VERSION 5.8 ;
BUSBITCHARS "[]" ;
DIVIDERCHAR "/" ;
UNITS
    DATABASE MICRONS 1000 ;
END UNITS

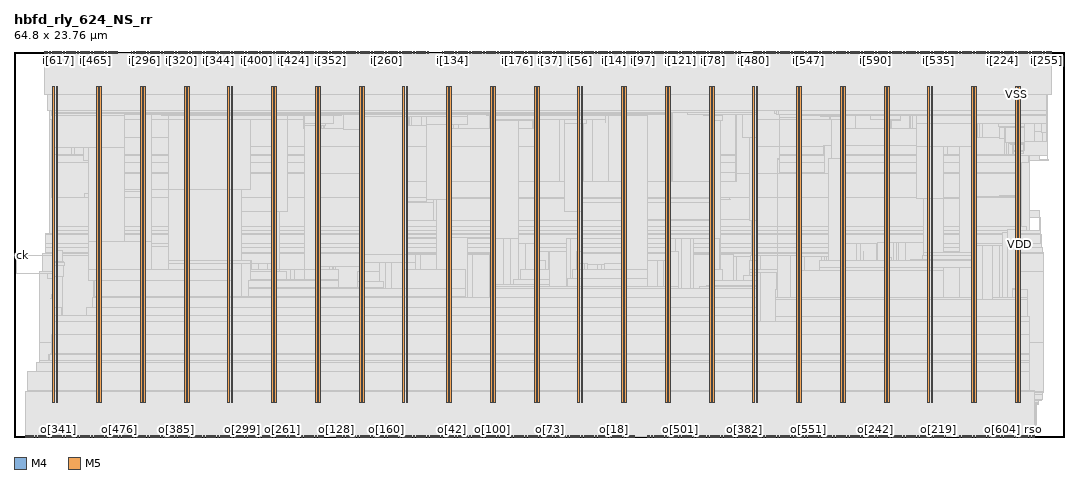
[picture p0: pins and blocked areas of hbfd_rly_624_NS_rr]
MACRO hbfd_rly_624_NS_rr
  FOREIGN hbfd_rly_624_NS_rr 0 0 ;
  CLASS BLOCK ;
  SIZE 64.8 BY 23.76 ;
  PIN ck
    DIRECTION INPUT ;
    USE SIGNAL ;
    PORT
      LAYER M4 ;
        RECT  0 11.184 0.084 11.208 ;
    END
  END ck
  PIN i[0]
    DIRECTION INPUT ;
    USE SIGNAL ;
    PORT
      LAYER M5 ;
        RECT  35.664 23.676 35.688 23.76 ;
    END
  END i[0]
  PIN i[100]
    DIRECTION INPUT ;
    USE SIGNAL ;
    PORT
      LAYER M5 ;
        RECT  39.12 23.676 39.144 23.76 ;
    END
  END i[100]
  PIN i[101]
    DIRECTION INPUT ;
    USE SIGNAL ;
    PORT
      LAYER M5 ;
        RECT  39.216 23.676 39.24 23.76 ;
    END
  END i[101]
  PIN i[102]
    DIRECTION INPUT ;
    USE SIGNAL ;
    PORT
      LAYER M5 ;
        RECT  39.312 23.676 39.336 23.76 ;
    END
  END i[102]
  PIN i[103]
    DIRECTION INPUT ;
    USE SIGNAL ;
    PORT
      LAYER M5 ;
        RECT  39.408 23.676 39.432 23.76 ;
    END
  END i[103]
  PIN i[104]
    DIRECTION INPUT ;
    USE SIGNAL ;
    PORT
      LAYER M5 ;
        RECT  39.504 23.676 39.528 23.76 ;
    END
  END i[104]
  PIN i[105]
    DIRECTION INPUT ;
    USE SIGNAL ;
    PORT
      LAYER M5 ;
        RECT  39.6 23.676 39.624 23.76 ;
    END
  END i[105]
  PIN i[106]
    DIRECTION INPUT ;
    USE SIGNAL ;
    PORT
      LAYER M5 ;
        RECT  39.696 23.676 39.72 23.76 ;
    END
  END i[106]
  PIN i[107]
    DIRECTION INPUT ;
    USE SIGNAL ;
    PORT
      LAYER M5 ;
        RECT  39.792 23.676 39.816 23.76 ;
    END
  END i[107]
  PIN i[108]
    DIRECTION INPUT ;
    USE SIGNAL ;
    PORT
      LAYER M5 ;
        RECT  39.888 23.676 39.912 23.76 ;
    END
  END i[108]
  PIN i[109]
    DIRECTION INPUT ;
    USE SIGNAL ;
    PORT
      LAYER M5 ;
        RECT  39.984 23.676 40.008 23.76 ;
    END
  END i[109]
  PIN i[10]
    DIRECTION INPUT ;
    USE SIGNAL ;
    PORT
      LAYER M5 ;
        RECT  36.624 23.676 36.648 23.76 ;
    END
  END i[10]
  PIN i[110]
    DIRECTION INPUT ;
    USE SIGNAL ;
    PORT
      LAYER M5 ;
        RECT  40.08 23.676 40.104 23.76 ;
    END
  END i[110]
  PIN i[111]
    DIRECTION INPUT ;
    USE SIGNAL ;
    PORT
      LAYER M5 ;
        RECT  40.176 23.676 40.2 23.76 ;
    END
  END i[111]
  PIN i[112]
    DIRECTION INPUT ;
    USE SIGNAL ;
    PORT
      LAYER M5 ;
        RECT  40.272 23.676 40.296 23.76 ;
    END
  END i[112]
  PIN i[113]
    DIRECTION INPUT ;
    USE SIGNAL ;
    PORT
      LAYER M5 ;
        RECT  40.368 23.676 40.392 23.76 ;
    END
  END i[113]
  PIN i[114]
    DIRECTION INPUT ;
    USE SIGNAL ;
    PORT
      LAYER M5 ;
        RECT  40.464 23.676 40.488 23.76 ;
    END
  END i[114]
  PIN i[115]
    DIRECTION INPUT ;
    USE SIGNAL ;
    PORT
      LAYER M5 ;
        RECT  40.56 23.676 40.584 23.76 ;
    END
  END i[115]
  PIN i[116]
    DIRECTION INPUT ;
    USE SIGNAL ;
    PORT
      LAYER M5 ;
        RECT  40.656 23.676 40.68 23.76 ;
    END
  END i[116]
  PIN i[117]
    DIRECTION INPUT ;
    USE SIGNAL ;
    PORT
      LAYER M5 ;
        RECT  40.752 23.676 40.776 23.76 ;
    END
  END i[117]
  PIN i[118]
    DIRECTION INPUT ;
    USE SIGNAL ;
    PORT
      LAYER M5 ;
        RECT  40.848 23.676 40.872 23.76 ;
    END
  END i[118]
  PIN i[119]
    DIRECTION INPUT ;
    USE SIGNAL ;
    PORT
      LAYER M5 ;
        RECT  40.944 23.676 40.968 23.76 ;
    END
  END i[119]
  PIN i[11]
    DIRECTION INPUT ;
    USE SIGNAL ;
    PORT
      LAYER M5 ;
        RECT  36.72 23.676 36.744 23.76 ;
    END
  END i[11]
  PIN i[120]
    DIRECTION INPUT ;
    USE SIGNAL ;
    PORT
      LAYER M5 ;
        RECT  41.04 23.676 41.064 23.76 ;
    END
  END i[120]
  PIN i[121]
    DIRECTION INPUT ;
    USE SIGNAL ;
    PORT
      LAYER M5 ;
        RECT  41.136 23.676 41.16 23.76 ;
    END
  END i[121]
  PIN i[122]
    DIRECTION INPUT ;
    USE SIGNAL ;
    PORT
      LAYER M5 ;
        RECT  41.232 23.676 41.256 23.76 ;
    END
  END i[122]
  PIN i[123]
    DIRECTION INPUT ;
    USE SIGNAL ;
    PORT
      LAYER M5 ;
        RECT  41.328 23.676 41.352 23.76 ;
    END
  END i[123]
  PIN i[124]
    DIRECTION INPUT ;
    USE SIGNAL ;
    PORT
      LAYER M5 ;
        RECT  41.424 23.676 41.448 23.76 ;
    END
  END i[124]
  PIN i[125]
    DIRECTION INPUT ;
    USE SIGNAL ;
    PORT
      LAYER M5 ;
        RECT  41.52 23.676 41.544 23.76 ;
    END
  END i[125]
  PIN i[126]
    DIRECTION INPUT ;
    USE SIGNAL ;
    PORT
      LAYER M5 ;
        RECT  41.616 23.676 41.64 23.76 ;
    END
  END i[126]
  PIN i[127]
    DIRECTION INPUT ;
    USE SIGNAL ;
    PORT
      LAYER M5 ;
        RECT  41.712 23.676 41.736 23.76 ;
    END
  END i[127]
  PIN i[128]
    DIRECTION INPUT ;
    USE SIGNAL ;
    PORT
      LAYER M5 ;
        RECT  26.448 23.676 26.472 23.76 ;
    END
  END i[128]
  PIN i[129]
    DIRECTION INPUT ;
    USE SIGNAL ;
    PORT
      LAYER M5 ;
        RECT  26.544 23.676 26.568 23.76 ;
    END
  END i[129]
  PIN i[12]
    DIRECTION INPUT ;
    USE SIGNAL ;
    PORT
      LAYER M5 ;
        RECT  36.816 23.676 36.84 23.76 ;
    END
  END i[12]
  PIN i[130]
    DIRECTION INPUT ;
    USE SIGNAL ;
    PORT
      LAYER M5 ;
        RECT  26.64 23.676 26.664 23.76 ;
    END
  END i[130]
  PIN i[131]
    DIRECTION INPUT ;
    USE SIGNAL ;
    PORT
      LAYER M5 ;
        RECT  26.736 23.676 26.76 23.76 ;
    END
  END i[131]
  PIN i[132]
    DIRECTION INPUT ;
    USE SIGNAL ;
    PORT
      LAYER M5 ;
        RECT  26.832 23.676 26.856 23.76 ;
    END
  END i[132]
  PIN i[133]
    DIRECTION INPUT ;
    USE SIGNAL ;
    PORT
      LAYER M5 ;
        RECT  26.928 23.676 26.952 23.76 ;
    END
  END i[133]
  PIN i[134]
    DIRECTION INPUT ;
    USE SIGNAL ;
    PORT
      LAYER M5 ;
        RECT  27.024 23.676 27.048 23.76 ;
    END
  END i[134]
  PIN i[135]
    DIRECTION INPUT ;
    USE SIGNAL ;
    PORT
      LAYER M5 ;
        RECT  27.12 23.676 27.144 23.76 ;
    END
  END i[135]
  PIN i[136]
    DIRECTION INPUT ;
    USE SIGNAL ;
    PORT
      LAYER M5 ;
        RECT  27.216 23.676 27.24 23.76 ;
    END
  END i[136]
  PIN i[137]
    DIRECTION INPUT ;
    USE SIGNAL ;
    PORT
      LAYER M5 ;
        RECT  27.312 23.676 27.336 23.76 ;
    END
  END i[137]
  PIN i[138]
    DIRECTION INPUT ;
    USE SIGNAL ;
    PORT
      LAYER M5 ;
        RECT  27.408 23.676 27.432 23.76 ;
    END
  END i[138]
  PIN i[139]
    DIRECTION INPUT ;
    USE SIGNAL ;
    PORT
      LAYER M5 ;
        RECT  27.504 23.676 27.528 23.76 ;
    END
  END i[139]
  PIN i[13]
    DIRECTION INPUT ;
    USE SIGNAL ;
    PORT
      LAYER M5 ;
        RECT  36.912 23.676 36.936 23.76 ;
    END
  END i[13]
  PIN i[140]
    DIRECTION INPUT ;
    USE SIGNAL ;
    PORT
      LAYER M5 ;
        RECT  27.6 23.676 27.624 23.76 ;
    END
  END i[140]
  PIN i[141]
    DIRECTION INPUT ;
    USE SIGNAL ;
    PORT
      LAYER M5 ;
        RECT  27.696 23.676 27.72 23.76 ;
    END
  END i[141]
  PIN i[142]
    DIRECTION INPUT ;
    USE SIGNAL ;
    PORT
      LAYER M5 ;
        RECT  27.792 23.676 27.816 23.76 ;
    END
  END i[142]
  PIN i[143]
    DIRECTION INPUT ;
    USE SIGNAL ;
    PORT
      LAYER M5 ;
        RECT  27.888 23.676 27.912 23.76 ;
    END
  END i[143]
  PIN i[144]
    DIRECTION INPUT ;
    USE SIGNAL ;
    PORT
      LAYER M5 ;
        RECT  27.984 23.676 28.008 23.76 ;
    END
  END i[144]
  PIN i[145]
    DIRECTION INPUT ;
    USE SIGNAL ;
    PORT
      LAYER M5 ;
        RECT  28.08 23.676 28.104 23.76 ;
    END
  END i[145]
  PIN i[146]
    DIRECTION INPUT ;
    USE SIGNAL ;
    PORT
      LAYER M5 ;
        RECT  28.176 23.676 28.2 23.76 ;
    END
  END i[146]
  PIN i[147]
    DIRECTION INPUT ;
    USE SIGNAL ;
    PORT
      LAYER M5 ;
        RECT  28.272 23.676 28.296 23.76 ;
    END
  END i[147]
  PIN i[148]
    DIRECTION INPUT ;
    USE SIGNAL ;
    PORT
      LAYER M5 ;
        RECT  28.368 23.676 28.392 23.76 ;
    END
  END i[148]
  PIN i[149]
    DIRECTION INPUT ;
    USE SIGNAL ;
    PORT
      LAYER M5 ;
        RECT  28.464 23.676 28.488 23.76 ;
    END
  END i[149]
  PIN i[14]
    DIRECTION INPUT ;
    USE SIGNAL ;
    PORT
      LAYER M5 ;
        RECT  37.008 23.676 37.032 23.76 ;
    END
  END i[14]
  PIN i[150]
    DIRECTION INPUT ;
    USE SIGNAL ;
    PORT
      LAYER M5 ;
        RECT  28.56 23.676 28.584 23.76 ;
    END
  END i[150]
  PIN i[151]
    DIRECTION INPUT ;
    USE SIGNAL ;
    PORT
      LAYER M5 ;
        RECT  28.656 23.676 28.68 23.76 ;
    END
  END i[151]
  PIN i[152]
    DIRECTION INPUT ;
    USE SIGNAL ;
    PORT
      LAYER M5 ;
        RECT  28.752 23.676 28.776 23.76 ;
    END
  END i[152]
  PIN i[153]
    DIRECTION INPUT ;
    USE SIGNAL ;
    PORT
      LAYER M5 ;
        RECT  28.848 23.676 28.872 23.76 ;
    END
  END i[153]
  PIN i[154]
    DIRECTION INPUT ;
    USE SIGNAL ;
    PORT
      LAYER M5 ;
        RECT  28.944 23.676 28.968 23.76 ;
    END
  END i[154]
  PIN i[155]
    DIRECTION INPUT ;
    USE SIGNAL ;
    PORT
      LAYER M5 ;
        RECT  29.04 23.676 29.064 23.76 ;
    END
  END i[155]
  PIN i[156]
    DIRECTION INPUT ;
    USE SIGNAL ;
    PORT
      LAYER M5 ;
        RECT  29.136 23.676 29.16 23.76 ;
    END
  END i[156]
  PIN i[157]
    DIRECTION INPUT ;
    USE SIGNAL ;
    PORT
      LAYER M5 ;
        RECT  29.232 23.676 29.256 23.76 ;
    END
  END i[157]
  PIN i[158]
    DIRECTION INPUT ;
    USE SIGNAL ;
    PORT
      LAYER M5 ;
        RECT  29.328 23.676 29.352 23.76 ;
    END
  END i[158]
  PIN i[159]
    DIRECTION INPUT ;
    USE SIGNAL ;
    PORT
      LAYER M5 ;
        RECT  29.424 23.676 29.448 23.76 ;
    END
  END i[159]
  PIN i[15]
    DIRECTION INPUT ;
    USE SIGNAL ;
    PORT
      LAYER M5 ;
        RECT  37.104 23.676 37.128 23.76 ;
    END
  END i[15]
  PIN i[160]
    DIRECTION INPUT ;
    USE SIGNAL ;
    PORT
      LAYER M5 ;
        RECT  29.52 23.676 29.544 23.76 ;
    END
  END i[160]
  PIN i[161]
    DIRECTION INPUT ;
    USE SIGNAL ;
    PORT
      LAYER M5 ;
        RECT  29.616 23.676 29.64 23.76 ;
    END
  END i[161]
  PIN i[162]
    DIRECTION INPUT ;
    USE SIGNAL ;
    PORT
      LAYER M5 ;
        RECT  29.712 23.676 29.736 23.76 ;
    END
  END i[162]
  PIN i[163]
    DIRECTION INPUT ;
    USE SIGNAL ;
    PORT
      LAYER M5 ;
        RECT  29.808 23.676 29.832 23.76 ;
    END
  END i[163]
  PIN i[164]
    DIRECTION INPUT ;
    USE SIGNAL ;
    PORT
      LAYER M5 ;
        RECT  29.904 23.676 29.928 23.76 ;
    END
  END i[164]
  PIN i[165]
    DIRECTION INPUT ;
    USE SIGNAL ;
    PORT
      LAYER M5 ;
        RECT  30 23.676 30.024 23.76 ;
    END
  END i[165]
  PIN i[166]
    DIRECTION INPUT ;
    USE SIGNAL ;
    PORT
      LAYER M5 ;
        RECT  30.096 23.676 30.12 23.76 ;
    END
  END i[166]
  PIN i[167]
    DIRECTION INPUT ;
    USE SIGNAL ;
    PORT
      LAYER M5 ;
        RECT  30.192 23.676 30.216 23.76 ;
    END
  END i[167]
  PIN i[168]
    DIRECTION INPUT ;
    USE SIGNAL ;
    PORT
      LAYER M5 ;
        RECT  30.288 23.676 30.312 23.76 ;
    END
  END i[168]
  PIN i[169]
    DIRECTION INPUT ;
    USE SIGNAL ;
    PORT
      LAYER M5 ;
        RECT  30.384 23.676 30.408 23.76 ;
    END
  END i[169]
  PIN i[16]
    DIRECTION INPUT ;
    USE SIGNAL ;
    PORT
      LAYER M5 ;
        RECT  37.2 23.676 37.224 23.76 ;
    END
  END i[16]
  PIN i[170]
    DIRECTION INPUT ;
    USE SIGNAL ;
    PORT
      LAYER M5 ;
        RECT  30.48 23.676 30.504 23.76 ;
    END
  END i[170]
  PIN i[171]
    DIRECTION INPUT ;
    USE SIGNAL ;
    PORT
      LAYER M5 ;
        RECT  30.576 23.676 30.6 23.76 ;
    END
  END i[171]
  PIN i[172]
    DIRECTION INPUT ;
    USE SIGNAL ;
    PORT
      LAYER M5 ;
        RECT  30.672 23.676 30.696 23.76 ;
    END
  END i[172]
  PIN i[173]
    DIRECTION INPUT ;
    USE SIGNAL ;
    PORT
      LAYER M5 ;
        RECT  30.768 23.676 30.792 23.76 ;
    END
  END i[173]
  PIN i[174]
    DIRECTION INPUT ;
    USE SIGNAL ;
    PORT
      LAYER M5 ;
        RECT  30.864 23.676 30.888 23.76 ;
    END
  END i[174]
  PIN i[175]
    DIRECTION INPUT ;
    USE SIGNAL ;
    PORT
      LAYER M5 ;
        RECT  30.96 23.676 30.984 23.76 ;
    END
  END i[175]
  PIN i[176]
    DIRECTION INPUT ;
    USE SIGNAL ;
    PORT
      LAYER M5 ;
        RECT  31.056 23.676 31.08 23.76 ;
    END
  END i[176]
  PIN i[177]
    DIRECTION INPUT ;
    USE SIGNAL ;
    PORT
      LAYER M5 ;
        RECT  31.152 23.676 31.176 23.76 ;
    END
  END i[177]
  PIN i[178]
    DIRECTION INPUT ;
    USE SIGNAL ;
    PORT
      LAYER M5 ;
        RECT  31.248 23.676 31.272 23.76 ;
    END
  END i[178]
  PIN i[179]
    DIRECTION INPUT ;
    USE SIGNAL ;
    PORT
      LAYER M5 ;
        RECT  31.344 23.676 31.368 23.76 ;
    END
  END i[179]
  PIN i[17]
    DIRECTION INPUT ;
    USE SIGNAL ;
    PORT
      LAYER M5 ;
        RECT  37.296 23.676 37.32 23.76 ;
    END
  END i[17]
  PIN i[180]
    DIRECTION INPUT ;
    USE SIGNAL ;
    PORT
      LAYER M5 ;
        RECT  31.44 23.676 31.464 23.76 ;
    END
  END i[180]
  PIN i[181]
    DIRECTION INPUT ;
    USE SIGNAL ;
    PORT
      LAYER M5 ;
        RECT  31.536 23.676 31.56 23.76 ;
    END
  END i[181]
  PIN i[182]
    DIRECTION INPUT ;
    USE SIGNAL ;
    PORT
      LAYER M5 ;
        RECT  31.632 23.676 31.656 23.76 ;
    END
  END i[182]
  PIN i[183]
    DIRECTION INPUT ;
    USE SIGNAL ;
    PORT
      LAYER M5 ;
        RECT  31.728 23.676 31.752 23.76 ;
    END
  END i[183]
  PIN i[184]
    DIRECTION INPUT ;
    USE SIGNAL ;
    PORT
      LAYER M5 ;
        RECT  31.824 23.676 31.848 23.76 ;
    END
  END i[184]
  PIN i[185]
    DIRECTION INPUT ;
    USE SIGNAL ;
    PORT
      LAYER M5 ;
        RECT  31.92 23.676 31.944 23.76 ;
    END
  END i[185]
  PIN i[186]
    DIRECTION INPUT ;
    USE SIGNAL ;
    PORT
      LAYER M5 ;
        RECT  32.016 23.676 32.04 23.76 ;
    END
  END i[186]
  PIN i[187]
    DIRECTION INPUT ;
    USE SIGNAL ;
    PORT
      LAYER M5 ;
        RECT  32.112 23.676 32.136 23.76 ;
    END
  END i[187]
  PIN i[188]
    DIRECTION INPUT ;
    USE SIGNAL ;
    PORT
      LAYER M5 ;
        RECT  32.208 23.676 32.232 23.76 ;
    END
  END i[188]
  PIN i[189]
    DIRECTION INPUT ;
    USE SIGNAL ;
    PORT
      LAYER M5 ;
        RECT  32.304 23.676 32.328 23.76 ;
    END
  END i[189]
  PIN i[18]
    DIRECTION INPUT ;
    USE SIGNAL ;
    PORT
      LAYER M5 ;
        RECT  37.392 23.676 37.416 23.76 ;
    END
  END i[18]
  PIN i[190]
    DIRECTION INPUT ;
    USE SIGNAL ;
    PORT
      LAYER M5 ;
        RECT  32.4 23.676 32.424 23.76 ;
    END
  END i[190]
  PIN i[191]
    DIRECTION INPUT ;
    USE SIGNAL ;
    PORT
      LAYER M5 ;
        RECT  32.496 23.676 32.52 23.76 ;
    END
  END i[191]
  PIN i[192]
    DIRECTION INPUT ;
    USE SIGNAL ;
    PORT
      LAYER M5 ;
        RECT  57.936 23.676 57.96 23.76 ;
    END
  END i[192]
  PIN i[193]
    DIRECTION INPUT ;
    USE SIGNAL ;
    PORT
      LAYER M5 ;
        RECT  58.032 23.676 58.056 23.76 ;
    END
  END i[193]
  PIN i[194]
    DIRECTION INPUT ;
    USE SIGNAL ;
    PORT
      LAYER M5 ;
        RECT  58.128 23.676 58.152 23.76 ;
    END
  END i[194]
  PIN i[195]
    DIRECTION INPUT ;
    USE SIGNAL ;
    PORT
      LAYER M5 ;
        RECT  58.224 23.676 58.248 23.76 ;
    END
  END i[195]
  PIN i[196]
    DIRECTION INPUT ;
    USE SIGNAL ;
    PORT
      LAYER M5 ;
        RECT  58.32 23.676 58.344 23.76 ;
    END
  END i[196]
  PIN i[197]
    DIRECTION INPUT ;
    USE SIGNAL ;
    PORT
      LAYER M5 ;
        RECT  58.416 23.676 58.44 23.76 ;
    END
  END i[197]
  PIN i[198]
    DIRECTION INPUT ;
    USE SIGNAL ;
    PORT
      LAYER M5 ;
        RECT  58.512 23.676 58.536 23.76 ;
    END
  END i[198]
  PIN i[199]
    DIRECTION INPUT ;
    USE SIGNAL ;
    PORT
      LAYER M5 ;
        RECT  58.608 23.676 58.632 23.76 ;
    END
  END i[199]
  PIN i[19]
    DIRECTION INPUT ;
    USE SIGNAL ;
    PORT
      LAYER M5 ;
        RECT  37.488 23.676 37.512 23.76 ;
    END
  END i[19]
  PIN i[1]
    DIRECTION INPUT ;
    USE SIGNAL ;
    PORT
      LAYER M5 ;
        RECT  35.76 23.676 35.784 23.76 ;
    END
  END i[1]
  PIN i[200]
    DIRECTION INPUT ;
    USE SIGNAL ;
    PORT
      LAYER M5 ;
        RECT  58.704 23.676 58.728 23.76 ;
    END
  END i[200]
  PIN i[201]
    DIRECTION INPUT ;
    USE SIGNAL ;
    PORT
      LAYER M5 ;
        RECT  58.8 23.676 58.824 23.76 ;
    END
  END i[201]
  PIN i[202]
    DIRECTION INPUT ;
    USE SIGNAL ;
    PORT
      LAYER M5 ;
        RECT  58.896 23.676 58.92 23.76 ;
    END
  END i[202]
  PIN i[203]
    DIRECTION INPUT ;
    USE SIGNAL ;
    PORT
      LAYER M5 ;
        RECT  58.992 23.676 59.016 23.76 ;
    END
  END i[203]
  PIN i[204]
    DIRECTION INPUT ;
    USE SIGNAL ;
    PORT
      LAYER M5 ;
        RECT  59.088 23.676 59.112 23.76 ;
    END
  END i[204]
  PIN i[205]
    DIRECTION INPUT ;
    USE SIGNAL ;
    PORT
      LAYER M5 ;
        RECT  59.184 23.676 59.208 23.76 ;
    END
  END i[205]
  PIN i[206]
    DIRECTION INPUT ;
    USE SIGNAL ;
    PORT
      LAYER M5 ;
        RECT  59.28 23.676 59.304 23.76 ;
    END
  END i[206]
  PIN i[207]
    DIRECTION INPUT ;
    USE SIGNAL ;
    PORT
      LAYER M5 ;
        RECT  59.376 23.676 59.4 23.76 ;
    END
  END i[207]
  PIN i[208]
    DIRECTION INPUT ;
    USE SIGNAL ;
    PORT
      LAYER M5 ;
        RECT  59.472 23.676 59.496 23.76 ;
    END
  END i[208]
  PIN i[209]
    DIRECTION INPUT ;
    USE SIGNAL ;
    PORT
      LAYER M5 ;
        RECT  59.568 23.676 59.592 23.76 ;
    END
  END i[209]
  PIN i[20]
    DIRECTION INPUT ;
    USE SIGNAL ;
    PORT
      LAYER M5 ;
        RECT  37.584 23.676 37.608 23.76 ;
    END
  END i[20]
  PIN i[210]
    DIRECTION INPUT ;
    USE SIGNAL ;
    PORT
      LAYER M5 ;
        RECT  59.664 23.676 59.688 23.76 ;
    END
  END i[210]
  PIN i[211]
    DIRECTION INPUT ;
    USE SIGNAL ;
    PORT
      LAYER M5 ;
        RECT  59.76 23.676 59.784 23.76 ;
    END
  END i[211]
  PIN i[212]
    DIRECTION INPUT ;
    USE SIGNAL ;
    PORT
      LAYER M5 ;
        RECT  59.856 23.676 59.88 23.76 ;
    END
  END i[212]
  PIN i[213]
    DIRECTION INPUT ;
    USE SIGNAL ;
    PORT
      LAYER M5 ;
        RECT  59.952 23.676 59.976 23.76 ;
    END
  END i[213]
  PIN i[214]
    DIRECTION INPUT ;
    USE SIGNAL ;
    PORT
      LAYER M5 ;
        RECT  60.048 23.676 60.072 23.76 ;
    END
  END i[214]
  PIN i[215]
    DIRECTION INPUT ;
    USE SIGNAL ;
    PORT
      LAYER M5 ;
        RECT  60.144 23.676 60.168 23.76 ;
    END
  END i[215]
  PIN i[216]
    DIRECTION INPUT ;
    USE SIGNAL ;
    PORT
      LAYER M5 ;
        RECT  60.24 23.676 60.264 23.76 ;
    END
  END i[216]
  PIN i[217]
    DIRECTION INPUT ;
    USE SIGNAL ;
    PORT
      LAYER M5 ;
        RECT  60.336 23.676 60.36 23.76 ;
    END
  END i[217]
  PIN i[218]
    DIRECTION INPUT ;
    USE SIGNAL ;
    PORT
      LAYER M5 ;
        RECT  60.432 23.676 60.456 23.76 ;
    END
  END i[218]
  PIN i[219]
    DIRECTION INPUT ;
    USE SIGNAL ;
    PORT
      LAYER M5 ;
        RECT  60.528 23.676 60.552 23.76 ;
    END
  END i[219]
  PIN i[21]
    DIRECTION INPUT ;
    USE SIGNAL ;
    PORT
      LAYER M5 ;
        RECT  37.68 23.676 37.704 23.76 ;
    END
  END i[21]
  PIN i[220]
    DIRECTION INPUT ;
    USE SIGNAL ;
    PORT
      LAYER M5 ;
        RECT  60.624 23.676 60.648 23.76 ;
    END
  END i[220]
  PIN i[221]
    DIRECTION INPUT ;
    USE SIGNAL ;
    PORT
      LAYER M5 ;
        RECT  60.72 23.676 60.744 23.76 ;
    END
  END i[221]
  PIN i[222]
    DIRECTION INPUT ;
    USE SIGNAL ;
    PORT
      LAYER M5 ;
        RECT  60.816 23.676 60.84 23.76 ;
    END
  END i[222]
  PIN i[223]
    DIRECTION INPUT ;
    USE SIGNAL ;
    PORT
      LAYER M5 ;
        RECT  60.912 23.676 60.936 23.76 ;
    END
  END i[223]
  PIN i[224]
    DIRECTION INPUT ;
    USE SIGNAL ;
    PORT
      LAYER M5 ;
        RECT  61.008 23.676 61.032 23.76 ;
    END
  END i[224]
  PIN i[225]
    DIRECTION INPUT ;
    USE SIGNAL ;
    PORT
      LAYER M5 ;
        RECT  61.104 23.676 61.128 23.76 ;
    END
  END i[225]
  PIN i[226]
    DIRECTION INPUT ;
    USE SIGNAL ;
    PORT
      LAYER M5 ;
        RECT  61.2 23.676 61.224 23.76 ;
    END
  END i[226]
  PIN i[227]
    DIRECTION INPUT ;
    USE SIGNAL ;
    PORT
      LAYER M5 ;
        RECT  61.296 23.676 61.32 23.76 ;
    END
  END i[227]
  PIN i[228]
    DIRECTION INPUT ;
    USE SIGNAL ;
    PORT
      LAYER M5 ;
        RECT  61.392 23.676 61.416 23.76 ;
    END
  END i[228]
  PIN i[229]
    DIRECTION INPUT ;
    USE SIGNAL ;
    PORT
      LAYER M5 ;
        RECT  61.488 23.676 61.512 23.76 ;
    END
  END i[229]
  PIN i[22]
    DIRECTION INPUT ;
    USE SIGNAL ;
    PORT
      LAYER M5 ;
        RECT  37.776 23.676 37.8 23.76 ;
    END
  END i[22]
  PIN i[230]
    DIRECTION INPUT ;
    USE SIGNAL ;
    PORT
      LAYER M5 ;
        RECT  61.584 23.676 61.608 23.76 ;
    END
  END i[230]
  PIN i[231]
    DIRECTION INPUT ;
    USE SIGNAL ;
    PORT
      LAYER M5 ;
        RECT  61.68 23.676 61.704 23.76 ;
    END
  END i[231]
  PIN i[232]
    DIRECTION INPUT ;
    USE SIGNAL ;
    PORT
      LAYER M5 ;
        RECT  61.776 23.676 61.8 23.76 ;
    END
  END i[232]
  PIN i[233]
    DIRECTION INPUT ;
    USE SIGNAL ;
    PORT
      LAYER M5 ;
        RECT  61.872 23.676 61.896 23.76 ;
    END
  END i[233]
  PIN i[234]
    DIRECTION INPUT ;
    USE SIGNAL ;
    PORT
      LAYER M5 ;
        RECT  61.968 23.676 61.992 23.76 ;
    END
  END i[234]
  PIN i[235]
    DIRECTION INPUT ;
    USE SIGNAL ;
    PORT
      LAYER M5 ;
        RECT  62.064 23.676 62.088 23.76 ;
    END
  END i[235]
  PIN i[236]
    DIRECTION INPUT ;
    USE SIGNAL ;
    PORT
      LAYER M5 ;
        RECT  62.16 23.676 62.184 23.76 ;
    END
  END i[236]
  PIN i[237]
    DIRECTION INPUT ;
    USE SIGNAL ;
    PORT
      LAYER M5 ;
        RECT  62.256 23.676 62.28 23.76 ;
    END
  END i[237]
  PIN i[238]
    DIRECTION INPUT ;
    USE SIGNAL ;
    PORT
      LAYER M5 ;
        RECT  62.352 23.676 62.376 23.76 ;
    END
  END i[238]
  PIN i[239]
    DIRECTION INPUT ;
    USE SIGNAL ;
    PORT
      LAYER M5 ;
        RECT  62.448 23.676 62.472 23.76 ;
    END
  END i[239]
  PIN i[23]
    DIRECTION INPUT ;
    USE SIGNAL ;
    PORT
      LAYER M5 ;
        RECT  37.872 23.676 37.896 23.76 ;
    END
  END i[23]
  PIN i[240]
    DIRECTION INPUT ;
    USE SIGNAL ;
    PORT
      LAYER M5 ;
        RECT  62.544 23.676 62.568 23.76 ;
    END
  END i[240]
  PIN i[241]
    DIRECTION INPUT ;
    USE SIGNAL ;
    PORT
      LAYER M5 ;
        RECT  62.64 23.676 62.664 23.76 ;
    END
  END i[241]
  PIN i[242]
    DIRECTION INPUT ;
    USE SIGNAL ;
    PORT
      LAYER M5 ;
        RECT  62.736 23.676 62.76 23.76 ;
    END
  END i[242]
  PIN i[243]
    DIRECTION INPUT ;
    USE SIGNAL ;
    PORT
      LAYER M5 ;
        RECT  62.832 23.676 62.856 23.76 ;
    END
  END i[243]
  PIN i[244]
    DIRECTION INPUT ;
    USE SIGNAL ;
    PORT
      LAYER M5 ;
        RECT  62.928 23.676 62.952 23.76 ;
    END
  END i[244]
  PIN i[245]
    DIRECTION INPUT ;
    USE SIGNAL ;
    PORT
      LAYER M5 ;
        RECT  63.024 23.676 63.048 23.76 ;
    END
  END i[245]
  PIN i[246]
    DIRECTION INPUT ;
    USE SIGNAL ;
    PORT
      LAYER M5 ;
        RECT  63.12 23.676 63.144 23.76 ;
    END
  END i[246]
  PIN i[247]
    DIRECTION INPUT ;
    USE SIGNAL ;
    PORT
      LAYER M5 ;
        RECT  63.216 23.676 63.24 23.76 ;
    END
  END i[247]
  PIN i[248]
    DIRECTION INPUT ;
    USE SIGNAL ;
    PORT
      LAYER M5 ;
        RECT  63.312 23.676 63.336 23.76 ;
    END
  END i[248]
  PIN i[249]
    DIRECTION INPUT ;
    USE SIGNAL ;
    PORT
      LAYER M5 ;
        RECT  63.408 23.676 63.432 23.76 ;
    END
  END i[249]
  PIN i[24]
    DIRECTION INPUT ;
    USE SIGNAL ;
    PORT
      LAYER M5 ;
        RECT  37.968 23.676 37.992 23.76 ;
    END
  END i[24]
  PIN i[250]
    DIRECTION INPUT ;
    USE SIGNAL ;
    PORT
      LAYER M5 ;
        RECT  63.504 23.676 63.528 23.76 ;
    END
  END i[250]
  PIN i[251]
    DIRECTION INPUT ;
    USE SIGNAL ;
    PORT
      LAYER M5 ;
        RECT  63.6 23.676 63.624 23.76 ;
    END
  END i[251]
  PIN i[252]
    DIRECTION INPUT ;
    USE SIGNAL ;
    PORT
      LAYER M5 ;
        RECT  63.696 23.676 63.72 23.76 ;
    END
  END i[252]
  PIN i[253]
    DIRECTION INPUT ;
    USE SIGNAL ;
    PORT
      LAYER M5 ;
        RECT  63.792 23.676 63.816 23.76 ;
    END
  END i[253]
  PIN i[254]
    DIRECTION INPUT ;
    USE SIGNAL ;
    PORT
      LAYER M5 ;
        RECT  63.888 23.676 63.912 23.76 ;
    END
  END i[254]
  PIN i[255]
    DIRECTION INPUT ;
    USE SIGNAL ;
    PORT
      LAYER M5 ;
        RECT  63.984 23.676 64.008 23.76 ;
    END
  END i[255]
  PIN i[256]
    DIRECTION INPUT ;
    USE SIGNAL ;
    PORT
      LAYER M5 ;
        RECT  22.608 23.676 22.632 23.76 ;
    END
  END i[256]
  PIN i[257]
    DIRECTION INPUT ;
    USE SIGNAL ;
    PORT
      LAYER M5 ;
        RECT  22.704 23.676 22.728 23.76 ;
    END
  END i[257]
  PIN i[258]
    DIRECTION INPUT ;
    USE SIGNAL ;
    PORT
      LAYER M5 ;
        RECT  22.8 23.676 22.824 23.76 ;
    END
  END i[258]
  PIN i[259]
    DIRECTION INPUT ;
    USE SIGNAL ;
    PORT
      LAYER M5 ;
        RECT  22.896 23.676 22.92 23.76 ;
    END
  END i[259]
  PIN i[25]
    DIRECTION INPUT ;
    USE SIGNAL ;
    PORT
      LAYER M5 ;
        RECT  38.064 23.676 38.088 23.76 ;
    END
  END i[25]
  PIN i[260]
    DIRECTION INPUT ;
    USE SIGNAL ;
    PORT
      LAYER M5 ;
        RECT  22.992 23.676 23.016 23.76 ;
    END
  END i[260]
  PIN i[261]
    DIRECTION INPUT ;
    USE SIGNAL ;
    PORT
      LAYER M5 ;
        RECT  23.088 23.676 23.112 23.76 ;
    END
  END i[261]
  PIN i[262]
    DIRECTION INPUT ;
    USE SIGNAL ;
    PORT
      LAYER M5 ;
        RECT  23.184 23.676 23.208 23.76 ;
    END
  END i[262]
  PIN i[263]
    DIRECTION INPUT ;
    USE SIGNAL ;
    PORT
      LAYER M5 ;
        RECT  23.28 23.676 23.304 23.76 ;
    END
  END i[263]
  PIN i[264]
    DIRECTION INPUT ;
    USE SIGNAL ;
    PORT
      LAYER M5 ;
        RECT  23.376 23.676 23.4 23.76 ;
    END
  END i[264]
  PIN i[265]
    DIRECTION INPUT ;
    USE SIGNAL ;
    PORT
      LAYER M5 ;
        RECT  23.472 23.676 23.496 23.76 ;
    END
  END i[265]
  PIN i[266]
    DIRECTION INPUT ;
    USE SIGNAL ;
    PORT
      LAYER M5 ;
        RECT  23.568 23.676 23.592 23.76 ;
    END
  END i[266]
  PIN i[267]
    DIRECTION INPUT ;
    USE SIGNAL ;
    PORT
      LAYER M5 ;
        RECT  23.664 23.676 23.688 23.76 ;
    END
  END i[267]
  PIN i[268]
    DIRECTION INPUT ;
    USE SIGNAL ;
    PORT
      LAYER M5 ;
        RECT  23.76 23.676 23.784 23.76 ;
    END
  END i[268]
  PIN i[269]
    DIRECTION INPUT ;
    USE SIGNAL ;
    PORT
      LAYER M5 ;
        RECT  23.856 23.676 23.88 23.76 ;
    END
  END i[269]
  PIN i[26]
    DIRECTION INPUT ;
    USE SIGNAL ;
    PORT
      LAYER M5 ;
        RECT  38.16 23.676 38.184 23.76 ;
    END
  END i[26]
  PIN i[270]
    DIRECTION INPUT ;
    USE SIGNAL ;
    PORT
      LAYER M5 ;
        RECT  23.952 23.676 23.976 23.76 ;
    END
  END i[270]
  PIN i[271]
    DIRECTION INPUT ;
    USE SIGNAL ;
    PORT
      LAYER M5 ;
        RECT  24.048 23.676 24.072 23.76 ;
    END
  END i[271]
  PIN i[272]
    DIRECTION INPUT ;
    USE SIGNAL ;
    PORT
      LAYER M5 ;
        RECT  24.144 23.676 24.168 23.76 ;
    END
  END i[272]
  PIN i[273]
    DIRECTION INPUT ;
    USE SIGNAL ;
    PORT
      LAYER M5 ;
        RECT  24.24 23.676 24.264 23.76 ;
    END
  END i[273]
  PIN i[274]
    DIRECTION INPUT ;
    USE SIGNAL ;
    PORT
      LAYER M5 ;
        RECT  24.336 23.676 24.36 23.76 ;
    END
  END i[274]
  PIN i[275]
    DIRECTION INPUT ;
    USE SIGNAL ;
    PORT
      LAYER M5 ;
        RECT  24.432 23.676 24.456 23.76 ;
    END
  END i[275]
  PIN i[276]
    DIRECTION INPUT ;
    USE SIGNAL ;
    PORT
      LAYER M5 ;
        RECT  24.528 23.676 24.552 23.76 ;
    END
  END i[276]
  PIN i[277]
    DIRECTION INPUT ;
    USE SIGNAL ;
    PORT
      LAYER M5 ;
        RECT  24.624 23.676 24.648 23.76 ;
    END
  END i[277]
  PIN i[278]
    DIRECTION INPUT ;
    USE SIGNAL ;
    PORT
      LAYER M5 ;
        RECT  24.72 23.676 24.744 23.76 ;
    END
  END i[278]
  PIN i[279]
    DIRECTION INPUT ;
    USE SIGNAL ;
    PORT
      LAYER M5 ;
        RECT  24.816 23.676 24.84 23.76 ;
    END
  END i[279]
  PIN i[27]
    DIRECTION INPUT ;
    USE SIGNAL ;
    PORT
      LAYER M5 ;
        RECT  38.256 23.676 38.28 23.76 ;
    END
  END i[27]
  PIN i[280]
    DIRECTION INPUT ;
    USE SIGNAL ;
    PORT
      LAYER M5 ;
        RECT  24.912 23.676 24.936 23.76 ;
    END
  END i[280]
  PIN i[281]
    DIRECTION INPUT ;
    USE SIGNAL ;
    PORT
      LAYER M5 ;
        RECT  25.008 23.676 25.032 23.76 ;
    END
  END i[281]
  PIN i[282]
    DIRECTION INPUT ;
    USE SIGNAL ;
    PORT
      LAYER M5 ;
        RECT  25.104 23.676 25.128 23.76 ;
    END
  END i[282]
  PIN i[283]
    DIRECTION INPUT ;
    USE SIGNAL ;
    PORT
      LAYER M5 ;
        RECT  25.2 23.676 25.224 23.76 ;
    END
  END i[283]
  PIN i[284]
    DIRECTION INPUT ;
    USE SIGNAL ;
    PORT
      LAYER M5 ;
        RECT  25.296 23.676 25.32 23.76 ;
    END
  END i[284]
  PIN i[285]
    DIRECTION INPUT ;
    USE SIGNAL ;
    PORT
      LAYER M5 ;
        RECT  25.392 23.676 25.416 23.76 ;
    END
  END i[285]
  PIN i[286]
    DIRECTION INPUT ;
    USE SIGNAL ;
    PORT
      LAYER M5 ;
        RECT  25.488 23.676 25.512 23.76 ;
    END
  END i[286]
  PIN i[287]
    DIRECTION INPUT ;
    USE SIGNAL ;
    PORT
      LAYER M5 ;
        RECT  25.584 23.676 25.608 23.76 ;
    END
  END i[287]
  PIN i[288]
    DIRECTION INPUT ;
    USE SIGNAL ;
    PORT
      LAYER M5 ;
        RECT  7.248 23.676 7.272 23.76 ;
    END
  END i[288]
  PIN i[289]
    DIRECTION INPUT ;
    USE SIGNAL ;
    PORT
      LAYER M5 ;
        RECT  7.344 23.676 7.368 23.76 ;
    END
  END i[289]
  PIN i[28]
    DIRECTION INPUT ;
    USE SIGNAL ;
    PORT
      LAYER M5 ;
        RECT  38.352 23.676 38.376 23.76 ;
    END
  END i[28]
  PIN i[290]
    DIRECTION INPUT ;
    USE SIGNAL ;
    PORT
      LAYER M5 ;
        RECT  7.44 23.676 7.464 23.76 ;
    END
  END i[290]
  PIN i[291]
    DIRECTION INPUT ;
    USE SIGNAL ;
    PORT
      LAYER M5 ;
        RECT  7.536 23.676 7.56 23.76 ;
    END
  END i[291]
  PIN i[292]
    DIRECTION INPUT ;
    USE SIGNAL ;
    PORT
      LAYER M5 ;
        RECT  7.632 23.676 7.656 23.76 ;
    END
  END i[292]
  PIN i[293]
    DIRECTION INPUT ;
    USE SIGNAL ;
    PORT
      LAYER M5 ;
        RECT  7.728 23.676 7.752 23.76 ;
    END
  END i[293]
  PIN i[294]
    DIRECTION INPUT ;
    USE SIGNAL ;
    PORT
      LAYER M5 ;
        RECT  7.824 23.676 7.848 23.76 ;
    END
  END i[294]
  PIN i[295]
    DIRECTION INPUT ;
    USE SIGNAL ;
    PORT
      LAYER M5 ;
        RECT  7.92 23.676 7.944 23.76 ;
    END
  END i[295]
  PIN i[296]
    DIRECTION INPUT ;
    USE SIGNAL ;
    PORT
      LAYER M5 ;
        RECT  8.016 23.676 8.04 23.76 ;
    END
  END i[296]
  PIN i[297]
    DIRECTION INPUT ;
    USE SIGNAL ;
    PORT
      LAYER M5 ;
        RECT  8.112 23.676 8.136 23.76 ;
    END
  END i[297]
  PIN i[298]
    DIRECTION INPUT ;
    USE SIGNAL ;
    PORT
      LAYER M5 ;
        RECT  8.208 23.676 8.232 23.76 ;
    END
  END i[298]
  PIN i[299]
    DIRECTION INPUT ;
    USE SIGNAL ;
    PORT
      LAYER M5 ;
        RECT  8.304 23.676 8.328 23.76 ;
    END
  END i[299]
  PIN i[29]
    DIRECTION INPUT ;
    USE SIGNAL ;
    PORT
      LAYER M5 ;
        RECT  38.448 23.676 38.472 23.76 ;
    END
  END i[29]
  PIN i[2]
    DIRECTION INPUT ;
    USE SIGNAL ;
    PORT
      LAYER M5 ;
        RECT  35.856 23.676 35.88 23.76 ;
    END
  END i[2]
  PIN i[300]
    DIRECTION INPUT ;
    USE SIGNAL ;
    PORT
      LAYER M5 ;
        RECT  8.4 23.676 8.424 23.76 ;
    END
  END i[300]
  PIN i[301]
    DIRECTION INPUT ;
    USE SIGNAL ;
    PORT
      LAYER M5 ;
        RECT  8.496 23.676 8.52 23.76 ;
    END
  END i[301]
  PIN i[302]
    DIRECTION INPUT ;
    USE SIGNAL ;
    PORT
      LAYER M5 ;
        RECT  8.592 23.676 8.616 23.76 ;
    END
  END i[302]
  PIN i[303]
    DIRECTION INPUT ;
    USE SIGNAL ;
    PORT
      LAYER M5 ;
        RECT  8.688 23.676 8.712 23.76 ;
    END
  END i[303]
  PIN i[304]
    DIRECTION INPUT ;
    USE SIGNAL ;
    PORT
      LAYER M5 ;
        RECT  8.784 23.676 8.808 23.76 ;
    END
  END i[304]
  PIN i[305]
    DIRECTION INPUT ;
    USE SIGNAL ;
    PORT
      LAYER M5 ;
        RECT  8.88 23.676 8.904 23.76 ;
    END
  END i[305]
  PIN i[306]
    DIRECTION INPUT ;
    USE SIGNAL ;
    PORT
      LAYER M5 ;
        RECT  8.976 23.676 9 23.76 ;
    END
  END i[306]
  PIN i[307]
    DIRECTION INPUT ;
    USE SIGNAL ;
    PORT
      LAYER M5 ;
        RECT  9.072 23.676 9.096 23.76 ;
    END
  END i[307]
  PIN i[308]
    DIRECTION INPUT ;
    USE SIGNAL ;
    PORT
      LAYER M5 ;
        RECT  9.168 23.676 9.192 23.76 ;
    END
  END i[308]
  PIN i[309]
    DIRECTION INPUT ;
    USE SIGNAL ;
    PORT
      LAYER M5 ;
        RECT  9.264 23.676 9.288 23.76 ;
    END
  END i[309]
  PIN i[30]
    DIRECTION INPUT ;
    USE SIGNAL ;
    PORT
      LAYER M5 ;
        RECT  38.544 23.676 38.568 23.76 ;
    END
  END i[30]
  PIN i[310]
    DIRECTION INPUT ;
    USE SIGNAL ;
    PORT
      LAYER M5 ;
        RECT  9.36 23.676 9.384 23.76 ;
    END
  END i[310]
  PIN i[311]
    DIRECTION INPUT ;
    USE SIGNAL ;
    PORT
      LAYER M5 ;
        RECT  9.456 23.676 9.48 23.76 ;
    END
  END i[311]
  PIN i[312]
    DIRECTION INPUT ;
    USE SIGNAL ;
    PORT
      LAYER M5 ;
        RECT  9.552 23.676 9.576 23.76 ;
    END
  END i[312]
  PIN i[313]
    DIRECTION INPUT ;
    USE SIGNAL ;
    PORT
      LAYER M5 ;
        RECT  9.648 23.676 9.672 23.76 ;
    END
  END i[313]
  PIN i[314]
    DIRECTION INPUT ;
    USE SIGNAL ;
    PORT
      LAYER M5 ;
        RECT  9.744 23.676 9.768 23.76 ;
    END
  END i[314]
  PIN i[315]
    DIRECTION INPUT ;
    USE SIGNAL ;
    PORT
      LAYER M5 ;
        RECT  9.84 23.676 9.864 23.76 ;
    END
  END i[315]
  PIN i[316]
    DIRECTION INPUT ;
    USE SIGNAL ;
    PORT
      LAYER M5 ;
        RECT  9.936 23.676 9.96 23.76 ;
    END
  END i[316]
  PIN i[317]
    DIRECTION INPUT ;
    USE SIGNAL ;
    PORT
      LAYER M5 ;
        RECT  10.032 23.676 10.056 23.76 ;
    END
  END i[317]
  PIN i[318]
    DIRECTION INPUT ;
    USE SIGNAL ;
    PORT
      LAYER M5 ;
        RECT  10.128 23.676 10.152 23.76 ;
    END
  END i[318]
  PIN i[319]
    DIRECTION INPUT ;
    USE SIGNAL ;
    PORT
      LAYER M5 ;
        RECT  10.224 23.676 10.248 23.76 ;
    END
  END i[319]
  PIN i[31]
    DIRECTION INPUT ;
    USE SIGNAL ;
    PORT
      LAYER M5 ;
        RECT  38.64 23.676 38.664 23.76 ;
    END
  END i[31]
  PIN i[320]
    DIRECTION INPUT ;
    USE SIGNAL ;
    PORT
      LAYER M5 ;
        RECT  10.32 23.676 10.344 23.76 ;
    END
  END i[320]
  PIN i[321]
    DIRECTION INPUT ;
    USE SIGNAL ;
    PORT
      LAYER M5 ;
        RECT  10.416 23.676 10.44 23.76 ;
    END
  END i[321]
  PIN i[322]
    DIRECTION INPUT ;
    USE SIGNAL ;
    PORT
      LAYER M5 ;
        RECT  10.512 23.676 10.536 23.76 ;
    END
  END i[322]
  PIN i[323]
    DIRECTION INPUT ;
    USE SIGNAL ;
    PORT
      LAYER M5 ;
        RECT  10.608 23.676 10.632 23.76 ;
    END
  END i[323]
  PIN i[324]
    DIRECTION INPUT ;
    USE SIGNAL ;
    PORT
      LAYER M5 ;
        RECT  10.704 23.676 10.728 23.76 ;
    END
  END i[324]
  PIN i[325]
    DIRECTION INPUT ;
    USE SIGNAL ;
    PORT
      LAYER M5 ;
        RECT  10.8 23.676 10.824 23.76 ;
    END
  END i[325]
  PIN i[326]
    DIRECTION INPUT ;
    USE SIGNAL ;
    PORT
      LAYER M5 ;
        RECT  10.896 23.676 10.92 23.76 ;
    END
  END i[326]
  PIN i[327]
    DIRECTION INPUT ;
    USE SIGNAL ;
    PORT
      LAYER M5 ;
        RECT  10.992 23.676 11.016 23.76 ;
    END
  END i[327]
  PIN i[328]
    DIRECTION INPUT ;
    USE SIGNAL ;
    PORT
      LAYER M5 ;
        RECT  11.088 23.676 11.112 23.76 ;
    END
  END i[328]
  PIN i[329]
    DIRECTION INPUT ;
    USE SIGNAL ;
    PORT
      LAYER M5 ;
        RECT  11.184 23.676 11.208 23.76 ;
    END
  END i[329]
  PIN i[32]
    DIRECTION INPUT ;
    USE SIGNAL ;
    PORT
      LAYER M5 ;
        RECT  32.592 23.676 32.616 23.76 ;
    END
  END i[32]
  PIN i[330]
    DIRECTION INPUT ;
    USE SIGNAL ;
    PORT
      LAYER M5 ;
        RECT  11.28 23.676 11.304 23.76 ;
    END
  END i[330]
  PIN i[331]
    DIRECTION INPUT ;
    USE SIGNAL ;
    PORT
      LAYER M5 ;
        RECT  11.376 23.676 11.4 23.76 ;
    END
  END i[331]
  PIN i[332]
    DIRECTION INPUT ;
    USE SIGNAL ;
    PORT
      LAYER M5 ;
        RECT  11.472 23.676 11.496 23.76 ;
    END
  END i[332]
  PIN i[333]
    DIRECTION INPUT ;
    USE SIGNAL ;
    PORT
      LAYER M5 ;
        RECT  11.568 23.676 11.592 23.76 ;
    END
  END i[333]
  PIN i[334]
    DIRECTION INPUT ;
    USE SIGNAL ;
    PORT
      LAYER M5 ;
        RECT  11.664 23.676 11.688 23.76 ;
    END
  END i[334]
  PIN i[335]
    DIRECTION INPUT ;
    USE SIGNAL ;
    PORT
      LAYER M5 ;
        RECT  11.76 23.676 11.784 23.76 ;
    END
  END i[335]
  PIN i[336]
    DIRECTION INPUT ;
    USE SIGNAL ;
    PORT
      LAYER M5 ;
        RECT  11.856 23.676 11.88 23.76 ;
    END
  END i[336]
  PIN i[337]
    DIRECTION INPUT ;
    USE SIGNAL ;
    PORT
      LAYER M5 ;
        RECT  11.952 23.676 11.976 23.76 ;
    END
  END i[337]
  PIN i[338]
    DIRECTION INPUT ;
    USE SIGNAL ;
    PORT
      LAYER M5 ;
        RECT  12.048 23.676 12.072 23.76 ;
    END
  END i[338]
  PIN i[339]
    DIRECTION INPUT ;
    USE SIGNAL ;
    PORT
      LAYER M5 ;
        RECT  12.144 23.676 12.168 23.76 ;
    END
  END i[339]
  PIN i[33]
    DIRECTION INPUT ;
    USE SIGNAL ;
    PORT
      LAYER M5 ;
        RECT  32.688 23.676 32.712 23.76 ;
    END
  END i[33]
  PIN i[340]
    DIRECTION INPUT ;
    USE SIGNAL ;
    PORT
      LAYER M5 ;
        RECT  12.24 23.676 12.264 23.76 ;
    END
  END i[340]
  PIN i[341]
    DIRECTION INPUT ;
    USE SIGNAL ;
    PORT
      LAYER M5 ;
        RECT  12.336 23.676 12.36 23.76 ;
    END
  END i[341]
  PIN i[342]
    DIRECTION INPUT ;
    USE SIGNAL ;
    PORT
      LAYER M5 ;
        RECT  12.432 23.676 12.456 23.76 ;
    END
  END i[342]
  PIN i[343]
    DIRECTION INPUT ;
    USE SIGNAL ;
    PORT
      LAYER M5 ;
        RECT  12.528 23.676 12.552 23.76 ;
    END
  END i[343]
  PIN i[344]
    DIRECTION INPUT ;
    USE SIGNAL ;
    PORT
      LAYER M5 ;
        RECT  12.624 23.676 12.648 23.76 ;
    END
  END i[344]
  PIN i[345]
    DIRECTION INPUT ;
    USE SIGNAL ;
    PORT
      LAYER M5 ;
        RECT  12.72 23.676 12.744 23.76 ;
    END
  END i[345]
  PIN i[346]
    DIRECTION INPUT ;
    USE SIGNAL ;
    PORT
      LAYER M5 ;
        RECT  12.816 23.676 12.84 23.76 ;
    END
  END i[346]
  PIN i[347]
    DIRECTION INPUT ;
    USE SIGNAL ;
    PORT
      LAYER M5 ;
        RECT  12.912 23.676 12.936 23.76 ;
    END
  END i[347]
  PIN i[348]
    DIRECTION INPUT ;
    USE SIGNAL ;
    PORT
      LAYER M5 ;
        RECT  13.008 23.676 13.032 23.76 ;
    END
  END i[348]
  PIN i[349]
    DIRECTION INPUT ;
    USE SIGNAL ;
    PORT
      LAYER M5 ;
        RECT  13.104 23.676 13.128 23.76 ;
    END
  END i[349]
  PIN i[34]
    DIRECTION INPUT ;
    USE SIGNAL ;
    PORT
      LAYER M5 ;
        RECT  32.784 23.676 32.808 23.76 ;
    END
  END i[34]
  PIN i[350]
    DIRECTION INPUT ;
    USE SIGNAL ;
    PORT
      LAYER M5 ;
        RECT  13.2 23.676 13.224 23.76 ;
    END
  END i[350]
  PIN i[351]
    DIRECTION INPUT ;
    USE SIGNAL ;
    PORT
      LAYER M5 ;
        RECT  13.296 23.676 13.32 23.76 ;
    END
  END i[351]
  PIN i[352]
    DIRECTION INPUT ;
    USE SIGNAL ;
    PORT
      LAYER M5 ;
        RECT  19.536 23.676 19.56 23.76 ;
    END
  END i[352]
  PIN i[353]
    DIRECTION INPUT ;
    USE SIGNAL ;
    PORT
      LAYER M5 ;
        RECT  19.632 23.676 19.656 23.76 ;
    END
  END i[353]
  PIN i[354]
    DIRECTION INPUT ;
    USE SIGNAL ;
    PORT
      LAYER M5 ;
        RECT  19.728 23.676 19.752 23.76 ;
    END
  END i[354]
  PIN i[355]
    DIRECTION INPUT ;
    USE SIGNAL ;
    PORT
      LAYER M5 ;
        RECT  19.824 23.676 19.848 23.76 ;
    END
  END i[355]
  PIN i[356]
    DIRECTION INPUT ;
    USE SIGNAL ;
    PORT
      LAYER M5 ;
        RECT  19.92 23.676 19.944 23.76 ;
    END
  END i[356]
  PIN i[357]
    DIRECTION INPUT ;
    USE SIGNAL ;
    PORT
      LAYER M5 ;
        RECT  20.016 23.676 20.04 23.76 ;
    END
  END i[357]
  PIN i[358]
    DIRECTION INPUT ;
    USE SIGNAL ;
    PORT
      LAYER M5 ;
        RECT  20.112 23.676 20.136 23.76 ;
    END
  END i[358]
  PIN i[359]
    DIRECTION INPUT ;
    USE SIGNAL ;
    PORT
      LAYER M5 ;
        RECT  20.208 23.676 20.232 23.76 ;
    END
  END i[359]
  PIN i[35]
    DIRECTION INPUT ;
    USE SIGNAL ;
    PORT
      LAYER M5 ;
        RECT  32.88 23.676 32.904 23.76 ;
    END
  END i[35]
  PIN i[360]
    DIRECTION INPUT ;
    USE SIGNAL ;
    PORT
      LAYER M5 ;
        RECT  20.304 23.676 20.328 23.76 ;
    END
  END i[360]
  PIN i[361]
    DIRECTION INPUT ;
    USE SIGNAL ;
    PORT
      LAYER M5 ;
        RECT  20.4 23.676 20.424 23.76 ;
    END
  END i[361]
  PIN i[362]
    DIRECTION INPUT ;
    USE SIGNAL ;
    PORT
      LAYER M5 ;
        RECT  20.496 23.676 20.52 23.76 ;
    END
  END i[362]
  PIN i[363]
    DIRECTION INPUT ;
    USE SIGNAL ;
    PORT
      LAYER M5 ;
        RECT  20.592 23.676 20.616 23.76 ;
    END
  END i[363]
  PIN i[364]
    DIRECTION INPUT ;
    USE SIGNAL ;
    PORT
      LAYER M5 ;
        RECT  20.688 23.676 20.712 23.76 ;
    END
  END i[364]
  PIN i[365]
    DIRECTION INPUT ;
    USE SIGNAL ;
    PORT
      LAYER M5 ;
        RECT  20.784 23.676 20.808 23.76 ;
    END
  END i[365]
  PIN i[366]
    DIRECTION INPUT ;
    USE SIGNAL ;
    PORT
      LAYER M5 ;
        RECT  20.88 23.676 20.904 23.76 ;
    END
  END i[366]
  PIN i[367]
    DIRECTION INPUT ;
    USE SIGNAL ;
    PORT
      LAYER M5 ;
        RECT  20.976 23.676 21 23.76 ;
    END
  END i[367]
  PIN i[368]
    DIRECTION INPUT ;
    USE SIGNAL ;
    PORT
      LAYER M5 ;
        RECT  21.072 23.676 21.096 23.76 ;
    END
  END i[368]
  PIN i[369]
    DIRECTION INPUT ;
    USE SIGNAL ;
    PORT
      LAYER M5 ;
        RECT  21.168 23.676 21.192 23.76 ;
    END
  END i[369]
  PIN i[36]
    DIRECTION INPUT ;
    USE SIGNAL ;
    PORT
      LAYER M5 ;
        RECT  32.976 23.676 33 23.76 ;
    END
  END i[36]
  PIN i[370]
    DIRECTION INPUT ;
    USE SIGNAL ;
    PORT
      LAYER M5 ;
        RECT  21.264 23.676 21.288 23.76 ;
    END
  END i[370]
  PIN i[371]
    DIRECTION INPUT ;
    USE SIGNAL ;
    PORT
      LAYER M5 ;
        RECT  21.36 23.676 21.384 23.76 ;
    END
  END i[371]
  PIN i[372]
    DIRECTION INPUT ;
    USE SIGNAL ;
    PORT
      LAYER M5 ;
        RECT  21.456 23.676 21.48 23.76 ;
    END
  END i[372]
  PIN i[373]
    DIRECTION INPUT ;
    USE SIGNAL ;
    PORT
      LAYER M5 ;
        RECT  21.552 23.676 21.576 23.76 ;
    END
  END i[373]
  PIN i[374]
    DIRECTION INPUT ;
    USE SIGNAL ;
    PORT
      LAYER M5 ;
        RECT  21.648 23.676 21.672 23.76 ;
    END
  END i[374]
  PIN i[375]
    DIRECTION INPUT ;
    USE SIGNAL ;
    PORT
      LAYER M5 ;
        RECT  21.744 23.676 21.768 23.76 ;
    END
  END i[375]
  PIN i[376]
    DIRECTION INPUT ;
    USE SIGNAL ;
    PORT
      LAYER M5 ;
        RECT  21.84 23.676 21.864 23.76 ;
    END
  END i[376]
  PIN i[377]
    DIRECTION INPUT ;
    USE SIGNAL ;
    PORT
      LAYER M5 ;
        RECT  21.936 23.676 21.96 23.76 ;
    END
  END i[377]
  PIN i[378]
    DIRECTION INPUT ;
    USE SIGNAL ;
    PORT
      LAYER M5 ;
        RECT  22.032 23.676 22.056 23.76 ;
    END
  END i[378]
  PIN i[379]
    DIRECTION INPUT ;
    USE SIGNAL ;
    PORT
      LAYER M5 ;
        RECT  22.128 23.676 22.152 23.76 ;
    END
  END i[379]
  PIN i[37]
    DIRECTION INPUT ;
    USE SIGNAL ;
    PORT
      LAYER M5 ;
        RECT  33.072 23.676 33.096 23.76 ;
    END
  END i[37]
  PIN i[380]
    DIRECTION INPUT ;
    USE SIGNAL ;
    PORT
      LAYER M5 ;
        RECT  22.224 23.676 22.248 23.76 ;
    END
  END i[380]
  PIN i[381]
    DIRECTION INPUT ;
    USE SIGNAL ;
    PORT
      LAYER M5 ;
        RECT  22.32 23.676 22.344 23.76 ;
    END
  END i[381]
  PIN i[382]
    DIRECTION INPUT ;
    USE SIGNAL ;
    PORT
      LAYER M5 ;
        RECT  22.416 23.676 22.44 23.76 ;
    END
  END i[382]
  PIN i[383]
    DIRECTION INPUT ;
    USE SIGNAL ;
    PORT
      LAYER M5 ;
        RECT  22.512 23.676 22.536 23.76 ;
    END
  END i[383]
  PIN i[384]
    DIRECTION INPUT ;
    USE SIGNAL ;
    PORT
      LAYER M5 ;
        RECT  13.392 23.676 13.416 23.76 ;
    END
  END i[384]
  PIN i[385]
    DIRECTION INPUT ;
    USE SIGNAL ;
    PORT
      LAYER M5 ;
        RECT  13.488 23.676 13.512 23.76 ;
    END
  END i[385]
  PIN i[386]
    DIRECTION INPUT ;
    USE SIGNAL ;
    PORT
      LAYER M5 ;
        RECT  13.584 23.676 13.608 23.76 ;
    END
  END i[386]
  PIN i[387]
    DIRECTION INPUT ;
    USE SIGNAL ;
    PORT
      LAYER M5 ;
        RECT  13.68 23.676 13.704 23.76 ;
    END
  END i[387]
  PIN i[388]
    DIRECTION INPUT ;
    USE SIGNAL ;
    PORT
      LAYER M5 ;
        RECT  13.776 23.676 13.8 23.76 ;
    END
  END i[388]
  PIN i[389]
    DIRECTION INPUT ;
    USE SIGNAL ;
    PORT
      LAYER M5 ;
        RECT  13.872 23.676 13.896 23.76 ;
    END
  END i[389]
  PIN i[38]
    DIRECTION INPUT ;
    USE SIGNAL ;
    PORT
      LAYER M5 ;
        RECT  33.168 23.676 33.192 23.76 ;
    END
  END i[38]
  PIN i[390]
    DIRECTION INPUT ;
    USE SIGNAL ;
    PORT
      LAYER M5 ;
        RECT  13.968 23.676 13.992 23.76 ;
    END
  END i[390]
  PIN i[391]
    DIRECTION INPUT ;
    USE SIGNAL ;
    PORT
      LAYER M5 ;
        RECT  14.064 23.676 14.088 23.76 ;
    END
  END i[391]
  PIN i[392]
    DIRECTION INPUT ;
    USE SIGNAL ;
    PORT
      LAYER M5 ;
        RECT  14.16 23.676 14.184 23.76 ;
    END
  END i[392]
  PIN i[393]
    DIRECTION INPUT ;
    USE SIGNAL ;
    PORT
      LAYER M5 ;
        RECT  14.256 23.676 14.28 23.76 ;
    END
  END i[393]
  PIN i[394]
    DIRECTION INPUT ;
    USE SIGNAL ;
    PORT
      LAYER M5 ;
        RECT  14.352 23.676 14.376 23.76 ;
    END
  END i[394]
  PIN i[395]
    DIRECTION INPUT ;
    USE SIGNAL ;
    PORT
      LAYER M5 ;
        RECT  14.448 23.676 14.472 23.76 ;
    END
  END i[395]
  PIN i[396]
    DIRECTION INPUT ;
    USE SIGNAL ;
    PORT
      LAYER M5 ;
        RECT  14.544 23.676 14.568 23.76 ;
    END
  END i[396]
  PIN i[397]
    DIRECTION INPUT ;
    USE SIGNAL ;
    PORT
      LAYER M5 ;
        RECT  14.64 23.676 14.664 23.76 ;
    END
  END i[397]
  PIN i[398]
    DIRECTION INPUT ;
    USE SIGNAL ;
    PORT
      LAYER M5 ;
        RECT  14.736 23.676 14.76 23.76 ;
    END
  END i[398]
  PIN i[399]
    DIRECTION INPUT ;
    USE SIGNAL ;
    PORT
      LAYER M5 ;
        RECT  14.832 23.676 14.856 23.76 ;
    END
  END i[399]
  PIN i[39]
    DIRECTION INPUT ;
    USE SIGNAL ;
    PORT
      LAYER M5 ;
        RECT  33.264 23.676 33.288 23.76 ;
    END
  END i[39]
  PIN i[3]
    DIRECTION INPUT ;
    USE SIGNAL ;
    PORT
      LAYER M5 ;
        RECT  35.952 23.676 35.976 23.76 ;
    END
  END i[3]
  PIN i[400]
    DIRECTION INPUT ;
    USE SIGNAL ;
    PORT
      LAYER M5 ;
        RECT  14.928 23.676 14.952 23.76 ;
    END
  END i[400]
  PIN i[401]
    DIRECTION INPUT ;
    USE SIGNAL ;
    PORT
      LAYER M5 ;
        RECT  15.024 23.676 15.048 23.76 ;
    END
  END i[401]
  PIN i[402]
    DIRECTION INPUT ;
    USE SIGNAL ;
    PORT
      LAYER M5 ;
        RECT  15.12 23.676 15.144 23.76 ;
    END
  END i[402]
  PIN i[403]
    DIRECTION INPUT ;
    USE SIGNAL ;
    PORT
      LAYER M5 ;
        RECT  15.216 23.676 15.24 23.76 ;
    END
  END i[403]
  PIN i[404]
    DIRECTION INPUT ;
    USE SIGNAL ;
    PORT
      LAYER M5 ;
        RECT  15.312 23.676 15.336 23.76 ;
    END
  END i[404]
  PIN i[405]
    DIRECTION INPUT ;
    USE SIGNAL ;
    PORT
      LAYER M5 ;
        RECT  15.408 23.676 15.432 23.76 ;
    END
  END i[405]
  PIN i[406]
    DIRECTION INPUT ;
    USE SIGNAL ;
    PORT
      LAYER M5 ;
        RECT  15.504 23.676 15.528 23.76 ;
    END
  END i[406]
  PIN i[407]
    DIRECTION INPUT ;
    USE SIGNAL ;
    PORT
      LAYER M5 ;
        RECT  15.6 23.676 15.624 23.76 ;
    END
  END i[407]
  PIN i[408]
    DIRECTION INPUT ;
    USE SIGNAL ;
    PORT
      LAYER M5 ;
        RECT  15.696 23.676 15.72 23.76 ;
    END
  END i[408]
  PIN i[409]
    DIRECTION INPUT ;
    USE SIGNAL ;
    PORT
      LAYER M5 ;
        RECT  15.792 23.676 15.816 23.76 ;
    END
  END i[409]
  PIN i[40]
    DIRECTION INPUT ;
    USE SIGNAL ;
    PORT
      LAYER M5 ;
        RECT  33.36 23.676 33.384 23.76 ;
    END
  END i[40]
  PIN i[410]
    DIRECTION INPUT ;
    USE SIGNAL ;
    PORT
      LAYER M5 ;
        RECT  15.888 23.676 15.912 23.76 ;
    END
  END i[410]
  PIN i[411]
    DIRECTION INPUT ;
    USE SIGNAL ;
    PORT
      LAYER M5 ;
        RECT  15.984 23.676 16.008 23.76 ;
    END
  END i[411]
  PIN i[412]
    DIRECTION INPUT ;
    USE SIGNAL ;
    PORT
      LAYER M5 ;
        RECT  16.08 23.676 16.104 23.76 ;
    END
  END i[412]
  PIN i[413]
    DIRECTION INPUT ;
    USE SIGNAL ;
    PORT
      LAYER M5 ;
        RECT  16.176 23.676 16.2 23.76 ;
    END
  END i[413]
  PIN i[414]
    DIRECTION INPUT ;
    USE SIGNAL ;
    PORT
      LAYER M5 ;
        RECT  16.272 23.676 16.296 23.76 ;
    END
  END i[414]
  PIN i[415]
    DIRECTION INPUT ;
    USE SIGNAL ;
    PORT
      LAYER M5 ;
        RECT  16.368 23.676 16.392 23.76 ;
    END
  END i[415]
  PIN i[416]
    DIRECTION INPUT ;
    USE SIGNAL ;
    PORT
      LAYER M5 ;
        RECT  16.464 23.676 16.488 23.76 ;
    END
  END i[416]
  PIN i[417]
    DIRECTION INPUT ;
    USE SIGNAL ;
    PORT
      LAYER M5 ;
        RECT  16.56 23.676 16.584 23.76 ;
    END
  END i[417]
  PIN i[418]
    DIRECTION INPUT ;
    USE SIGNAL ;
    PORT
      LAYER M5 ;
        RECT  16.656 23.676 16.68 23.76 ;
    END
  END i[418]
  PIN i[419]
    DIRECTION INPUT ;
    USE SIGNAL ;
    PORT
      LAYER M5 ;
        RECT  16.752 23.676 16.776 23.76 ;
    END
  END i[419]
  PIN i[41]
    DIRECTION INPUT ;
    USE SIGNAL ;
    PORT
      LAYER M5 ;
        RECT  33.456 23.676 33.48 23.76 ;
    END
  END i[41]
  PIN i[420]
    DIRECTION INPUT ;
    USE SIGNAL ;
    PORT
      LAYER M5 ;
        RECT  16.848 23.676 16.872 23.76 ;
    END
  END i[420]
  PIN i[421]
    DIRECTION INPUT ;
    USE SIGNAL ;
    PORT
      LAYER M5 ;
        RECT  16.944 23.676 16.968 23.76 ;
    END
  END i[421]
  PIN i[422]
    DIRECTION INPUT ;
    USE SIGNAL ;
    PORT
      LAYER M5 ;
        RECT  17.04 23.676 17.064 23.76 ;
    END
  END i[422]
  PIN i[423]
    DIRECTION INPUT ;
    USE SIGNAL ;
    PORT
      LAYER M5 ;
        RECT  17.136 23.676 17.16 23.76 ;
    END
  END i[423]
  PIN i[424]
    DIRECTION INPUT ;
    USE SIGNAL ;
    PORT
      LAYER M5 ;
        RECT  17.232 23.676 17.256 23.76 ;
    END
  END i[424]
  PIN i[425]
    DIRECTION INPUT ;
    USE SIGNAL ;
    PORT
      LAYER M5 ;
        RECT  17.328 23.676 17.352 23.76 ;
    END
  END i[425]
  PIN i[426]
    DIRECTION INPUT ;
    USE SIGNAL ;
    PORT
      LAYER M5 ;
        RECT  17.424 23.676 17.448 23.76 ;
    END
  END i[426]
  PIN i[427]
    DIRECTION INPUT ;
    USE SIGNAL ;
    PORT
      LAYER M5 ;
        RECT  17.52 23.676 17.544 23.76 ;
    END
  END i[427]
  PIN i[428]
    DIRECTION INPUT ;
    USE SIGNAL ;
    PORT
      LAYER M5 ;
        RECT  17.616 23.676 17.64 23.76 ;
    END
  END i[428]
  PIN i[429]
    DIRECTION INPUT ;
    USE SIGNAL ;
    PORT
      LAYER M5 ;
        RECT  17.712 23.676 17.736 23.76 ;
    END
  END i[429]
  PIN i[42]
    DIRECTION INPUT ;
    USE SIGNAL ;
    PORT
      LAYER M5 ;
        RECT  33.552 23.676 33.576 23.76 ;
    END
  END i[42]
  PIN i[430]
    DIRECTION INPUT ;
    USE SIGNAL ;
    PORT
      LAYER M5 ;
        RECT  17.808 23.676 17.832 23.76 ;
    END
  END i[430]
  PIN i[431]
    DIRECTION INPUT ;
    USE SIGNAL ;
    PORT
      LAYER M5 ;
        RECT  17.904 23.676 17.928 23.76 ;
    END
  END i[431]
  PIN i[432]
    DIRECTION INPUT ;
    USE SIGNAL ;
    PORT
      LAYER M5 ;
        RECT  18 23.676 18.024 23.76 ;
    END
  END i[432]
  PIN i[433]
    DIRECTION INPUT ;
    USE SIGNAL ;
    PORT
      LAYER M5 ;
        RECT  18.096 23.676 18.12 23.76 ;
    END
  END i[433]
  PIN i[434]
    DIRECTION INPUT ;
    USE SIGNAL ;
    PORT
      LAYER M5 ;
        RECT  18.192 23.676 18.216 23.76 ;
    END
  END i[434]
  PIN i[435]
    DIRECTION INPUT ;
    USE SIGNAL ;
    PORT
      LAYER M5 ;
        RECT  18.288 23.676 18.312 23.76 ;
    END
  END i[435]
  PIN i[436]
    DIRECTION INPUT ;
    USE SIGNAL ;
    PORT
      LAYER M5 ;
        RECT  18.384 23.676 18.408 23.76 ;
    END
  END i[436]
  PIN i[437]
    DIRECTION INPUT ;
    USE SIGNAL ;
    PORT
      LAYER M5 ;
        RECT  18.48 23.676 18.504 23.76 ;
    END
  END i[437]
  PIN i[438]
    DIRECTION INPUT ;
    USE SIGNAL ;
    PORT
      LAYER M5 ;
        RECT  18.576 23.676 18.6 23.76 ;
    END
  END i[438]
  PIN i[439]
    DIRECTION INPUT ;
    USE SIGNAL ;
    PORT
      LAYER M5 ;
        RECT  18.672 23.676 18.696 23.76 ;
    END
  END i[439]
  PIN i[43]
    DIRECTION INPUT ;
    USE SIGNAL ;
    PORT
      LAYER M5 ;
        RECT  33.648 23.676 33.672 23.76 ;
    END
  END i[43]
  PIN i[440]
    DIRECTION INPUT ;
    USE SIGNAL ;
    PORT
      LAYER M5 ;
        RECT  18.768 23.676 18.792 23.76 ;
    END
  END i[440]
  PIN i[441]
    DIRECTION INPUT ;
    USE SIGNAL ;
    PORT
      LAYER M5 ;
        RECT  18.864 23.676 18.888 23.76 ;
    END
  END i[441]
  PIN i[442]
    DIRECTION INPUT ;
    USE SIGNAL ;
    PORT
      LAYER M5 ;
        RECT  18.96 23.676 18.984 23.76 ;
    END
  END i[442]
  PIN i[443]
    DIRECTION INPUT ;
    USE SIGNAL ;
    PORT
      LAYER M5 ;
        RECT  19.056 23.676 19.08 23.76 ;
    END
  END i[443]
  PIN i[444]
    DIRECTION INPUT ;
    USE SIGNAL ;
    PORT
      LAYER M5 ;
        RECT  19.152 23.676 19.176 23.76 ;
    END
  END i[444]
  PIN i[445]
    DIRECTION INPUT ;
    USE SIGNAL ;
    PORT
      LAYER M5 ;
        RECT  19.248 23.676 19.272 23.76 ;
    END
  END i[445]
  PIN i[446]
    DIRECTION INPUT ;
    USE SIGNAL ;
    PORT
      LAYER M5 ;
        RECT  19.344 23.676 19.368 23.76 ;
    END
  END i[446]
  PIN i[447]
    DIRECTION INPUT ;
    USE SIGNAL ;
    PORT
      LAYER M5 ;
        RECT  19.44 23.676 19.464 23.76 ;
    END
  END i[447]
  PIN i[448]
    DIRECTION INPUT ;
    USE SIGNAL ;
    PORT
      LAYER M5 ;
        RECT  3.408 23.676 3.432 23.76 ;
    END
  END i[448]
  PIN i[449]
    DIRECTION INPUT ;
    USE SIGNAL ;
    PORT
      LAYER M5 ;
        RECT  3.504 23.676 3.528 23.76 ;
    END
  END i[449]
  PIN i[44]
    DIRECTION INPUT ;
    USE SIGNAL ;
    PORT
      LAYER M5 ;
        RECT  33.744 23.676 33.768 23.76 ;
    END
  END i[44]
  PIN i[450]
    DIRECTION INPUT ;
    USE SIGNAL ;
    PORT
      LAYER M5 ;
        RECT  3.6 23.676 3.624 23.76 ;
    END
  END i[450]
  PIN i[451]
    DIRECTION INPUT ;
    USE SIGNAL ;
    PORT
      LAYER M5 ;
        RECT  3.696 23.676 3.72 23.76 ;
    END
  END i[451]
  PIN i[452]
    DIRECTION INPUT ;
    USE SIGNAL ;
    PORT
      LAYER M5 ;
        RECT  3.792 23.676 3.816 23.76 ;
    END
  END i[452]
  PIN i[453]
    DIRECTION INPUT ;
    USE SIGNAL ;
    PORT
      LAYER M5 ;
        RECT  3.888 23.676 3.912 23.76 ;
    END
  END i[453]
  PIN i[454]
    DIRECTION INPUT ;
    USE SIGNAL ;
    PORT
      LAYER M5 ;
        RECT  3.984 23.676 4.008 23.76 ;
    END
  END i[454]
  PIN i[455]
    DIRECTION INPUT ;
    USE SIGNAL ;
    PORT
      LAYER M5 ;
        RECT  4.08 23.676 4.104 23.76 ;
    END
  END i[455]
  PIN i[456]
    DIRECTION INPUT ;
    USE SIGNAL ;
    PORT
      LAYER M5 ;
        RECT  4.176 23.676 4.2 23.76 ;
    END
  END i[456]
  PIN i[457]
    DIRECTION INPUT ;
    USE SIGNAL ;
    PORT
      LAYER M5 ;
        RECT  4.272 23.676 4.296 23.76 ;
    END
  END i[457]
  PIN i[458]
    DIRECTION INPUT ;
    USE SIGNAL ;
    PORT
      LAYER M5 ;
        RECT  4.368 23.676 4.392 23.76 ;
    END
  END i[458]
  PIN i[459]
    DIRECTION INPUT ;
    USE SIGNAL ;
    PORT
      LAYER M5 ;
        RECT  4.464 23.676 4.488 23.76 ;
    END
  END i[459]
  PIN i[45]
    DIRECTION INPUT ;
    USE SIGNAL ;
    PORT
      LAYER M5 ;
        RECT  33.84 23.676 33.864 23.76 ;
    END
  END i[45]
  PIN i[460]
    DIRECTION INPUT ;
    USE SIGNAL ;
    PORT
      LAYER M5 ;
        RECT  4.56 23.676 4.584 23.76 ;
    END
  END i[460]
  PIN i[461]
    DIRECTION INPUT ;
    USE SIGNAL ;
    PORT
      LAYER M5 ;
        RECT  4.656 23.676 4.68 23.76 ;
    END
  END i[461]
  PIN i[462]
    DIRECTION INPUT ;
    USE SIGNAL ;
    PORT
      LAYER M5 ;
        RECT  4.752 23.676 4.776 23.76 ;
    END
  END i[462]
  PIN i[463]
    DIRECTION INPUT ;
    USE SIGNAL ;
    PORT
      LAYER M5 ;
        RECT  4.848 23.676 4.872 23.76 ;
    END
  END i[463]
  PIN i[464]
    DIRECTION INPUT ;
    USE SIGNAL ;
    PORT
      LAYER M5 ;
        RECT  4.944 23.676 4.968 23.76 ;
    END
  END i[464]
  PIN i[465]
    DIRECTION INPUT ;
    USE SIGNAL ;
    PORT
      LAYER M5 ;
        RECT  5.04 23.676 5.064 23.76 ;
    END
  END i[465]
  PIN i[466]
    DIRECTION INPUT ;
    USE SIGNAL ;
    PORT
      LAYER M5 ;
        RECT  5.136 23.676 5.16 23.76 ;
    END
  END i[466]
  PIN i[467]
    DIRECTION INPUT ;
    USE SIGNAL ;
    PORT
      LAYER M5 ;
        RECT  5.232 23.676 5.256 23.76 ;
    END
  END i[467]
  PIN i[468]
    DIRECTION INPUT ;
    USE SIGNAL ;
    PORT
      LAYER M5 ;
        RECT  5.328 23.676 5.352 23.76 ;
    END
  END i[468]
  PIN i[469]
    DIRECTION INPUT ;
    USE SIGNAL ;
    PORT
      LAYER M5 ;
        RECT  5.424 23.676 5.448 23.76 ;
    END
  END i[469]
  PIN i[46]
    DIRECTION INPUT ;
    USE SIGNAL ;
    PORT
      LAYER M5 ;
        RECT  33.936 23.676 33.96 23.76 ;
    END
  END i[46]
  PIN i[470]
    DIRECTION INPUT ;
    USE SIGNAL ;
    PORT
      LAYER M5 ;
        RECT  5.52 23.676 5.544 23.76 ;
    END
  END i[470]
  PIN i[471]
    DIRECTION INPUT ;
    USE SIGNAL ;
    PORT
      LAYER M5 ;
        RECT  5.616 23.676 5.64 23.76 ;
    END
  END i[471]
  PIN i[472]
    DIRECTION INPUT ;
    USE SIGNAL ;
    PORT
      LAYER M5 ;
        RECT  5.712 23.676 5.736 23.76 ;
    END
  END i[472]
  PIN i[473]
    DIRECTION INPUT ;
    USE SIGNAL ;
    PORT
      LAYER M5 ;
        RECT  5.808 23.676 5.832 23.76 ;
    END
  END i[473]
  PIN i[474]
    DIRECTION INPUT ;
    USE SIGNAL ;
    PORT
      LAYER M5 ;
        RECT  5.904 23.676 5.928 23.76 ;
    END
  END i[474]
  PIN i[475]
    DIRECTION INPUT ;
    USE SIGNAL ;
    PORT
      LAYER M5 ;
        RECT  6 23.676 6.024 23.76 ;
    END
  END i[475]
  PIN i[476]
    DIRECTION INPUT ;
    USE SIGNAL ;
    PORT
      LAYER M5 ;
        RECT  6.096 23.676 6.12 23.76 ;
    END
  END i[476]
  PIN i[477]
    DIRECTION INPUT ;
    USE SIGNAL ;
    PORT
      LAYER M5 ;
        RECT  6.192 23.676 6.216 23.76 ;
    END
  END i[477]
  PIN i[478]
    DIRECTION INPUT ;
    USE SIGNAL ;
    PORT
      LAYER M5 ;
        RECT  6.288 23.676 6.312 23.76 ;
    END
  END i[478]
  PIN i[479]
    DIRECTION INPUT ;
    USE SIGNAL ;
    PORT
      LAYER M5 ;
        RECT  6.384 23.676 6.408 23.76 ;
    END
  END i[479]
  PIN i[47]
    DIRECTION INPUT ;
    USE SIGNAL ;
    PORT
      LAYER M5 ;
        RECT  34.032 23.676 34.056 23.76 ;
    END
  END i[47]
  PIN i[480]
    DIRECTION INPUT ;
    USE SIGNAL ;
    PORT
      LAYER M5 ;
        RECT  45.648 23.676 45.672 23.76 ;
    END
  END i[480]
  PIN i[481]
    DIRECTION INPUT ;
    USE SIGNAL ;
    PORT
      LAYER M5 ;
        RECT  45.744 23.676 45.768 23.76 ;
    END
  END i[481]
  PIN i[482]
    DIRECTION INPUT ;
    USE SIGNAL ;
    PORT
      LAYER M5 ;
        RECT  45.84 23.676 45.864 23.76 ;
    END
  END i[482]
  PIN i[483]
    DIRECTION INPUT ;
    USE SIGNAL ;
    PORT
      LAYER M5 ;
        RECT  45.936 23.676 45.96 23.76 ;
    END
  END i[483]
  PIN i[484]
    DIRECTION INPUT ;
    USE SIGNAL ;
    PORT
      LAYER M5 ;
        RECT  46.032 23.676 46.056 23.76 ;
    END
  END i[484]
  PIN i[485]
    DIRECTION INPUT ;
    USE SIGNAL ;
    PORT
      LAYER M5 ;
        RECT  46.128 23.676 46.152 23.76 ;
    END
  END i[485]
  PIN i[486]
    DIRECTION INPUT ;
    USE SIGNAL ;
    PORT
      LAYER M5 ;
        RECT  46.224 23.676 46.248 23.76 ;
    END
  END i[486]
  PIN i[487]
    DIRECTION INPUT ;
    USE SIGNAL ;
    PORT
      LAYER M5 ;
        RECT  46.32 23.676 46.344 23.76 ;
    END
  END i[487]
  PIN i[488]
    DIRECTION INPUT ;
    USE SIGNAL ;
    PORT
      LAYER M5 ;
        RECT  46.416 23.676 46.44 23.76 ;
    END
  END i[488]
  PIN i[489]
    DIRECTION INPUT ;
    USE SIGNAL ;
    PORT
      LAYER M5 ;
        RECT  46.512 23.676 46.536 23.76 ;
    END
  END i[489]
  PIN i[48]
    DIRECTION INPUT ;
    USE SIGNAL ;
    PORT
      LAYER M5 ;
        RECT  34.128 23.676 34.152 23.76 ;
    END
  END i[48]
  PIN i[490]
    DIRECTION INPUT ;
    USE SIGNAL ;
    PORT
      LAYER M5 ;
        RECT  46.608 23.676 46.632 23.76 ;
    END
  END i[490]
  PIN i[491]
    DIRECTION INPUT ;
    USE SIGNAL ;
    PORT
      LAYER M5 ;
        RECT  46.704 23.676 46.728 23.76 ;
    END
  END i[491]
  PIN i[492]
    DIRECTION INPUT ;
    USE SIGNAL ;
    PORT
      LAYER M5 ;
        RECT  46.8 23.676 46.824 23.76 ;
    END
  END i[492]
  PIN i[493]
    DIRECTION INPUT ;
    USE SIGNAL ;
    PORT
      LAYER M5 ;
        RECT  46.896 23.676 46.92 23.76 ;
    END
  END i[493]
  PIN i[494]
    DIRECTION INPUT ;
    USE SIGNAL ;
    PORT
      LAYER M5 ;
        RECT  46.992 23.676 47.016 23.76 ;
    END
  END i[494]
  PIN i[495]
    DIRECTION INPUT ;
    USE SIGNAL ;
    PORT
      LAYER M5 ;
        RECT  47.088 23.676 47.112 23.76 ;
    END
  END i[495]
  PIN i[496]
    DIRECTION INPUT ;
    USE SIGNAL ;
    PORT
      LAYER M5 ;
        RECT  47.184 23.676 47.208 23.76 ;
    END
  END i[496]
  PIN i[497]
    DIRECTION INPUT ;
    USE SIGNAL ;
    PORT
      LAYER M5 ;
        RECT  47.28 23.676 47.304 23.76 ;
    END
  END i[497]
  PIN i[498]
    DIRECTION INPUT ;
    USE SIGNAL ;
    PORT
      LAYER M5 ;
        RECT  47.376 23.676 47.4 23.76 ;
    END
  END i[498]
  PIN i[499]
    DIRECTION INPUT ;
    USE SIGNAL ;
    PORT
      LAYER M5 ;
        RECT  47.472 23.676 47.496 23.76 ;
    END
  END i[499]
  PIN i[49]
    DIRECTION INPUT ;
    USE SIGNAL ;
    PORT
      LAYER M5 ;
        RECT  34.224 23.676 34.248 23.76 ;
    END
  END i[49]
  PIN i[4]
    DIRECTION INPUT ;
    USE SIGNAL ;
    PORT
      LAYER M5 ;
        RECT  36.048 23.676 36.072 23.76 ;
    END
  END i[4]
  PIN i[500]
    DIRECTION INPUT ;
    USE SIGNAL ;
    PORT
      LAYER M5 ;
        RECT  47.568 23.676 47.592 23.76 ;
    END
  END i[500]
  PIN i[501]
    DIRECTION INPUT ;
    USE SIGNAL ;
    PORT
      LAYER M5 ;
        RECT  47.664 23.676 47.688 23.76 ;
    END
  END i[501]
  PIN i[502]
    DIRECTION INPUT ;
    USE SIGNAL ;
    PORT
      LAYER M5 ;
        RECT  47.76 23.676 47.784 23.76 ;
    END
  END i[502]
  PIN i[503]
    DIRECTION INPUT ;
    USE SIGNAL ;
    PORT
      LAYER M5 ;
        RECT  47.856 23.676 47.88 23.76 ;
    END
  END i[503]
  PIN i[504]
    DIRECTION INPUT ;
    USE SIGNAL ;
    PORT
      LAYER M5 ;
        RECT  47.952 23.676 47.976 23.76 ;
    END
  END i[504]
  PIN i[505]
    DIRECTION INPUT ;
    USE SIGNAL ;
    PORT
      LAYER M5 ;
        RECT  48.048 23.676 48.072 23.76 ;
    END
  END i[505]
  PIN i[506]
    DIRECTION INPUT ;
    USE SIGNAL ;
    PORT
      LAYER M5 ;
        RECT  48.144 23.676 48.168 23.76 ;
    END
  END i[506]
  PIN i[507]
    DIRECTION INPUT ;
    USE SIGNAL ;
    PORT
      LAYER M5 ;
        RECT  48.24 23.676 48.264 23.76 ;
    END
  END i[507]
  PIN i[508]
    DIRECTION INPUT ;
    USE SIGNAL ;
    PORT
      LAYER M5 ;
        RECT  48.336 23.676 48.36 23.76 ;
    END
  END i[508]
  PIN i[509]
    DIRECTION INPUT ;
    USE SIGNAL ;
    PORT
      LAYER M5 ;
        RECT  48.432 23.676 48.456 23.76 ;
    END
  END i[509]
  PIN i[50]
    DIRECTION INPUT ;
    USE SIGNAL ;
    PORT
      LAYER M5 ;
        RECT  34.32 23.676 34.344 23.76 ;
    END
  END i[50]
  PIN i[510]
    DIRECTION INPUT ;
    USE SIGNAL ;
    PORT
      LAYER M5 ;
        RECT  48.528 23.676 48.552 23.76 ;
    END
  END i[510]
  PIN i[511]
    DIRECTION INPUT ;
    USE SIGNAL ;
    PORT
      LAYER M5 ;
        RECT  48.624 23.676 48.648 23.76 ;
    END
  END i[511]
  PIN i[512]
    DIRECTION INPUT ;
    USE SIGNAL ;
    PORT
      LAYER M5 ;
        RECT  54.864 23.676 54.888 23.76 ;
    END
  END i[512]
  PIN i[513]
    DIRECTION INPUT ;
    USE SIGNAL ;
    PORT
      LAYER M5 ;
        RECT  54.96 23.676 54.984 23.76 ;
    END
  END i[513]
  PIN i[514]
    DIRECTION INPUT ;
    USE SIGNAL ;
    PORT
      LAYER M5 ;
        RECT  55.056 23.676 55.08 23.76 ;
    END
  END i[514]
  PIN i[515]
    DIRECTION INPUT ;
    USE SIGNAL ;
    PORT
      LAYER M5 ;
        RECT  55.152 23.676 55.176 23.76 ;
    END
  END i[515]
  PIN i[516]
    DIRECTION INPUT ;
    USE SIGNAL ;
    PORT
      LAYER M5 ;
        RECT  55.248 23.676 55.272 23.76 ;
    END
  END i[516]
  PIN i[517]
    DIRECTION INPUT ;
    USE SIGNAL ;
    PORT
      LAYER M5 ;
        RECT  55.344 23.676 55.368 23.76 ;
    END
  END i[517]
  PIN i[518]
    DIRECTION INPUT ;
    USE SIGNAL ;
    PORT
      LAYER M5 ;
        RECT  55.44 23.676 55.464 23.76 ;
    END
  END i[518]
  PIN i[519]
    DIRECTION INPUT ;
    USE SIGNAL ;
    PORT
      LAYER M5 ;
        RECT  55.536 23.676 55.56 23.76 ;
    END
  END i[519]
  PIN i[51]
    DIRECTION INPUT ;
    USE SIGNAL ;
    PORT
      LAYER M5 ;
        RECT  34.416 23.676 34.44 23.76 ;
    END
  END i[51]
  PIN i[520]
    DIRECTION INPUT ;
    USE SIGNAL ;
    PORT
      LAYER M5 ;
        RECT  55.632 23.676 55.656 23.76 ;
    END
  END i[520]
  PIN i[521]
    DIRECTION INPUT ;
    USE SIGNAL ;
    PORT
      LAYER M5 ;
        RECT  55.728 23.676 55.752 23.76 ;
    END
  END i[521]
  PIN i[522]
    DIRECTION INPUT ;
    USE SIGNAL ;
    PORT
      LAYER M5 ;
        RECT  55.824 23.676 55.848 23.76 ;
    END
  END i[522]
  PIN i[523]
    DIRECTION INPUT ;
    USE SIGNAL ;
    PORT
      LAYER M5 ;
        RECT  55.92 23.676 55.944 23.76 ;
    END
  END i[523]
  PIN i[524]
    DIRECTION INPUT ;
    USE SIGNAL ;
    PORT
      LAYER M5 ;
        RECT  56.016 23.676 56.04 23.76 ;
    END
  END i[524]
  PIN i[525]
    DIRECTION INPUT ;
    USE SIGNAL ;
    PORT
      LAYER M5 ;
        RECT  56.112 23.676 56.136 23.76 ;
    END
  END i[525]
  PIN i[526]
    DIRECTION INPUT ;
    USE SIGNAL ;
    PORT
      LAYER M5 ;
        RECT  56.208 23.676 56.232 23.76 ;
    END
  END i[526]
  PIN i[527]
    DIRECTION INPUT ;
    USE SIGNAL ;
    PORT
      LAYER M5 ;
        RECT  56.304 23.676 56.328 23.76 ;
    END
  END i[527]
  PIN i[528]
    DIRECTION INPUT ;
    USE SIGNAL ;
    PORT
      LAYER M5 ;
        RECT  56.4 23.676 56.424 23.76 ;
    END
  END i[528]
  PIN i[529]
    DIRECTION INPUT ;
    USE SIGNAL ;
    PORT
      LAYER M5 ;
        RECT  56.496 23.676 56.52 23.76 ;
    END
  END i[529]
  PIN i[52]
    DIRECTION INPUT ;
    USE SIGNAL ;
    PORT
      LAYER M5 ;
        RECT  34.512 23.676 34.536 23.76 ;
    END
  END i[52]
  PIN i[530]
    DIRECTION INPUT ;
    USE SIGNAL ;
    PORT
      LAYER M5 ;
        RECT  56.592 23.676 56.616 23.76 ;
    END
  END i[530]
  PIN i[531]
    DIRECTION INPUT ;
    USE SIGNAL ;
    PORT
      LAYER M5 ;
        RECT  56.688 23.676 56.712 23.76 ;
    END
  END i[531]
  PIN i[532]
    DIRECTION INPUT ;
    USE SIGNAL ;
    PORT
      LAYER M5 ;
        RECT  56.784 23.676 56.808 23.76 ;
    END
  END i[532]
  PIN i[533]
    DIRECTION INPUT ;
    USE SIGNAL ;
    PORT
      LAYER M5 ;
        RECT  56.88 23.676 56.904 23.76 ;
    END
  END i[533]
  PIN i[534]
    DIRECTION INPUT ;
    USE SIGNAL ;
    PORT
      LAYER M5 ;
        RECT  56.976 23.676 57 23.76 ;
    END
  END i[534]
  PIN i[535]
    DIRECTION INPUT ;
    USE SIGNAL ;
    PORT
      LAYER M5 ;
        RECT  57.072 23.676 57.096 23.76 ;
    END
  END i[535]
  PIN i[536]
    DIRECTION INPUT ;
    USE SIGNAL ;
    PORT
      LAYER M5 ;
        RECT  57.168 23.676 57.192 23.76 ;
    END
  END i[536]
  PIN i[537]
    DIRECTION INPUT ;
    USE SIGNAL ;
    PORT
      LAYER M5 ;
        RECT  57.264 23.676 57.288 23.76 ;
    END
  END i[537]
  PIN i[538]
    DIRECTION INPUT ;
    USE SIGNAL ;
    PORT
      LAYER M5 ;
        RECT  57.36 23.676 57.384 23.76 ;
    END
  END i[538]
  PIN i[539]
    DIRECTION INPUT ;
    USE SIGNAL ;
    PORT
      LAYER M5 ;
        RECT  57.456 23.676 57.48 23.76 ;
    END
  END i[539]
  PIN i[53]
    DIRECTION INPUT ;
    USE SIGNAL ;
    PORT
      LAYER M5 ;
        RECT  34.608 23.676 34.632 23.76 ;
    END
  END i[53]
  PIN i[540]
    DIRECTION INPUT ;
    USE SIGNAL ;
    PORT
      LAYER M5 ;
        RECT  57.552 23.676 57.576 23.76 ;
    END
  END i[540]
  PIN i[541]
    DIRECTION INPUT ;
    USE SIGNAL ;
    PORT
      LAYER M5 ;
        RECT  57.648 23.676 57.672 23.76 ;
    END
  END i[541]
  PIN i[542]
    DIRECTION INPUT ;
    USE SIGNAL ;
    PORT
      LAYER M5 ;
        RECT  57.744 23.676 57.768 23.76 ;
    END
  END i[542]
  PIN i[543]
    DIRECTION INPUT ;
    USE SIGNAL ;
    PORT
      LAYER M5 ;
        RECT  57.84 23.676 57.864 23.76 ;
    END
  END i[543]
  PIN i[544]
    DIRECTION INPUT ;
    USE SIGNAL ;
    PORT
      LAYER M5 ;
        RECT  48.72 23.676 48.744 23.76 ;
    END
  END i[544]
  PIN i[545]
    DIRECTION INPUT ;
    USE SIGNAL ;
    PORT
      LAYER M5 ;
        RECT  48.816 23.676 48.84 23.76 ;
    END
  END i[545]
  PIN i[546]
    DIRECTION INPUT ;
    USE SIGNAL ;
    PORT
      LAYER M5 ;
        RECT  48.912 23.676 48.936 23.76 ;
    END
  END i[546]
  PIN i[547]
    DIRECTION INPUT ;
    USE SIGNAL ;
    PORT
      LAYER M5 ;
        RECT  49.008 23.676 49.032 23.76 ;
    END
  END i[547]
  PIN i[548]
    DIRECTION INPUT ;
    USE SIGNAL ;
    PORT
      LAYER M5 ;
        RECT  49.104 23.676 49.128 23.76 ;
    END
  END i[548]
  PIN i[549]
    DIRECTION INPUT ;
    USE SIGNAL ;
    PORT
      LAYER M5 ;
        RECT  49.2 23.676 49.224 23.76 ;
    END
  END i[549]
  PIN i[54]
    DIRECTION INPUT ;
    USE SIGNAL ;
    PORT
      LAYER M5 ;
        RECT  34.704 23.676 34.728 23.76 ;
    END
  END i[54]
  PIN i[550]
    DIRECTION INPUT ;
    USE SIGNAL ;
    PORT
      LAYER M5 ;
        RECT  49.296 23.676 49.32 23.76 ;
    END
  END i[550]
  PIN i[551]
    DIRECTION INPUT ;
    USE SIGNAL ;
    PORT
      LAYER M5 ;
        RECT  49.392 23.676 49.416 23.76 ;
    END
  END i[551]
  PIN i[552]
    DIRECTION INPUT ;
    USE SIGNAL ;
    PORT
      LAYER M5 ;
        RECT  49.488 23.676 49.512 23.76 ;
    END
  END i[552]
  PIN i[553]
    DIRECTION INPUT ;
    USE SIGNAL ;
    PORT
      LAYER M5 ;
        RECT  49.584 23.676 49.608 23.76 ;
    END
  END i[553]
  PIN i[554]
    DIRECTION INPUT ;
    USE SIGNAL ;
    PORT
      LAYER M5 ;
        RECT  49.68 23.676 49.704 23.76 ;
    END
  END i[554]
  PIN i[555]
    DIRECTION INPUT ;
    USE SIGNAL ;
    PORT
      LAYER M5 ;
        RECT  49.776 23.676 49.8 23.76 ;
    END
  END i[555]
  PIN i[556]
    DIRECTION INPUT ;
    USE SIGNAL ;
    PORT
      LAYER M5 ;
        RECT  49.872 23.676 49.896 23.76 ;
    END
  END i[556]
  PIN i[557]
    DIRECTION INPUT ;
    USE SIGNAL ;
    PORT
      LAYER M5 ;
        RECT  49.968 23.676 49.992 23.76 ;
    END
  END i[557]
  PIN i[558]
    DIRECTION INPUT ;
    USE SIGNAL ;
    PORT
      LAYER M5 ;
        RECT  50.064 23.676 50.088 23.76 ;
    END
  END i[558]
  PIN i[559]
    DIRECTION INPUT ;
    USE SIGNAL ;
    PORT
      LAYER M5 ;
        RECT  50.16 23.676 50.184 23.76 ;
    END
  END i[559]
  PIN i[55]
    DIRECTION INPUT ;
    USE SIGNAL ;
    PORT
      LAYER M5 ;
        RECT  34.8 23.676 34.824 23.76 ;
    END
  END i[55]
  PIN i[560]
    DIRECTION INPUT ;
    USE SIGNAL ;
    PORT
      LAYER M5 ;
        RECT  50.256 23.676 50.28 23.76 ;
    END
  END i[560]
  PIN i[561]
    DIRECTION INPUT ;
    USE SIGNAL ;
    PORT
      LAYER M5 ;
        RECT  50.352 23.676 50.376 23.76 ;
    END
  END i[561]
  PIN i[562]
    DIRECTION INPUT ;
    USE SIGNAL ;
    PORT
      LAYER M5 ;
        RECT  50.448 23.676 50.472 23.76 ;
    END
  END i[562]
  PIN i[563]
    DIRECTION INPUT ;
    USE SIGNAL ;
    PORT
      LAYER M5 ;
        RECT  50.544 23.676 50.568 23.76 ;
    END
  END i[563]
  PIN i[564]
    DIRECTION INPUT ;
    USE SIGNAL ;
    PORT
      LAYER M5 ;
        RECT  50.64 23.676 50.664 23.76 ;
    END
  END i[564]
  PIN i[565]
    DIRECTION INPUT ;
    USE SIGNAL ;
    PORT
      LAYER M5 ;
        RECT  50.736 23.676 50.76 23.76 ;
    END
  END i[565]
  PIN i[566]
    DIRECTION INPUT ;
    USE SIGNAL ;
    PORT
      LAYER M5 ;
        RECT  50.832 23.676 50.856 23.76 ;
    END
  END i[566]
  PIN i[567]
    DIRECTION INPUT ;
    USE SIGNAL ;
    PORT
      LAYER M5 ;
        RECT  50.928 23.676 50.952 23.76 ;
    END
  END i[567]
  PIN i[568]
    DIRECTION INPUT ;
    USE SIGNAL ;
    PORT
      LAYER M5 ;
        RECT  51.024 23.676 51.048 23.76 ;
    END
  END i[568]
  PIN i[569]
    DIRECTION INPUT ;
    USE SIGNAL ;
    PORT
      LAYER M5 ;
        RECT  51.12 23.676 51.144 23.76 ;
    END
  END i[569]
  PIN i[56]
    DIRECTION INPUT ;
    USE SIGNAL ;
    PORT
      LAYER M5 ;
        RECT  34.896 23.676 34.92 23.76 ;
    END
  END i[56]
  PIN i[570]
    DIRECTION INPUT ;
    USE SIGNAL ;
    PORT
      LAYER M5 ;
        RECT  51.216 23.676 51.24 23.76 ;
    END
  END i[570]
  PIN i[571]
    DIRECTION INPUT ;
    USE SIGNAL ;
    PORT
      LAYER M5 ;
        RECT  51.312 23.676 51.336 23.76 ;
    END
  END i[571]
  PIN i[572]
    DIRECTION INPUT ;
    USE SIGNAL ;
    PORT
      LAYER M5 ;
        RECT  51.408 23.676 51.432 23.76 ;
    END
  END i[572]
  PIN i[573]
    DIRECTION INPUT ;
    USE SIGNAL ;
    PORT
      LAYER M5 ;
        RECT  51.504 23.676 51.528 23.76 ;
    END
  END i[573]
  PIN i[574]
    DIRECTION INPUT ;
    USE SIGNAL ;
    PORT
      LAYER M5 ;
        RECT  51.6 23.676 51.624 23.76 ;
    END
  END i[574]
  PIN i[575]
    DIRECTION INPUT ;
    USE SIGNAL ;
    PORT
      LAYER M5 ;
        RECT  51.696 23.676 51.72 23.76 ;
    END
  END i[575]
  PIN i[576]
    DIRECTION INPUT ;
    USE SIGNAL ;
    PORT
      LAYER M5 ;
        RECT  51.792 23.676 51.816 23.76 ;
    END
  END i[576]
  PIN i[577]
    DIRECTION INPUT ;
    USE SIGNAL ;
    PORT
      LAYER M5 ;
        RECT  51.888 23.676 51.912 23.76 ;
    END
  END i[577]
  PIN i[578]
    DIRECTION INPUT ;
    USE SIGNAL ;
    PORT
      LAYER M5 ;
        RECT  51.984 23.676 52.008 23.76 ;
    END
  END i[578]
  PIN i[579]
    DIRECTION INPUT ;
    USE SIGNAL ;
    PORT
      LAYER M5 ;
        RECT  52.08 23.676 52.104 23.76 ;
    END
  END i[579]
  PIN i[57]
    DIRECTION INPUT ;
    USE SIGNAL ;
    PORT
      LAYER M5 ;
        RECT  34.992 23.676 35.016 23.76 ;
    END
  END i[57]
  PIN i[580]
    DIRECTION INPUT ;
    USE SIGNAL ;
    PORT
      LAYER M5 ;
        RECT  52.176 23.676 52.2 23.76 ;
    END
  END i[580]
  PIN i[581]
    DIRECTION INPUT ;
    USE SIGNAL ;
    PORT
      LAYER M5 ;
        RECT  52.272 23.676 52.296 23.76 ;
    END
  END i[581]
  PIN i[582]
    DIRECTION INPUT ;
    USE SIGNAL ;
    PORT
      LAYER M5 ;
        RECT  52.368 23.676 52.392 23.76 ;
    END
  END i[582]
  PIN i[583]
    DIRECTION INPUT ;
    USE SIGNAL ;
    PORT
      LAYER M5 ;
        RECT  52.464 23.676 52.488 23.76 ;
    END
  END i[583]
  PIN i[584]
    DIRECTION INPUT ;
    USE SIGNAL ;
    PORT
      LAYER M5 ;
        RECT  52.56 23.676 52.584 23.76 ;
    END
  END i[584]
  PIN i[585]
    DIRECTION INPUT ;
    USE SIGNAL ;
    PORT
      LAYER M5 ;
        RECT  52.656 23.676 52.68 23.76 ;
    END
  END i[585]
  PIN i[586]
    DIRECTION INPUT ;
    USE SIGNAL ;
    PORT
      LAYER M5 ;
        RECT  52.752 23.676 52.776 23.76 ;
    END
  END i[586]
  PIN i[587]
    DIRECTION INPUT ;
    USE SIGNAL ;
    PORT
      LAYER M5 ;
        RECT  52.848 23.676 52.872 23.76 ;
    END
  END i[587]
  PIN i[588]
    DIRECTION INPUT ;
    USE SIGNAL ;
    PORT
      LAYER M5 ;
        RECT  52.944 23.676 52.968 23.76 ;
    END
  END i[588]
  PIN i[589]
    DIRECTION INPUT ;
    USE SIGNAL ;
    PORT
      LAYER M5 ;
        RECT  53.04 23.676 53.064 23.76 ;
    END
  END i[589]
  PIN i[58]
    DIRECTION INPUT ;
    USE SIGNAL ;
    PORT
      LAYER M5 ;
        RECT  35.088 23.676 35.112 23.76 ;
    END
  END i[58]
  PIN i[590]
    DIRECTION INPUT ;
    USE SIGNAL ;
    PORT
      LAYER M5 ;
        RECT  53.136 23.676 53.16 23.76 ;
    END
  END i[590]
  PIN i[591]
    DIRECTION INPUT ;
    USE SIGNAL ;
    PORT
      LAYER M5 ;
        RECT  53.232 23.676 53.256 23.76 ;
    END
  END i[591]
  PIN i[592]
    DIRECTION INPUT ;
    USE SIGNAL ;
    PORT
      LAYER M5 ;
        RECT  53.328 23.676 53.352 23.76 ;
    END
  END i[592]
  PIN i[593]
    DIRECTION INPUT ;
    USE SIGNAL ;
    PORT
      LAYER M5 ;
        RECT  53.424 23.676 53.448 23.76 ;
    END
  END i[593]
  PIN i[594]
    DIRECTION INPUT ;
    USE SIGNAL ;
    PORT
      LAYER M5 ;
        RECT  53.52 23.676 53.544 23.76 ;
    END
  END i[594]
  PIN i[595]
    DIRECTION INPUT ;
    USE SIGNAL ;
    PORT
      LAYER M5 ;
        RECT  53.616 23.676 53.64 23.76 ;
    END
  END i[595]
  PIN i[596]
    DIRECTION INPUT ;
    USE SIGNAL ;
    PORT
      LAYER M5 ;
        RECT  53.712 23.676 53.736 23.76 ;
    END
  END i[596]
  PIN i[597]
    DIRECTION INPUT ;
    USE SIGNAL ;
    PORT
      LAYER M5 ;
        RECT  53.808 23.676 53.832 23.76 ;
    END
  END i[597]
  PIN i[598]
    DIRECTION INPUT ;
    USE SIGNAL ;
    PORT
      LAYER M5 ;
        RECT  53.904 23.676 53.928 23.76 ;
    END
  END i[598]
  PIN i[599]
    DIRECTION INPUT ;
    USE SIGNAL ;
    PORT
      LAYER M5 ;
        RECT  54 23.676 54.024 23.76 ;
    END
  END i[599]
  PIN i[59]
    DIRECTION INPUT ;
    USE SIGNAL ;
    PORT
      LAYER M5 ;
        RECT  35.184 23.676 35.208 23.76 ;
    END
  END i[59]
  PIN i[5]
    DIRECTION INPUT ;
    USE SIGNAL ;
    PORT
      LAYER M5 ;
        RECT  36.144 23.676 36.168 23.76 ;
    END
  END i[5]
  PIN i[600]
    DIRECTION INPUT ;
    USE SIGNAL ;
    PORT
      LAYER M5 ;
        RECT  54.096 23.676 54.12 23.76 ;
    END
  END i[600]
  PIN i[601]
    DIRECTION INPUT ;
    USE SIGNAL ;
    PORT
      LAYER M5 ;
        RECT  54.192 23.676 54.216 23.76 ;
    END
  END i[601]
  PIN i[602]
    DIRECTION INPUT ;
    USE SIGNAL ;
    PORT
      LAYER M5 ;
        RECT  54.288 23.676 54.312 23.76 ;
    END
  END i[602]
  PIN i[603]
    DIRECTION INPUT ;
    USE SIGNAL ;
    PORT
      LAYER M5 ;
        RECT  54.384 23.676 54.408 23.76 ;
    END
  END i[603]
  PIN i[604]
    DIRECTION INPUT ;
    USE SIGNAL ;
    PORT
      LAYER M5 ;
        RECT  54.48 23.676 54.504 23.76 ;
    END
  END i[604]
  PIN i[605]
    DIRECTION INPUT ;
    USE SIGNAL ;
    PORT
      LAYER M5 ;
        RECT  54.576 23.676 54.6 23.76 ;
    END
  END i[605]
  PIN i[606]
    DIRECTION INPUT ;
    USE SIGNAL ;
    PORT
      LAYER M5 ;
        RECT  54.672 23.676 54.696 23.76 ;
    END
  END i[606]
  PIN i[607]
    DIRECTION INPUT ;
    USE SIGNAL ;
    PORT
      LAYER M5 ;
        RECT  54.768 23.676 54.792 23.76 ;
    END
  END i[607]
  PIN i[608]
    DIRECTION INPUT ;
    USE SIGNAL ;
    PORT
      LAYER M5 ;
        RECT  1.872 23.676 1.896 23.76 ;
    END
  END i[608]
  PIN i[609]
    DIRECTION INPUT ;
    USE SIGNAL ;
    PORT
      LAYER M5 ;
        RECT  1.968 23.676 1.992 23.76 ;
    END
  END i[609]
  PIN i[60]
    DIRECTION INPUT ;
    USE SIGNAL ;
    PORT
      LAYER M5 ;
        RECT  35.28 23.676 35.304 23.76 ;
    END
  END i[60]
  PIN i[610]
    DIRECTION INPUT ;
    USE SIGNAL ;
    PORT
      LAYER M5 ;
        RECT  2.064 23.676 2.088 23.76 ;
    END
  END i[610]
  PIN i[611]
    DIRECTION INPUT ;
    USE SIGNAL ;
    PORT
      LAYER M5 ;
        RECT  2.16 23.676 2.184 23.76 ;
    END
  END i[611]
  PIN i[612]
    DIRECTION INPUT ;
    USE SIGNAL ;
    PORT
      LAYER M5 ;
        RECT  2.256 23.676 2.28 23.76 ;
    END
  END i[612]
  PIN i[613]
    DIRECTION INPUT ;
    USE SIGNAL ;
    PORT
      LAYER M5 ;
        RECT  2.352 23.676 2.376 23.76 ;
    END
  END i[613]
  PIN i[614]
    DIRECTION INPUT ;
    USE SIGNAL ;
    PORT
      LAYER M5 ;
        RECT  2.448 23.676 2.472 23.76 ;
    END
  END i[614]
  PIN i[615]
    DIRECTION INPUT ;
    USE SIGNAL ;
    PORT
      LAYER M5 ;
        RECT  2.544 23.676 2.568 23.76 ;
    END
  END i[615]
  PIN i[616]
    DIRECTION INPUT ;
    USE SIGNAL ;
    PORT
      LAYER M5 ;
        RECT  2.64 23.676 2.664 23.76 ;
    END
  END i[616]
  PIN i[617]
    DIRECTION INPUT ;
    USE SIGNAL ;
    PORT
      LAYER M5 ;
        RECT  2.736 23.676 2.76 23.76 ;
    END
  END i[617]
  PIN i[618]
    DIRECTION INPUT ;
    USE SIGNAL ;
    PORT
      LAYER M5 ;
        RECT  2.832 23.676 2.856 23.76 ;
    END
  END i[618]
  PIN i[619]
    DIRECTION INPUT ;
    USE SIGNAL ;
    PORT
      LAYER M5 ;
        RECT  2.928 23.676 2.952 23.76 ;
    END
  END i[619]
  PIN i[61]
    DIRECTION INPUT ;
    USE SIGNAL ;
    PORT
      LAYER M5 ;
        RECT  35.376 23.676 35.4 23.76 ;
    END
  END i[61]
  PIN i[620]
    DIRECTION INPUT ;
    USE SIGNAL ;
    PORT
      LAYER M5 ;
        RECT  3.024 23.676 3.048 23.76 ;
    END
  END i[620]
  PIN i[621]
    DIRECTION INPUT ;
    USE SIGNAL ;
    PORT
      LAYER M5 ;
        RECT  3.12 23.676 3.144 23.76 ;
    END
  END i[621]
  PIN i[622]
    DIRECTION INPUT ;
    USE SIGNAL ;
    PORT
      LAYER M5 ;
        RECT  3.216 23.676 3.24 23.76 ;
    END
  END i[622]
  PIN i[623]
    DIRECTION INPUT ;
    USE SIGNAL ;
    PORT
      LAYER M5 ;
        RECT  3.312 23.676 3.336 23.76 ;
    END
  END i[623]
  PIN i[62]
    DIRECTION INPUT ;
    USE SIGNAL ;
    PORT
      LAYER M5 ;
        RECT  35.472 23.676 35.496 23.76 ;
    END
  END i[62]
  PIN i[63]
    DIRECTION INPUT ;
    USE SIGNAL ;
    PORT
      LAYER M5 ;
        RECT  35.568 23.676 35.592 23.76 ;
    END
  END i[63]
  PIN i[64]
    DIRECTION INPUT ;
    USE SIGNAL ;
    PORT
      LAYER M5 ;
        RECT  41.808 23.676 41.832 23.76 ;
    END
  END i[64]
  PIN i[65]
    DIRECTION INPUT ;
    USE SIGNAL ;
    PORT
      LAYER M5 ;
        RECT  41.904 23.676 41.928 23.76 ;
    END
  END i[65]
  PIN i[66]
    DIRECTION INPUT ;
    USE SIGNAL ;
    PORT
      LAYER M5 ;
        RECT  42 23.676 42.024 23.76 ;
    END
  END i[66]
  PIN i[67]
    DIRECTION INPUT ;
    USE SIGNAL ;
    PORT
      LAYER M5 ;
        RECT  42.096 23.676 42.12 23.76 ;
    END
  END i[67]
  PIN i[68]
    DIRECTION INPUT ;
    USE SIGNAL ;
    PORT
      LAYER M5 ;
        RECT  42.192 23.676 42.216 23.76 ;
    END
  END i[68]
  PIN i[69]
    DIRECTION INPUT ;
    USE SIGNAL ;
    PORT
      LAYER M5 ;
        RECT  42.288 23.676 42.312 23.76 ;
    END
  END i[69]
  PIN i[6]
    DIRECTION INPUT ;
    USE SIGNAL ;
    PORT
      LAYER M5 ;
        RECT  36.24 23.676 36.264 23.76 ;
    END
  END i[6]
  PIN i[70]
    DIRECTION INPUT ;
    USE SIGNAL ;
    PORT
      LAYER M5 ;
        RECT  42.384 23.676 42.408 23.76 ;
    END
  END i[70]
  PIN i[71]
    DIRECTION INPUT ;
    USE SIGNAL ;
    PORT
      LAYER M5 ;
        RECT  42.48 23.676 42.504 23.76 ;
    END
  END i[71]
  PIN i[72]
    DIRECTION INPUT ;
    USE SIGNAL ;
    PORT
      LAYER M5 ;
        RECT  42.576 23.676 42.6 23.76 ;
    END
  END i[72]
  PIN i[73]
    DIRECTION INPUT ;
    USE SIGNAL ;
    PORT
      LAYER M5 ;
        RECT  42.672 23.676 42.696 23.76 ;
    END
  END i[73]
  PIN i[74]
    DIRECTION INPUT ;
    USE SIGNAL ;
    PORT
      LAYER M5 ;
        RECT  42.768 23.676 42.792 23.76 ;
    END
  END i[74]
  PIN i[75]
    DIRECTION INPUT ;
    USE SIGNAL ;
    PORT
      LAYER M5 ;
        RECT  42.864 23.676 42.888 23.76 ;
    END
  END i[75]
  PIN i[76]
    DIRECTION INPUT ;
    USE SIGNAL ;
    PORT
      LAYER M5 ;
        RECT  42.96 23.676 42.984 23.76 ;
    END
  END i[76]
  PIN i[77]
    DIRECTION INPUT ;
    USE SIGNAL ;
    PORT
      LAYER M5 ;
        RECT  43.056 23.676 43.08 23.76 ;
    END
  END i[77]
  PIN i[78]
    DIRECTION INPUT ;
    USE SIGNAL ;
    PORT
      LAYER M5 ;
        RECT  43.152 23.676 43.176 23.76 ;
    END
  END i[78]
  PIN i[79]
    DIRECTION INPUT ;
    USE SIGNAL ;
    PORT
      LAYER M5 ;
        RECT  43.248 23.676 43.272 23.76 ;
    END
  END i[79]
  PIN i[7]
    DIRECTION INPUT ;
    USE SIGNAL ;
    PORT
      LAYER M5 ;
        RECT  36.336 23.676 36.36 23.76 ;
    END
  END i[7]
  PIN i[80]
    DIRECTION INPUT ;
    USE SIGNAL ;
    PORT
      LAYER M5 ;
        RECT  43.344 23.676 43.368 23.76 ;
    END
  END i[80]
  PIN i[81]
    DIRECTION INPUT ;
    USE SIGNAL ;
    PORT
      LAYER M5 ;
        RECT  43.44 23.676 43.464 23.76 ;
    END
  END i[81]
  PIN i[82]
    DIRECTION INPUT ;
    USE SIGNAL ;
    PORT
      LAYER M5 ;
        RECT  43.536 23.676 43.56 23.76 ;
    END
  END i[82]
  PIN i[83]
    DIRECTION INPUT ;
    USE SIGNAL ;
    PORT
      LAYER M5 ;
        RECT  43.632 23.676 43.656 23.76 ;
    END
  END i[83]
  PIN i[84]
    DIRECTION INPUT ;
    USE SIGNAL ;
    PORT
      LAYER M5 ;
        RECT  43.728 23.676 43.752 23.76 ;
    END
  END i[84]
  PIN i[85]
    DIRECTION INPUT ;
    USE SIGNAL ;
    PORT
      LAYER M5 ;
        RECT  43.824 23.676 43.848 23.76 ;
    END
  END i[85]
  PIN i[86]
    DIRECTION INPUT ;
    USE SIGNAL ;
    PORT
      LAYER M5 ;
        RECT  43.92 23.676 43.944 23.76 ;
    END
  END i[86]
  PIN i[87]
    DIRECTION INPUT ;
    USE SIGNAL ;
    PORT
      LAYER M5 ;
        RECT  44.016 23.676 44.04 23.76 ;
    END
  END i[87]
  PIN i[88]
    DIRECTION INPUT ;
    USE SIGNAL ;
    PORT
      LAYER M5 ;
        RECT  44.112 23.676 44.136 23.76 ;
    END
  END i[88]
  PIN i[89]
    DIRECTION INPUT ;
    USE SIGNAL ;
    PORT
      LAYER M5 ;
        RECT  44.208 23.676 44.232 23.76 ;
    END
  END i[89]
  PIN i[8]
    DIRECTION INPUT ;
    USE SIGNAL ;
    PORT
      LAYER M5 ;
        RECT  36.432 23.676 36.456 23.76 ;
    END
  END i[8]
  PIN i[90]
    DIRECTION INPUT ;
    USE SIGNAL ;
    PORT
      LAYER M5 ;
        RECT  44.304 23.676 44.328 23.76 ;
    END
  END i[90]
  PIN i[91]
    DIRECTION INPUT ;
    USE SIGNAL ;
    PORT
      LAYER M5 ;
        RECT  44.4 23.676 44.424 23.76 ;
    END
  END i[91]
  PIN i[92]
    DIRECTION INPUT ;
    USE SIGNAL ;
    PORT
      LAYER M5 ;
        RECT  44.496 23.676 44.52 23.76 ;
    END
  END i[92]
  PIN i[93]
    DIRECTION INPUT ;
    USE SIGNAL ;
    PORT
      LAYER M5 ;
        RECT  44.592 23.676 44.616 23.76 ;
    END
  END i[93]
  PIN i[94]
    DIRECTION INPUT ;
    USE SIGNAL ;
    PORT
      LAYER M5 ;
        RECT  44.688 23.676 44.712 23.76 ;
    END
  END i[94]
  PIN i[95]
    DIRECTION INPUT ;
    USE SIGNAL ;
    PORT
      LAYER M5 ;
        RECT  44.784 23.676 44.808 23.76 ;
    END
  END i[95]
  PIN i[96]
    DIRECTION INPUT ;
    USE SIGNAL ;
    PORT
      LAYER M5 ;
        RECT  38.736 23.676 38.76 23.76 ;
    END
  END i[96]
  PIN i[97]
    DIRECTION INPUT ;
    USE SIGNAL ;
    PORT
      LAYER M5 ;
        RECT  38.832 23.676 38.856 23.76 ;
    END
  END i[97]
  PIN i[98]
    DIRECTION INPUT ;
    USE SIGNAL ;
    PORT
      LAYER M5 ;
        RECT  38.928 23.676 38.952 23.76 ;
    END
  END i[98]
  PIN i[99]
    DIRECTION INPUT ;
    USE SIGNAL ;
    PORT
      LAYER M5 ;
        RECT  39.024 23.676 39.048 23.76 ;
    END
  END i[99]
  PIN i[9]
    DIRECTION INPUT ;
    USE SIGNAL ;
    PORT
      LAYER M5 ;
        RECT  36.528 23.676 36.552 23.76 ;
    END
  END i[9]
  PIN o[0]
    DIRECTION OUTPUT ;
    USE SIGNAL ;
    PORT
      LAYER M5 ;
        RECT  35.28 0 35.304 0.084 ;
    END
  END o[0]
  PIN o[100]
    DIRECTION OUTPUT ;
    USE SIGNAL ;
    PORT
      LAYER M5 ;
        RECT  29.52 0 29.544 0.084 ;
    END
  END o[100]
  PIN o[101]
    DIRECTION OUTPUT ;
    USE SIGNAL ;
    PORT
      LAYER M5 ;
        RECT  29.616 0 29.64 0.084 ;
    END
  END o[101]
  PIN o[102]
    DIRECTION OUTPUT ;
    USE SIGNAL ;
    PORT
      LAYER M5 ;
        RECT  29.712 0 29.736 0.084 ;
    END
  END o[102]
  PIN o[103]
    DIRECTION OUTPUT ;
    USE SIGNAL ;
    PORT
      LAYER M5 ;
        RECT  29.808 0 29.832 0.084 ;
    END
  END o[103]
  PIN o[104]
    DIRECTION OUTPUT ;
    USE SIGNAL ;
    PORT
      LAYER M5 ;
        RECT  29.904 0 29.928 0.084 ;
    END
  END o[104]
  PIN o[105]
    DIRECTION OUTPUT ;
    USE SIGNAL ;
    PORT
      LAYER M5 ;
        RECT  30 0 30.024 0.084 ;
    END
  END o[105]
  PIN o[106]
    DIRECTION OUTPUT ;
    USE SIGNAL ;
    PORT
      LAYER M5 ;
        RECT  30.096 0 30.12 0.084 ;
    END
  END o[106]
  PIN o[107]
    DIRECTION OUTPUT ;
    USE SIGNAL ;
    PORT
      LAYER M5 ;
        RECT  30.192 0 30.216 0.084 ;
    END
  END o[107]
  PIN o[108]
    DIRECTION OUTPUT ;
    USE SIGNAL ;
    PORT
      LAYER M5 ;
        RECT  30.288 0 30.312 0.084 ;
    END
  END o[108]
  PIN o[109]
    DIRECTION OUTPUT ;
    USE SIGNAL ;
    PORT
      LAYER M5 ;
        RECT  30.384 0 30.408 0.084 ;
    END
  END o[109]
  PIN o[10]
    DIRECTION OUTPUT ;
    USE SIGNAL ;
    PORT
      LAYER M5 ;
        RECT  36.24 0 36.264 0.084 ;
    END
  END o[10]
  PIN o[110]
    DIRECTION OUTPUT ;
    USE SIGNAL ;
    PORT
      LAYER M5 ;
        RECT  30.48 0 30.504 0.084 ;
    END
  END o[110]
  PIN o[111]
    DIRECTION OUTPUT ;
    USE SIGNAL ;
    PORT
      LAYER M5 ;
        RECT  30.576 0 30.6 0.084 ;
    END
  END o[111]
  PIN o[112]
    DIRECTION OUTPUT ;
    USE SIGNAL ;
    PORT
      LAYER M5 ;
        RECT  30.672 0 30.696 0.084 ;
    END
  END o[112]
  PIN o[113]
    DIRECTION OUTPUT ;
    USE SIGNAL ;
    PORT
      LAYER M5 ;
        RECT  30.768 0 30.792 0.084 ;
    END
  END o[113]
  PIN o[114]
    DIRECTION OUTPUT ;
    USE SIGNAL ;
    PORT
      LAYER M5 ;
        RECT  30.864 0 30.888 0.084 ;
    END
  END o[114]
  PIN o[115]
    DIRECTION OUTPUT ;
    USE SIGNAL ;
    PORT
      LAYER M5 ;
        RECT  30.96 0 30.984 0.084 ;
    END
  END o[115]
  PIN o[116]
    DIRECTION OUTPUT ;
    USE SIGNAL ;
    PORT
      LAYER M5 ;
        RECT  31.056 0 31.08 0.084 ;
    END
  END o[116]
  PIN o[117]
    DIRECTION OUTPUT ;
    USE SIGNAL ;
    PORT
      LAYER M5 ;
        RECT  31.152 0 31.176 0.084 ;
    END
  END o[117]
  PIN o[118]
    DIRECTION OUTPUT ;
    USE SIGNAL ;
    PORT
      LAYER M5 ;
        RECT  31.248 0 31.272 0.084 ;
    END
  END o[118]
  PIN o[119]
    DIRECTION OUTPUT ;
    USE SIGNAL ;
    PORT
      LAYER M5 ;
        RECT  31.344 0 31.368 0.084 ;
    END
  END o[119]
  PIN o[11]
    DIRECTION OUTPUT ;
    USE SIGNAL ;
    PORT
      LAYER M5 ;
        RECT  36.336 0 36.36 0.084 ;
    END
  END o[11]
  PIN o[120]
    DIRECTION OUTPUT ;
    USE SIGNAL ;
    PORT
      LAYER M5 ;
        RECT  31.44 0 31.464 0.084 ;
    END
  END o[120]
  PIN o[121]
    DIRECTION OUTPUT ;
    USE SIGNAL ;
    PORT
      LAYER M5 ;
        RECT  31.536 0 31.56 0.084 ;
    END
  END o[121]
  PIN o[122]
    DIRECTION OUTPUT ;
    USE SIGNAL ;
    PORT
      LAYER M5 ;
        RECT  31.632 0 31.656 0.084 ;
    END
  END o[122]
  PIN o[123]
    DIRECTION OUTPUT ;
    USE SIGNAL ;
    PORT
      LAYER M5 ;
        RECT  31.728 0 31.752 0.084 ;
    END
  END o[123]
  PIN o[124]
    DIRECTION OUTPUT ;
    USE SIGNAL ;
    PORT
      LAYER M5 ;
        RECT  31.824 0 31.848 0.084 ;
    END
  END o[124]
  PIN o[125]
    DIRECTION OUTPUT ;
    USE SIGNAL ;
    PORT
      LAYER M5 ;
        RECT  31.92 0 31.944 0.084 ;
    END
  END o[125]
  PIN o[126]
    DIRECTION OUTPUT ;
    USE SIGNAL ;
    PORT
      LAYER M5 ;
        RECT  32.016 0 32.04 0.084 ;
    END
  END o[126]
  PIN o[127]
    DIRECTION OUTPUT ;
    USE SIGNAL ;
    PORT
      LAYER M5 ;
        RECT  32.112 0 32.136 0.084 ;
    END
  END o[127]
  PIN o[128]
    DIRECTION OUTPUT ;
    USE SIGNAL ;
    PORT
      LAYER M5 ;
        RECT  19.92 0 19.944 0.084 ;
    END
  END o[128]
  PIN o[129]
    DIRECTION OUTPUT ;
    USE SIGNAL ;
    PORT
      LAYER M5 ;
        RECT  20.016 0 20.04 0.084 ;
    END
  END o[129]
  PIN o[12]
    DIRECTION OUTPUT ;
    USE SIGNAL ;
    PORT
      LAYER M5 ;
        RECT  36.432 0 36.456 0.084 ;
    END
  END o[12]
  PIN o[130]
    DIRECTION OUTPUT ;
    USE SIGNAL ;
    PORT
      LAYER M5 ;
        RECT  20.112 0 20.136 0.084 ;
    END
  END o[130]
  PIN o[131]
    DIRECTION OUTPUT ;
    USE SIGNAL ;
    PORT
      LAYER M5 ;
        RECT  20.208 0 20.232 0.084 ;
    END
  END o[131]
  PIN o[132]
    DIRECTION OUTPUT ;
    USE SIGNAL ;
    PORT
      LAYER M5 ;
        RECT  20.304 0 20.328 0.084 ;
    END
  END o[132]
  PIN o[133]
    DIRECTION OUTPUT ;
    USE SIGNAL ;
    PORT
      LAYER M5 ;
        RECT  20.4 0 20.424 0.084 ;
    END
  END o[133]
  PIN o[134]
    DIRECTION OUTPUT ;
    USE SIGNAL ;
    PORT
      LAYER M5 ;
        RECT  20.496 0 20.52 0.084 ;
    END
  END o[134]
  PIN o[135]
    DIRECTION OUTPUT ;
    USE SIGNAL ;
    PORT
      LAYER M5 ;
        RECT  20.592 0 20.616 0.084 ;
    END
  END o[135]
  PIN o[136]
    DIRECTION OUTPUT ;
    USE SIGNAL ;
    PORT
      LAYER M5 ;
        RECT  20.688 0 20.712 0.084 ;
    END
  END o[136]
  PIN o[137]
    DIRECTION OUTPUT ;
    USE SIGNAL ;
    PORT
      LAYER M5 ;
        RECT  20.784 0 20.808 0.084 ;
    END
  END o[137]
  PIN o[138]
    DIRECTION OUTPUT ;
    USE SIGNAL ;
    PORT
      LAYER M5 ;
        RECT  20.88 0 20.904 0.084 ;
    END
  END o[138]
  PIN o[139]
    DIRECTION OUTPUT ;
    USE SIGNAL ;
    PORT
      LAYER M5 ;
        RECT  20.976 0 21 0.084 ;
    END
  END o[139]
  PIN o[13]
    DIRECTION OUTPUT ;
    USE SIGNAL ;
    PORT
      LAYER M5 ;
        RECT  36.528 0 36.552 0.084 ;
    END
  END o[13]
  PIN o[140]
    DIRECTION OUTPUT ;
    USE SIGNAL ;
    PORT
      LAYER M5 ;
        RECT  21.072 0 21.096 0.084 ;
    END
  END o[140]
  PIN o[141]
    DIRECTION OUTPUT ;
    USE SIGNAL ;
    PORT
      LAYER M5 ;
        RECT  21.168 0 21.192 0.084 ;
    END
  END o[141]
  PIN o[142]
    DIRECTION OUTPUT ;
    USE SIGNAL ;
    PORT
      LAYER M5 ;
        RECT  21.264 0 21.288 0.084 ;
    END
  END o[142]
  PIN o[143]
    DIRECTION OUTPUT ;
    USE SIGNAL ;
    PORT
      LAYER M5 ;
        RECT  21.36 0 21.384 0.084 ;
    END
  END o[143]
  PIN o[144]
    DIRECTION OUTPUT ;
    USE SIGNAL ;
    PORT
      LAYER M5 ;
        RECT  21.456 0 21.48 0.084 ;
    END
  END o[144]
  PIN o[145]
    DIRECTION OUTPUT ;
    USE SIGNAL ;
    PORT
      LAYER M5 ;
        RECT  21.552 0 21.576 0.084 ;
    END
  END o[145]
  PIN o[146]
    DIRECTION OUTPUT ;
    USE SIGNAL ;
    PORT
      LAYER M5 ;
        RECT  21.648 0 21.672 0.084 ;
    END
  END o[146]
  PIN o[147]
    DIRECTION OUTPUT ;
    USE SIGNAL ;
    PORT
      LAYER M5 ;
        RECT  21.744 0 21.768 0.084 ;
    END
  END o[147]
  PIN o[148]
    DIRECTION OUTPUT ;
    USE SIGNAL ;
    PORT
      LAYER M5 ;
        RECT  21.84 0 21.864 0.084 ;
    END
  END o[148]
  PIN o[149]
    DIRECTION OUTPUT ;
    USE SIGNAL ;
    PORT
      LAYER M5 ;
        RECT  21.936 0 21.96 0.084 ;
    END
  END o[149]
  PIN o[14]
    DIRECTION OUTPUT ;
    USE SIGNAL ;
    PORT
      LAYER M5 ;
        RECT  36.624 0 36.648 0.084 ;
    END
  END o[14]
  PIN o[150]
    DIRECTION OUTPUT ;
    USE SIGNAL ;
    PORT
      LAYER M5 ;
        RECT  22.032 0 22.056 0.084 ;
    END
  END o[150]
  PIN o[151]
    DIRECTION OUTPUT ;
    USE SIGNAL ;
    PORT
      LAYER M5 ;
        RECT  22.128 0 22.152 0.084 ;
    END
  END o[151]
  PIN o[152]
    DIRECTION OUTPUT ;
    USE SIGNAL ;
    PORT
      LAYER M5 ;
        RECT  22.224 0 22.248 0.084 ;
    END
  END o[152]
  PIN o[153]
    DIRECTION OUTPUT ;
    USE SIGNAL ;
    PORT
      LAYER M5 ;
        RECT  22.32 0 22.344 0.084 ;
    END
  END o[153]
  PIN o[154]
    DIRECTION OUTPUT ;
    USE SIGNAL ;
    PORT
      LAYER M5 ;
        RECT  22.416 0 22.44 0.084 ;
    END
  END o[154]
  PIN o[155]
    DIRECTION OUTPUT ;
    USE SIGNAL ;
    PORT
      LAYER M5 ;
        RECT  22.512 0 22.536 0.084 ;
    END
  END o[155]
  PIN o[156]
    DIRECTION OUTPUT ;
    USE SIGNAL ;
    PORT
      LAYER M5 ;
        RECT  22.608 0 22.632 0.084 ;
    END
  END o[156]
  PIN o[157]
    DIRECTION OUTPUT ;
    USE SIGNAL ;
    PORT
      LAYER M5 ;
        RECT  22.704 0 22.728 0.084 ;
    END
  END o[157]
  PIN o[158]
    DIRECTION OUTPUT ;
    USE SIGNAL ;
    PORT
      LAYER M5 ;
        RECT  22.8 0 22.824 0.084 ;
    END
  END o[158]
  PIN o[159]
    DIRECTION OUTPUT ;
    USE SIGNAL ;
    PORT
      LAYER M5 ;
        RECT  22.896 0 22.92 0.084 ;
    END
  END o[159]
  PIN o[15]
    DIRECTION OUTPUT ;
    USE SIGNAL ;
    PORT
      LAYER M5 ;
        RECT  36.72 0 36.744 0.084 ;
    END
  END o[15]
  PIN o[160]
    DIRECTION OUTPUT ;
    USE SIGNAL ;
    PORT
      LAYER M5 ;
        RECT  22.992 0 23.016 0.084 ;
    END
  END o[160]
  PIN o[161]
    DIRECTION OUTPUT ;
    USE SIGNAL ;
    PORT
      LAYER M5 ;
        RECT  23.088 0 23.112 0.084 ;
    END
  END o[161]
  PIN o[162]
    DIRECTION OUTPUT ;
    USE SIGNAL ;
    PORT
      LAYER M5 ;
        RECT  23.184 0 23.208 0.084 ;
    END
  END o[162]
  PIN o[163]
    DIRECTION OUTPUT ;
    USE SIGNAL ;
    PORT
      LAYER M5 ;
        RECT  23.28 0 23.304 0.084 ;
    END
  END o[163]
  PIN o[164]
    DIRECTION OUTPUT ;
    USE SIGNAL ;
    PORT
      LAYER M5 ;
        RECT  23.376 0 23.4 0.084 ;
    END
  END o[164]
  PIN o[165]
    DIRECTION OUTPUT ;
    USE SIGNAL ;
    PORT
      LAYER M5 ;
        RECT  23.472 0 23.496 0.084 ;
    END
  END o[165]
  PIN o[166]
    DIRECTION OUTPUT ;
    USE SIGNAL ;
    PORT
      LAYER M5 ;
        RECT  23.568 0 23.592 0.084 ;
    END
  END o[166]
  PIN o[167]
    DIRECTION OUTPUT ;
    USE SIGNAL ;
    PORT
      LAYER M5 ;
        RECT  23.664 0 23.688 0.084 ;
    END
  END o[167]
  PIN o[168]
    DIRECTION OUTPUT ;
    USE SIGNAL ;
    PORT
      LAYER M5 ;
        RECT  23.76 0 23.784 0.084 ;
    END
  END o[168]
  PIN o[169]
    DIRECTION OUTPUT ;
    USE SIGNAL ;
    PORT
      LAYER M5 ;
        RECT  23.856 0 23.88 0.084 ;
    END
  END o[169]
  PIN o[16]
    DIRECTION OUTPUT ;
    USE SIGNAL ;
    PORT
      LAYER M5 ;
        RECT  36.816 0 36.84 0.084 ;
    END
  END o[16]
  PIN o[170]
    DIRECTION OUTPUT ;
    USE SIGNAL ;
    PORT
      LAYER M5 ;
        RECT  23.952 0 23.976 0.084 ;
    END
  END o[170]
  PIN o[171]
    DIRECTION OUTPUT ;
    USE SIGNAL ;
    PORT
      LAYER M5 ;
        RECT  24.048 0 24.072 0.084 ;
    END
  END o[171]
  PIN o[172]
    DIRECTION OUTPUT ;
    USE SIGNAL ;
    PORT
      LAYER M5 ;
        RECT  24.144 0 24.168 0.084 ;
    END
  END o[172]
  PIN o[173]
    DIRECTION OUTPUT ;
    USE SIGNAL ;
    PORT
      LAYER M5 ;
        RECT  24.24 0 24.264 0.084 ;
    END
  END o[173]
  PIN o[174]
    DIRECTION OUTPUT ;
    USE SIGNAL ;
    PORT
      LAYER M5 ;
        RECT  24.336 0 24.36 0.084 ;
    END
  END o[174]
  PIN o[175]
    DIRECTION OUTPUT ;
    USE SIGNAL ;
    PORT
      LAYER M5 ;
        RECT  24.432 0 24.456 0.084 ;
    END
  END o[175]
  PIN o[176]
    DIRECTION OUTPUT ;
    USE SIGNAL ;
    PORT
      LAYER M5 ;
        RECT  24.528 0 24.552 0.084 ;
    END
  END o[176]
  PIN o[177]
    DIRECTION OUTPUT ;
    USE SIGNAL ;
    PORT
      LAYER M5 ;
        RECT  24.624 0 24.648 0.084 ;
    END
  END o[177]
  PIN o[178]
    DIRECTION OUTPUT ;
    USE SIGNAL ;
    PORT
      LAYER M5 ;
        RECT  24.72 0 24.744 0.084 ;
    END
  END o[178]
  PIN o[179]
    DIRECTION OUTPUT ;
    USE SIGNAL ;
    PORT
      LAYER M5 ;
        RECT  24.816 0 24.84 0.084 ;
    END
  END o[179]
  PIN o[17]
    DIRECTION OUTPUT ;
    USE SIGNAL ;
    PORT
      LAYER M5 ;
        RECT  36.912 0 36.936 0.084 ;
    END
  END o[17]
  PIN o[180]
    DIRECTION OUTPUT ;
    USE SIGNAL ;
    PORT
      LAYER M5 ;
        RECT  24.912 0 24.936 0.084 ;
    END
  END o[180]
  PIN o[181]
    DIRECTION OUTPUT ;
    USE SIGNAL ;
    PORT
      LAYER M5 ;
        RECT  25.008 0 25.032 0.084 ;
    END
  END o[181]
  PIN o[182]
    DIRECTION OUTPUT ;
    USE SIGNAL ;
    PORT
      LAYER M5 ;
        RECT  25.104 0 25.128 0.084 ;
    END
  END o[182]
  PIN o[183]
    DIRECTION OUTPUT ;
    USE SIGNAL ;
    PORT
      LAYER M5 ;
        RECT  25.2 0 25.224 0.084 ;
    END
  END o[183]
  PIN o[184]
    DIRECTION OUTPUT ;
    USE SIGNAL ;
    PORT
      LAYER M5 ;
        RECT  25.296 0 25.32 0.084 ;
    END
  END o[184]
  PIN o[185]
    DIRECTION OUTPUT ;
    USE SIGNAL ;
    PORT
      LAYER M5 ;
        RECT  25.392 0 25.416 0.084 ;
    END
  END o[185]
  PIN o[186]
    DIRECTION OUTPUT ;
    USE SIGNAL ;
    PORT
      LAYER M5 ;
        RECT  25.488 0 25.512 0.084 ;
    END
  END o[186]
  PIN o[187]
    DIRECTION OUTPUT ;
    USE SIGNAL ;
    PORT
      LAYER M5 ;
        RECT  25.584 0 25.608 0.084 ;
    END
  END o[187]
  PIN o[188]
    DIRECTION OUTPUT ;
    USE SIGNAL ;
    PORT
      LAYER M5 ;
        RECT  25.68 0 25.704 0.084 ;
    END
  END o[188]
  PIN o[189]
    DIRECTION OUTPUT ;
    USE SIGNAL ;
    PORT
      LAYER M5 ;
        RECT  25.776 0 25.8 0.084 ;
    END
  END o[189]
  PIN o[18]
    DIRECTION OUTPUT ;
    USE SIGNAL ;
    PORT
      LAYER M5 ;
        RECT  37.008 0 37.032 0.084 ;
    END
  END o[18]
  PIN o[190]
    DIRECTION OUTPUT ;
    USE SIGNAL ;
    PORT
      LAYER M5 ;
        RECT  25.872 0 25.896 0.084 ;
    END
  END o[190]
  PIN o[191]
    DIRECTION OUTPUT ;
    USE SIGNAL ;
    PORT
      LAYER M5 ;
        RECT  25.968 0 25.992 0.084 ;
    END
  END o[191]
  PIN o[192]
    DIRECTION OUTPUT ;
    USE SIGNAL ;
    PORT
      LAYER M5 ;
        RECT  54.48 0 54.504 0.084 ;
    END
  END o[192]
  PIN o[193]
    DIRECTION OUTPUT ;
    USE SIGNAL ;
    PORT
      LAYER M5 ;
        RECT  54.576 0 54.6 0.084 ;
    END
  END o[193]
  PIN o[194]
    DIRECTION OUTPUT ;
    USE SIGNAL ;
    PORT
      LAYER M5 ;
        RECT  54.672 0 54.696 0.084 ;
    END
  END o[194]
  PIN o[195]
    DIRECTION OUTPUT ;
    USE SIGNAL ;
    PORT
      LAYER M5 ;
        RECT  54.768 0 54.792 0.084 ;
    END
  END o[195]
  PIN o[196]
    DIRECTION OUTPUT ;
    USE SIGNAL ;
    PORT
      LAYER M5 ;
        RECT  54.864 0 54.888 0.084 ;
    END
  END o[196]
  PIN o[197]
    DIRECTION OUTPUT ;
    USE SIGNAL ;
    PORT
      LAYER M5 ;
        RECT  54.96 0 54.984 0.084 ;
    END
  END o[197]
  PIN o[198]
    DIRECTION OUTPUT ;
    USE SIGNAL ;
    PORT
      LAYER M5 ;
        RECT  55.056 0 55.08 0.084 ;
    END
  END o[198]
  PIN o[199]
    DIRECTION OUTPUT ;
    USE SIGNAL ;
    PORT
      LAYER M5 ;
        RECT  55.152 0 55.176 0.084 ;
    END
  END o[199]
  PIN o[19]
    DIRECTION OUTPUT ;
    USE SIGNAL ;
    PORT
      LAYER M5 ;
        RECT  37.104 0 37.128 0.084 ;
    END
  END o[19]
  PIN o[1]
    DIRECTION OUTPUT ;
    USE SIGNAL ;
    PORT
      LAYER M5 ;
        RECT  35.376 0 35.4 0.084 ;
    END
  END o[1]
  PIN o[200]
    DIRECTION OUTPUT ;
    USE SIGNAL ;
    PORT
      LAYER M5 ;
        RECT  55.248 0 55.272 0.084 ;
    END
  END o[200]
  PIN o[201]
    DIRECTION OUTPUT ;
    USE SIGNAL ;
    PORT
      LAYER M5 ;
        RECT  55.344 0 55.368 0.084 ;
    END
  END o[201]
  PIN o[202]
    DIRECTION OUTPUT ;
    USE SIGNAL ;
    PORT
      LAYER M5 ;
        RECT  55.44 0 55.464 0.084 ;
    END
  END o[202]
  PIN o[203]
    DIRECTION OUTPUT ;
    USE SIGNAL ;
    PORT
      LAYER M5 ;
        RECT  55.536 0 55.56 0.084 ;
    END
  END o[203]
  PIN o[204]
    DIRECTION OUTPUT ;
    USE SIGNAL ;
    PORT
      LAYER M5 ;
        RECT  55.632 0 55.656 0.084 ;
    END
  END o[204]
  PIN o[205]
    DIRECTION OUTPUT ;
    USE SIGNAL ;
    PORT
      LAYER M5 ;
        RECT  55.728 0 55.752 0.084 ;
    END
  END o[205]
  PIN o[206]
    DIRECTION OUTPUT ;
    USE SIGNAL ;
    PORT
      LAYER M5 ;
        RECT  55.824 0 55.848 0.084 ;
    END
  END o[206]
  PIN o[207]
    DIRECTION OUTPUT ;
    USE SIGNAL ;
    PORT
      LAYER M5 ;
        RECT  55.92 0 55.944 0.084 ;
    END
  END o[207]
  PIN o[208]
    DIRECTION OUTPUT ;
    USE SIGNAL ;
    PORT
      LAYER M5 ;
        RECT  56.016 0 56.04 0.084 ;
    END
  END o[208]
  PIN o[209]
    DIRECTION OUTPUT ;
    USE SIGNAL ;
    PORT
      LAYER M5 ;
        RECT  56.112 0 56.136 0.084 ;
    END
  END o[209]
  PIN o[20]
    DIRECTION OUTPUT ;
    USE SIGNAL ;
    PORT
      LAYER M5 ;
        RECT  37.2 0 37.224 0.084 ;
    END
  END o[20]
  PIN o[210]
    DIRECTION OUTPUT ;
    USE SIGNAL ;
    PORT
      LAYER M5 ;
        RECT  56.208 0 56.232 0.084 ;
    END
  END o[210]
  PIN o[211]
    DIRECTION OUTPUT ;
    USE SIGNAL ;
    PORT
      LAYER M5 ;
        RECT  56.304 0 56.328 0.084 ;
    END
  END o[211]
  PIN o[212]
    DIRECTION OUTPUT ;
    USE SIGNAL ;
    PORT
      LAYER M5 ;
        RECT  56.4 0 56.424 0.084 ;
    END
  END o[212]
  PIN o[213]
    DIRECTION OUTPUT ;
    USE SIGNAL ;
    PORT
      LAYER M5 ;
        RECT  56.496 0 56.52 0.084 ;
    END
  END o[213]
  PIN o[214]
    DIRECTION OUTPUT ;
    USE SIGNAL ;
    PORT
      LAYER M5 ;
        RECT  56.592 0 56.616 0.084 ;
    END
  END o[214]
  PIN o[215]
    DIRECTION OUTPUT ;
    USE SIGNAL ;
    PORT
      LAYER M5 ;
        RECT  56.688 0 56.712 0.084 ;
    END
  END o[215]
  PIN o[216]
    DIRECTION OUTPUT ;
    USE SIGNAL ;
    PORT
      LAYER M5 ;
        RECT  56.784 0 56.808 0.084 ;
    END
  END o[216]
  PIN o[217]
    DIRECTION OUTPUT ;
    USE SIGNAL ;
    PORT
      LAYER M5 ;
        RECT  56.88 0 56.904 0.084 ;
    END
  END o[217]
  PIN o[218]
    DIRECTION OUTPUT ;
    USE SIGNAL ;
    PORT
      LAYER M5 ;
        RECT  56.976 0 57 0.084 ;
    END
  END o[218]
  PIN o[219]
    DIRECTION OUTPUT ;
    USE SIGNAL ;
    PORT
      LAYER M5 ;
        RECT  57.072 0 57.096 0.084 ;
    END
  END o[219]
  PIN o[21]
    DIRECTION OUTPUT ;
    USE SIGNAL ;
    PORT
      LAYER M5 ;
        RECT  37.296 0 37.32 0.084 ;
    END
  END o[21]
  PIN o[220]
    DIRECTION OUTPUT ;
    USE SIGNAL ;
    PORT
      LAYER M5 ;
        RECT  57.168 0 57.192 0.084 ;
    END
  END o[220]
  PIN o[221]
    DIRECTION OUTPUT ;
    USE SIGNAL ;
    PORT
      LAYER M5 ;
        RECT  57.264 0 57.288 0.084 ;
    END
  END o[221]
  PIN o[222]
    DIRECTION OUTPUT ;
    USE SIGNAL ;
    PORT
      LAYER M5 ;
        RECT  57.36 0 57.384 0.084 ;
    END
  END o[222]
  PIN o[223]
    DIRECTION OUTPUT ;
    USE SIGNAL ;
    PORT
      LAYER M5 ;
        RECT  57.456 0 57.48 0.084 ;
    END
  END o[223]
  PIN o[224]
    DIRECTION OUTPUT ;
    USE SIGNAL ;
    PORT
      LAYER M5 ;
        RECT  51.408 0 51.432 0.084 ;
    END
  END o[224]
  PIN o[225]
    DIRECTION OUTPUT ;
    USE SIGNAL ;
    PORT
      LAYER M5 ;
        RECT  51.504 0 51.528 0.084 ;
    END
  END o[225]
  PIN o[226]
    DIRECTION OUTPUT ;
    USE SIGNAL ;
    PORT
      LAYER M5 ;
        RECT  51.6 0 51.624 0.084 ;
    END
  END o[226]
  PIN o[227]
    DIRECTION OUTPUT ;
    USE SIGNAL ;
    PORT
      LAYER M5 ;
        RECT  51.696 0 51.72 0.084 ;
    END
  END o[227]
  PIN o[228]
    DIRECTION OUTPUT ;
    USE SIGNAL ;
    PORT
      LAYER M5 ;
        RECT  51.792 0 51.816 0.084 ;
    END
  END o[228]
  PIN o[229]
    DIRECTION OUTPUT ;
    USE SIGNAL ;
    PORT
      LAYER M5 ;
        RECT  51.888 0 51.912 0.084 ;
    END
  END o[229]
  PIN o[22]
    DIRECTION OUTPUT ;
    USE SIGNAL ;
    PORT
      LAYER M5 ;
        RECT  37.392 0 37.416 0.084 ;
    END
  END o[22]
  PIN o[230]
    DIRECTION OUTPUT ;
    USE SIGNAL ;
    PORT
      LAYER M5 ;
        RECT  51.984 0 52.008 0.084 ;
    END
  END o[230]
  PIN o[231]
    DIRECTION OUTPUT ;
    USE SIGNAL ;
    PORT
      LAYER M5 ;
        RECT  52.08 0 52.104 0.084 ;
    END
  END o[231]
  PIN o[232]
    DIRECTION OUTPUT ;
    USE SIGNAL ;
    PORT
      LAYER M5 ;
        RECT  52.176 0 52.2 0.084 ;
    END
  END o[232]
  PIN o[233]
    DIRECTION OUTPUT ;
    USE SIGNAL ;
    PORT
      LAYER M5 ;
        RECT  52.272 0 52.296 0.084 ;
    END
  END o[233]
  PIN o[234]
    DIRECTION OUTPUT ;
    USE SIGNAL ;
    PORT
      LAYER M5 ;
        RECT  52.368 0 52.392 0.084 ;
    END
  END o[234]
  PIN o[235]
    DIRECTION OUTPUT ;
    USE SIGNAL ;
    PORT
      LAYER M5 ;
        RECT  52.464 0 52.488 0.084 ;
    END
  END o[235]
  PIN o[236]
    DIRECTION OUTPUT ;
    USE SIGNAL ;
    PORT
      LAYER M5 ;
        RECT  52.56 0 52.584 0.084 ;
    END
  END o[236]
  PIN o[237]
    DIRECTION OUTPUT ;
    USE SIGNAL ;
    PORT
      LAYER M5 ;
        RECT  52.656 0 52.68 0.084 ;
    END
  END o[237]
  PIN o[238]
    DIRECTION OUTPUT ;
    USE SIGNAL ;
    PORT
      LAYER M5 ;
        RECT  52.752 0 52.776 0.084 ;
    END
  END o[238]
  PIN o[239]
    DIRECTION OUTPUT ;
    USE SIGNAL ;
    PORT
      LAYER M5 ;
        RECT  52.848 0 52.872 0.084 ;
    END
  END o[239]
  PIN o[23]
    DIRECTION OUTPUT ;
    USE SIGNAL ;
    PORT
      LAYER M5 ;
        RECT  37.488 0 37.512 0.084 ;
    END
  END o[23]
  PIN o[240]
    DIRECTION OUTPUT ;
    USE SIGNAL ;
    PORT
      LAYER M5 ;
        RECT  52.944 0 52.968 0.084 ;
    END
  END o[240]
  PIN o[241]
    DIRECTION OUTPUT ;
    USE SIGNAL ;
    PORT
      LAYER M5 ;
        RECT  53.04 0 53.064 0.084 ;
    END
  END o[241]
  PIN o[242]
    DIRECTION OUTPUT ;
    USE SIGNAL ;
    PORT
      LAYER M5 ;
        RECT  53.136 0 53.16 0.084 ;
    END
  END o[242]
  PIN o[243]
    DIRECTION OUTPUT ;
    USE SIGNAL ;
    PORT
      LAYER M5 ;
        RECT  53.232 0 53.256 0.084 ;
    END
  END o[243]
  PIN o[244]
    DIRECTION OUTPUT ;
    USE SIGNAL ;
    PORT
      LAYER M5 ;
        RECT  53.328 0 53.352 0.084 ;
    END
  END o[244]
  PIN o[245]
    DIRECTION OUTPUT ;
    USE SIGNAL ;
    PORT
      LAYER M5 ;
        RECT  53.424 0 53.448 0.084 ;
    END
  END o[245]
  PIN o[246]
    DIRECTION OUTPUT ;
    USE SIGNAL ;
    PORT
      LAYER M5 ;
        RECT  53.52 0 53.544 0.084 ;
    END
  END o[246]
  PIN o[247]
    DIRECTION OUTPUT ;
    USE SIGNAL ;
    PORT
      LAYER M5 ;
        RECT  53.616 0 53.64 0.084 ;
    END
  END o[247]
  PIN o[248]
    DIRECTION OUTPUT ;
    USE SIGNAL ;
    PORT
      LAYER M5 ;
        RECT  53.712 0 53.736 0.084 ;
    END
  END o[248]
  PIN o[249]
    DIRECTION OUTPUT ;
    USE SIGNAL ;
    PORT
      LAYER M5 ;
        RECT  53.808 0 53.832 0.084 ;
    END
  END o[249]
  PIN o[24]
    DIRECTION OUTPUT ;
    USE SIGNAL ;
    PORT
      LAYER M5 ;
        RECT  37.584 0 37.608 0.084 ;
    END
  END o[24]
  PIN o[250]
    DIRECTION OUTPUT ;
    USE SIGNAL ;
    PORT
      LAYER M5 ;
        RECT  53.904 0 53.928 0.084 ;
    END
  END o[250]
  PIN o[251]
    DIRECTION OUTPUT ;
    USE SIGNAL ;
    PORT
      LAYER M5 ;
        RECT  54 0 54.024 0.084 ;
    END
  END o[251]
  PIN o[252]
    DIRECTION OUTPUT ;
    USE SIGNAL ;
    PORT
      LAYER M5 ;
        RECT  54.096 0 54.12 0.084 ;
    END
  END o[252]
  PIN o[253]
    DIRECTION OUTPUT ;
    USE SIGNAL ;
    PORT
      LAYER M5 ;
        RECT  54.192 0 54.216 0.084 ;
    END
  END o[253]
  PIN o[254]
    DIRECTION OUTPUT ;
    USE SIGNAL ;
    PORT
      LAYER M5 ;
        RECT  54.288 0 54.312 0.084 ;
    END
  END o[254]
  PIN o[255]
    DIRECTION OUTPUT ;
    USE SIGNAL ;
    PORT
      LAYER M5 ;
        RECT  54.384 0 54.408 0.084 ;
    END
  END o[255]
  PIN o[256]
    DIRECTION OUTPUT ;
    USE SIGNAL ;
    PORT
      LAYER M5 ;
        RECT  16.08 0 16.104 0.084 ;
    END
  END o[256]
  PIN o[257]
    DIRECTION OUTPUT ;
    USE SIGNAL ;
    PORT
      LAYER M5 ;
        RECT  16.176 0 16.2 0.084 ;
    END
  END o[257]
  PIN o[258]
    DIRECTION OUTPUT ;
    USE SIGNAL ;
    PORT
      LAYER M5 ;
        RECT  16.272 0 16.296 0.084 ;
    END
  END o[258]
  PIN o[259]
    DIRECTION OUTPUT ;
    USE SIGNAL ;
    PORT
      LAYER M5 ;
        RECT  16.368 0 16.392 0.084 ;
    END
  END o[259]
  PIN o[25]
    DIRECTION OUTPUT ;
    USE SIGNAL ;
    PORT
      LAYER M5 ;
        RECT  37.68 0 37.704 0.084 ;
    END
  END o[25]
  PIN o[260]
    DIRECTION OUTPUT ;
    USE SIGNAL ;
    PORT
      LAYER M5 ;
        RECT  16.464 0 16.488 0.084 ;
    END
  END o[260]
  PIN o[261]
    DIRECTION OUTPUT ;
    USE SIGNAL ;
    PORT
      LAYER M5 ;
        RECT  16.56 0 16.584 0.084 ;
    END
  END o[261]
  PIN o[262]
    DIRECTION OUTPUT ;
    USE SIGNAL ;
    PORT
      LAYER M5 ;
        RECT  16.656 0 16.68 0.084 ;
    END
  END o[262]
  PIN o[263]
    DIRECTION OUTPUT ;
    USE SIGNAL ;
    PORT
      LAYER M5 ;
        RECT  16.752 0 16.776 0.084 ;
    END
  END o[263]
  PIN o[264]
    DIRECTION OUTPUT ;
    USE SIGNAL ;
    PORT
      LAYER M5 ;
        RECT  16.848 0 16.872 0.084 ;
    END
  END o[264]
  PIN o[265]
    DIRECTION OUTPUT ;
    USE SIGNAL ;
    PORT
      LAYER M5 ;
        RECT  16.944 0 16.968 0.084 ;
    END
  END o[265]
  PIN o[266]
    DIRECTION OUTPUT ;
    USE SIGNAL ;
    PORT
      LAYER M5 ;
        RECT  17.04 0 17.064 0.084 ;
    END
  END o[266]
  PIN o[267]
    DIRECTION OUTPUT ;
    USE SIGNAL ;
    PORT
      LAYER M5 ;
        RECT  17.136 0 17.16 0.084 ;
    END
  END o[267]
  PIN o[268]
    DIRECTION OUTPUT ;
    USE SIGNAL ;
    PORT
      LAYER M5 ;
        RECT  17.232 0 17.256 0.084 ;
    END
  END o[268]
  PIN o[269]
    DIRECTION OUTPUT ;
    USE SIGNAL ;
    PORT
      LAYER M5 ;
        RECT  17.328 0 17.352 0.084 ;
    END
  END o[269]
  PIN o[26]
    DIRECTION OUTPUT ;
    USE SIGNAL ;
    PORT
      LAYER M5 ;
        RECT  37.776 0 37.8 0.084 ;
    END
  END o[26]
  PIN o[270]
    DIRECTION OUTPUT ;
    USE SIGNAL ;
    PORT
      LAYER M5 ;
        RECT  17.424 0 17.448 0.084 ;
    END
  END o[270]
  PIN o[271]
    DIRECTION OUTPUT ;
    USE SIGNAL ;
    PORT
      LAYER M5 ;
        RECT  17.52 0 17.544 0.084 ;
    END
  END o[271]
  PIN o[272]
    DIRECTION OUTPUT ;
    USE SIGNAL ;
    PORT
      LAYER M5 ;
        RECT  17.616 0 17.64 0.084 ;
    END
  END o[272]
  PIN o[273]
    DIRECTION OUTPUT ;
    USE SIGNAL ;
    PORT
      LAYER M5 ;
        RECT  17.712 0 17.736 0.084 ;
    END
  END o[273]
  PIN o[274]
    DIRECTION OUTPUT ;
    USE SIGNAL ;
    PORT
      LAYER M5 ;
        RECT  17.808 0 17.832 0.084 ;
    END
  END o[274]
  PIN o[275]
    DIRECTION OUTPUT ;
    USE SIGNAL ;
    PORT
      LAYER M5 ;
        RECT  17.904 0 17.928 0.084 ;
    END
  END o[275]
  PIN o[276]
    DIRECTION OUTPUT ;
    USE SIGNAL ;
    PORT
      LAYER M5 ;
        RECT  18 0 18.024 0.084 ;
    END
  END o[276]
  PIN o[277]
    DIRECTION OUTPUT ;
    USE SIGNAL ;
    PORT
      LAYER M5 ;
        RECT  18.096 0 18.12 0.084 ;
    END
  END o[277]
  PIN o[278]
    DIRECTION OUTPUT ;
    USE SIGNAL ;
    PORT
      LAYER M5 ;
        RECT  18.192 0 18.216 0.084 ;
    END
  END o[278]
  PIN o[279]
    DIRECTION OUTPUT ;
    USE SIGNAL ;
    PORT
      LAYER M5 ;
        RECT  18.288 0 18.312 0.084 ;
    END
  END o[279]
  PIN o[27]
    DIRECTION OUTPUT ;
    USE SIGNAL ;
    PORT
      LAYER M5 ;
        RECT  37.872 0 37.896 0.084 ;
    END
  END o[27]
  PIN o[280]
    DIRECTION OUTPUT ;
    USE SIGNAL ;
    PORT
      LAYER M5 ;
        RECT  18.384 0 18.408 0.084 ;
    END
  END o[280]
  PIN o[281]
    DIRECTION OUTPUT ;
    USE SIGNAL ;
    PORT
      LAYER M5 ;
        RECT  18.48 0 18.504 0.084 ;
    END
  END o[281]
  PIN o[282]
    DIRECTION OUTPUT ;
    USE SIGNAL ;
    PORT
      LAYER M5 ;
        RECT  18.576 0 18.6 0.084 ;
    END
  END o[282]
  PIN o[283]
    DIRECTION OUTPUT ;
    USE SIGNAL ;
    PORT
      LAYER M5 ;
        RECT  18.672 0 18.696 0.084 ;
    END
  END o[283]
  PIN o[284]
    DIRECTION OUTPUT ;
    USE SIGNAL ;
    PORT
      LAYER M5 ;
        RECT  18.768 0 18.792 0.084 ;
    END
  END o[284]
  PIN o[285]
    DIRECTION OUTPUT ;
    USE SIGNAL ;
    PORT
      LAYER M5 ;
        RECT  18.864 0 18.888 0.084 ;
    END
  END o[285]
  PIN o[286]
    DIRECTION OUTPUT ;
    USE SIGNAL ;
    PORT
      LAYER M5 ;
        RECT  18.96 0 18.984 0.084 ;
    END
  END o[286]
  PIN o[287]
    DIRECTION OUTPUT ;
    USE SIGNAL ;
    PORT
      LAYER M5 ;
        RECT  19.056 0 19.08 0.084 ;
    END
  END o[287]
  PIN o[288]
    DIRECTION OUTPUT ;
    USE SIGNAL ;
    PORT
      LAYER M5 ;
        RECT  13.008 0 13.032 0.084 ;
    END
  END o[288]
  PIN o[289]
    DIRECTION OUTPUT ;
    USE SIGNAL ;
    PORT
      LAYER M5 ;
        RECT  13.104 0 13.128 0.084 ;
    END
  END o[289]
  PIN o[28]
    DIRECTION OUTPUT ;
    USE SIGNAL ;
    PORT
      LAYER M5 ;
        RECT  37.968 0 37.992 0.084 ;
    END
  END o[28]
  PIN o[290]
    DIRECTION OUTPUT ;
    USE SIGNAL ;
    PORT
      LAYER M5 ;
        RECT  13.2 0 13.224 0.084 ;
    END
  END o[290]
  PIN o[291]
    DIRECTION OUTPUT ;
    USE SIGNAL ;
    PORT
      LAYER M5 ;
        RECT  13.296 0 13.32 0.084 ;
    END
  END o[291]
  PIN o[292]
    DIRECTION OUTPUT ;
    USE SIGNAL ;
    PORT
      LAYER M5 ;
        RECT  13.392 0 13.416 0.084 ;
    END
  END o[292]
  PIN o[293]
    DIRECTION OUTPUT ;
    USE SIGNAL ;
    PORT
      LAYER M5 ;
        RECT  13.488 0 13.512 0.084 ;
    END
  END o[293]
  PIN o[294]
    DIRECTION OUTPUT ;
    USE SIGNAL ;
    PORT
      LAYER M5 ;
        RECT  13.584 0 13.608 0.084 ;
    END
  END o[294]
  PIN o[295]
    DIRECTION OUTPUT ;
    USE SIGNAL ;
    PORT
      LAYER M5 ;
        RECT  13.68 0 13.704 0.084 ;
    END
  END o[295]
  PIN o[296]
    DIRECTION OUTPUT ;
    USE SIGNAL ;
    PORT
      LAYER M5 ;
        RECT  13.776 0 13.8 0.084 ;
    END
  END o[296]
  PIN o[297]
    DIRECTION OUTPUT ;
    USE SIGNAL ;
    PORT
      LAYER M5 ;
        RECT  13.872 0 13.896 0.084 ;
    END
  END o[297]
  PIN o[298]
    DIRECTION OUTPUT ;
    USE SIGNAL ;
    PORT
      LAYER M5 ;
        RECT  13.968 0 13.992 0.084 ;
    END
  END o[298]
  PIN o[299]
    DIRECTION OUTPUT ;
    USE SIGNAL ;
    PORT
      LAYER M5 ;
        RECT  14.064 0 14.088 0.084 ;
    END
  END o[299]
  PIN o[29]
    DIRECTION OUTPUT ;
    USE SIGNAL ;
    PORT
      LAYER M5 ;
        RECT  38.064 0 38.088 0.084 ;
    END
  END o[29]
  PIN o[2]
    DIRECTION OUTPUT ;
    USE SIGNAL ;
    PORT
      LAYER M5 ;
        RECT  35.472 0 35.496 0.084 ;
    END
  END o[2]
  PIN o[300]
    DIRECTION OUTPUT ;
    USE SIGNAL ;
    PORT
      LAYER M5 ;
        RECT  14.16 0 14.184 0.084 ;
    END
  END o[300]
  PIN o[301]
    DIRECTION OUTPUT ;
    USE SIGNAL ;
    PORT
      LAYER M5 ;
        RECT  14.256 0 14.28 0.084 ;
    END
  END o[301]
  PIN o[302]
    DIRECTION OUTPUT ;
    USE SIGNAL ;
    PORT
      LAYER M5 ;
        RECT  14.352 0 14.376 0.084 ;
    END
  END o[302]
  PIN o[303]
    DIRECTION OUTPUT ;
    USE SIGNAL ;
    PORT
      LAYER M5 ;
        RECT  14.448 0 14.472 0.084 ;
    END
  END o[303]
  PIN o[304]
    DIRECTION OUTPUT ;
    USE SIGNAL ;
    PORT
      LAYER M5 ;
        RECT  14.544 0 14.568 0.084 ;
    END
  END o[304]
  PIN o[305]
    DIRECTION OUTPUT ;
    USE SIGNAL ;
    PORT
      LAYER M5 ;
        RECT  14.64 0 14.664 0.084 ;
    END
  END o[305]
  PIN o[306]
    DIRECTION OUTPUT ;
    USE SIGNAL ;
    PORT
      LAYER M5 ;
        RECT  14.736 0 14.76 0.084 ;
    END
  END o[306]
  PIN o[307]
    DIRECTION OUTPUT ;
    USE SIGNAL ;
    PORT
      LAYER M5 ;
        RECT  14.832 0 14.856 0.084 ;
    END
  END o[307]
  PIN o[308]
    DIRECTION OUTPUT ;
    USE SIGNAL ;
    PORT
      LAYER M5 ;
        RECT  14.928 0 14.952 0.084 ;
    END
  END o[308]
  PIN o[309]
    DIRECTION OUTPUT ;
    USE SIGNAL ;
    PORT
      LAYER M5 ;
        RECT  15.024 0 15.048 0.084 ;
    END
  END o[309]
  PIN o[30]
    DIRECTION OUTPUT ;
    USE SIGNAL ;
    PORT
      LAYER M5 ;
        RECT  38.16 0 38.184 0.084 ;
    END
  END o[30]
  PIN o[310]
    DIRECTION OUTPUT ;
    USE SIGNAL ;
    PORT
      LAYER M5 ;
        RECT  15.12 0 15.144 0.084 ;
    END
  END o[310]
  PIN o[311]
    DIRECTION OUTPUT ;
    USE SIGNAL ;
    PORT
      LAYER M5 ;
        RECT  15.216 0 15.24 0.084 ;
    END
  END o[311]
  PIN o[312]
    DIRECTION OUTPUT ;
    USE SIGNAL ;
    PORT
      LAYER M5 ;
        RECT  15.312 0 15.336 0.084 ;
    END
  END o[312]
  PIN o[313]
    DIRECTION OUTPUT ;
    USE SIGNAL ;
    PORT
      LAYER M5 ;
        RECT  15.408 0 15.432 0.084 ;
    END
  END o[313]
  PIN o[314]
    DIRECTION OUTPUT ;
    USE SIGNAL ;
    PORT
      LAYER M5 ;
        RECT  15.504 0 15.528 0.084 ;
    END
  END o[314]
  PIN o[315]
    DIRECTION OUTPUT ;
    USE SIGNAL ;
    PORT
      LAYER M5 ;
        RECT  15.6 0 15.624 0.084 ;
    END
  END o[315]
  PIN o[316]
    DIRECTION OUTPUT ;
    USE SIGNAL ;
    PORT
      LAYER M5 ;
        RECT  15.696 0 15.72 0.084 ;
    END
  END o[316]
  PIN o[317]
    DIRECTION OUTPUT ;
    USE SIGNAL ;
    PORT
      LAYER M5 ;
        RECT  15.792 0 15.816 0.084 ;
    END
  END o[317]
  PIN o[318]
    DIRECTION OUTPUT ;
    USE SIGNAL ;
    PORT
      LAYER M5 ;
        RECT  15.888 0 15.912 0.084 ;
    END
  END o[318]
  PIN o[319]
    DIRECTION OUTPUT ;
    USE SIGNAL ;
    PORT
      LAYER M5 ;
        RECT  15.984 0 16.008 0.084 ;
    END
  END o[319]
  PIN o[31]
    DIRECTION OUTPUT ;
    USE SIGNAL ;
    PORT
      LAYER M5 ;
        RECT  38.256 0 38.28 0.084 ;
    END
  END o[31]
  PIN o[320]
    DIRECTION OUTPUT ;
    USE SIGNAL ;
    PORT
      LAYER M5 ;
        RECT  0.72 0 0.744 0.084 ;
    END
  END o[320]
  PIN o[321]
    DIRECTION OUTPUT ;
    USE SIGNAL ;
    PORT
      LAYER M5 ;
        RECT  0.816 0 0.84 0.084 ;
    END
  END o[321]
  PIN o[322]
    DIRECTION OUTPUT ;
    USE SIGNAL ;
    PORT
      LAYER M5 ;
        RECT  0.912 0 0.936 0.084 ;
    END
  END o[322]
  PIN o[323]
    DIRECTION OUTPUT ;
    USE SIGNAL ;
    PORT
      LAYER M5 ;
        RECT  1.008 0 1.032 0.084 ;
    END
  END o[323]
  PIN o[324]
    DIRECTION OUTPUT ;
    USE SIGNAL ;
    PORT
      LAYER M5 ;
        RECT  1.104 0 1.128 0.084 ;
    END
  END o[324]
  PIN o[325]
    DIRECTION OUTPUT ;
    USE SIGNAL ;
    PORT
      LAYER M5 ;
        RECT  1.2 0 1.224 0.084 ;
    END
  END o[325]
  PIN o[326]
    DIRECTION OUTPUT ;
    USE SIGNAL ;
    PORT
      LAYER M5 ;
        RECT  1.296 0 1.32 0.084 ;
    END
  END o[326]
  PIN o[327]
    DIRECTION OUTPUT ;
    USE SIGNAL ;
    PORT
      LAYER M5 ;
        RECT  1.392 0 1.416 0.084 ;
    END
  END o[327]
  PIN o[328]
    DIRECTION OUTPUT ;
    USE SIGNAL ;
    PORT
      LAYER M5 ;
        RECT  1.488 0 1.512 0.084 ;
    END
  END o[328]
  PIN o[329]
    DIRECTION OUTPUT ;
    USE SIGNAL ;
    PORT
      LAYER M5 ;
        RECT  1.584 0 1.608 0.084 ;
    END
  END o[329]
  PIN o[32]
    DIRECTION OUTPUT ;
    USE SIGNAL ;
    PORT
      LAYER M5 ;
        RECT  26.064 0 26.088 0.084 ;
    END
  END o[32]
  PIN o[330]
    DIRECTION OUTPUT ;
    USE SIGNAL ;
    PORT
      LAYER M5 ;
        RECT  1.68 0 1.704 0.084 ;
    END
  END o[330]
  PIN o[331]
    DIRECTION OUTPUT ;
    USE SIGNAL ;
    PORT
      LAYER M5 ;
        RECT  1.776 0 1.8 0.084 ;
    END
  END o[331]
  PIN o[332]
    DIRECTION OUTPUT ;
    USE SIGNAL ;
    PORT
      LAYER M5 ;
        RECT  1.872 0 1.896 0.084 ;
    END
  END o[332]
  PIN o[333]
    DIRECTION OUTPUT ;
    USE SIGNAL ;
    PORT
      LAYER M5 ;
        RECT  1.968 0 1.992 0.084 ;
    END
  END o[333]
  PIN o[334]
    DIRECTION OUTPUT ;
    USE SIGNAL ;
    PORT
      LAYER M5 ;
        RECT  2.064 0 2.088 0.084 ;
    END
  END o[334]
  PIN o[335]
    DIRECTION OUTPUT ;
    USE SIGNAL ;
    PORT
      LAYER M5 ;
        RECT  2.16 0 2.184 0.084 ;
    END
  END o[335]
  PIN o[336]
    DIRECTION OUTPUT ;
    USE SIGNAL ;
    PORT
      LAYER M5 ;
        RECT  2.256 0 2.28 0.084 ;
    END
  END o[336]
  PIN o[337]
    DIRECTION OUTPUT ;
    USE SIGNAL ;
    PORT
      LAYER M5 ;
        RECT  2.352 0 2.376 0.084 ;
    END
  END o[337]
  PIN o[338]
    DIRECTION OUTPUT ;
    USE SIGNAL ;
    PORT
      LAYER M5 ;
        RECT  2.448 0 2.472 0.084 ;
    END
  END o[338]
  PIN o[339]
    DIRECTION OUTPUT ;
    USE SIGNAL ;
    PORT
      LAYER M5 ;
        RECT  2.544 0 2.568 0.084 ;
    END
  END o[339]
  PIN o[33]
    DIRECTION OUTPUT ;
    USE SIGNAL ;
    PORT
      LAYER M5 ;
        RECT  26.16 0 26.184 0.084 ;
    END
  END o[33]
  PIN o[340]
    DIRECTION OUTPUT ;
    USE SIGNAL ;
    PORT
      LAYER M5 ;
        RECT  2.64 0 2.664 0.084 ;
    END
  END o[340]
  PIN o[341]
    DIRECTION OUTPUT ;
    USE SIGNAL ;
    PORT
      LAYER M5 ;
        RECT  2.736 0 2.76 0.084 ;
    END
  END o[341]
  PIN o[342]
    DIRECTION OUTPUT ;
    USE SIGNAL ;
    PORT
      LAYER M5 ;
        RECT  2.832 0 2.856 0.084 ;
    END
  END o[342]
  PIN o[343]
    DIRECTION OUTPUT ;
    USE SIGNAL ;
    PORT
      LAYER M5 ;
        RECT  2.928 0 2.952 0.084 ;
    END
  END o[343]
  PIN o[344]
    DIRECTION OUTPUT ;
    USE SIGNAL ;
    PORT
      LAYER M5 ;
        RECT  3.024 0 3.048 0.084 ;
    END
  END o[344]
  PIN o[345]
    DIRECTION OUTPUT ;
    USE SIGNAL ;
    PORT
      LAYER M5 ;
        RECT  3.12 0 3.144 0.084 ;
    END
  END o[345]
  PIN o[346]
    DIRECTION OUTPUT ;
    USE SIGNAL ;
    PORT
      LAYER M5 ;
        RECT  3.216 0 3.24 0.084 ;
    END
  END o[346]
  PIN o[347]
    DIRECTION OUTPUT ;
    USE SIGNAL ;
    PORT
      LAYER M5 ;
        RECT  3.312 0 3.336 0.084 ;
    END
  END o[347]
  PIN o[348]
    DIRECTION OUTPUT ;
    USE SIGNAL ;
    PORT
      LAYER M5 ;
        RECT  3.408 0 3.432 0.084 ;
    END
  END o[348]
  PIN o[349]
    DIRECTION OUTPUT ;
    USE SIGNAL ;
    PORT
      LAYER M5 ;
        RECT  3.504 0 3.528 0.084 ;
    END
  END o[349]
  PIN o[34]
    DIRECTION OUTPUT ;
    USE SIGNAL ;
    PORT
      LAYER M5 ;
        RECT  26.256 0 26.28 0.084 ;
    END
  END o[34]
  PIN o[350]
    DIRECTION OUTPUT ;
    USE SIGNAL ;
    PORT
      LAYER M5 ;
        RECT  3.6 0 3.624 0.084 ;
    END
  END o[350]
  PIN o[351]
    DIRECTION OUTPUT ;
    USE SIGNAL ;
    PORT
      LAYER M5 ;
        RECT  3.696 0 3.72 0.084 ;
    END
  END o[351]
  PIN o[352]
    DIRECTION OUTPUT ;
    USE SIGNAL ;
    PORT
      LAYER M5 ;
        RECT  42.192 0 42.216 0.084 ;
    END
  END o[352]
  PIN o[353]
    DIRECTION OUTPUT ;
    USE SIGNAL ;
    PORT
      LAYER M5 ;
        RECT  42.288 0 42.312 0.084 ;
    END
  END o[353]
  PIN o[354]
    DIRECTION OUTPUT ;
    USE SIGNAL ;
    PORT
      LAYER M5 ;
        RECT  42.384 0 42.408 0.084 ;
    END
  END o[354]
  PIN o[355]
    DIRECTION OUTPUT ;
    USE SIGNAL ;
    PORT
      LAYER M5 ;
        RECT  42.48 0 42.504 0.084 ;
    END
  END o[355]
  PIN o[356]
    DIRECTION OUTPUT ;
    USE SIGNAL ;
    PORT
      LAYER M5 ;
        RECT  42.576 0 42.6 0.084 ;
    END
  END o[356]
  PIN o[357]
    DIRECTION OUTPUT ;
    USE SIGNAL ;
    PORT
      LAYER M5 ;
        RECT  42.672 0 42.696 0.084 ;
    END
  END o[357]
  PIN o[358]
    DIRECTION OUTPUT ;
    USE SIGNAL ;
    PORT
      LAYER M5 ;
        RECT  42.768 0 42.792 0.084 ;
    END
  END o[358]
  PIN o[359]
    DIRECTION OUTPUT ;
    USE SIGNAL ;
    PORT
      LAYER M5 ;
        RECT  42.864 0 42.888 0.084 ;
    END
  END o[359]
  PIN o[35]
    DIRECTION OUTPUT ;
    USE SIGNAL ;
    PORT
      LAYER M5 ;
        RECT  26.352 0 26.376 0.084 ;
    END
  END o[35]
  PIN o[360]
    DIRECTION OUTPUT ;
    USE SIGNAL ;
    PORT
      LAYER M5 ;
        RECT  42.96 0 42.984 0.084 ;
    END
  END o[360]
  PIN o[361]
    DIRECTION OUTPUT ;
    USE SIGNAL ;
    PORT
      LAYER M5 ;
        RECT  43.056 0 43.08 0.084 ;
    END
  END o[361]
  PIN o[362]
    DIRECTION OUTPUT ;
    USE SIGNAL ;
    PORT
      LAYER M5 ;
        RECT  43.152 0 43.176 0.084 ;
    END
  END o[362]
  PIN o[363]
    DIRECTION OUTPUT ;
    USE SIGNAL ;
    PORT
      LAYER M5 ;
        RECT  43.248 0 43.272 0.084 ;
    END
  END o[363]
  PIN o[364]
    DIRECTION OUTPUT ;
    USE SIGNAL ;
    PORT
      LAYER M5 ;
        RECT  43.344 0 43.368 0.084 ;
    END
  END o[364]
  PIN o[365]
    DIRECTION OUTPUT ;
    USE SIGNAL ;
    PORT
      LAYER M5 ;
        RECT  43.44 0 43.464 0.084 ;
    END
  END o[365]
  PIN o[366]
    DIRECTION OUTPUT ;
    USE SIGNAL ;
    PORT
      LAYER M5 ;
        RECT  43.536 0 43.56 0.084 ;
    END
  END o[366]
  PIN o[367]
    DIRECTION OUTPUT ;
    USE SIGNAL ;
    PORT
      LAYER M5 ;
        RECT  43.632 0 43.656 0.084 ;
    END
  END o[367]
  PIN o[368]
    DIRECTION OUTPUT ;
    USE SIGNAL ;
    PORT
      LAYER M5 ;
        RECT  43.728 0 43.752 0.084 ;
    END
  END o[368]
  PIN o[369]
    DIRECTION OUTPUT ;
    USE SIGNAL ;
    PORT
      LAYER M5 ;
        RECT  43.824 0 43.848 0.084 ;
    END
  END o[369]
  PIN o[36]
    DIRECTION OUTPUT ;
    USE SIGNAL ;
    PORT
      LAYER M5 ;
        RECT  26.448 0 26.472 0.084 ;
    END
  END o[36]
  PIN o[370]
    DIRECTION OUTPUT ;
    USE SIGNAL ;
    PORT
      LAYER M5 ;
        RECT  43.92 0 43.944 0.084 ;
    END
  END o[370]
  PIN o[371]
    DIRECTION OUTPUT ;
    USE SIGNAL ;
    PORT
      LAYER M5 ;
        RECT  44.016 0 44.04 0.084 ;
    END
  END o[371]
  PIN o[372]
    DIRECTION OUTPUT ;
    USE SIGNAL ;
    PORT
      LAYER M5 ;
        RECT  44.112 0 44.136 0.084 ;
    END
  END o[372]
  PIN o[373]
    DIRECTION OUTPUT ;
    USE SIGNAL ;
    PORT
      LAYER M5 ;
        RECT  44.208 0 44.232 0.084 ;
    END
  END o[373]
  PIN o[374]
    DIRECTION OUTPUT ;
    USE SIGNAL ;
    PORT
      LAYER M5 ;
        RECT  44.304 0 44.328 0.084 ;
    END
  END o[374]
  PIN o[375]
    DIRECTION OUTPUT ;
    USE SIGNAL ;
    PORT
      LAYER M5 ;
        RECT  44.4 0 44.424 0.084 ;
    END
  END o[375]
  PIN o[376]
    DIRECTION OUTPUT ;
    USE SIGNAL ;
    PORT
      LAYER M5 ;
        RECT  44.496 0 44.52 0.084 ;
    END
  END o[376]
  PIN o[377]
    DIRECTION OUTPUT ;
    USE SIGNAL ;
    PORT
      LAYER M5 ;
        RECT  44.592 0 44.616 0.084 ;
    END
  END o[377]
  PIN o[378]
    DIRECTION OUTPUT ;
    USE SIGNAL ;
    PORT
      LAYER M5 ;
        RECT  44.688 0 44.712 0.084 ;
    END
  END o[378]
  PIN o[379]
    DIRECTION OUTPUT ;
    USE SIGNAL ;
    PORT
      LAYER M5 ;
        RECT  44.784 0 44.808 0.084 ;
    END
  END o[379]
  PIN o[37]
    DIRECTION OUTPUT ;
    USE SIGNAL ;
    PORT
      LAYER M5 ;
        RECT  26.544 0 26.568 0.084 ;
    END
  END o[37]
  PIN o[380]
    DIRECTION OUTPUT ;
    USE SIGNAL ;
    PORT
      LAYER M5 ;
        RECT  44.88 0 44.904 0.084 ;
    END
  END o[380]
  PIN o[381]
    DIRECTION OUTPUT ;
    USE SIGNAL ;
    PORT
      LAYER M5 ;
        RECT  44.976 0 45 0.084 ;
    END
  END o[381]
  PIN o[382]
    DIRECTION OUTPUT ;
    USE SIGNAL ;
    PORT
      LAYER M5 ;
        RECT  45.072 0 45.096 0.084 ;
    END
  END o[382]
  PIN o[383]
    DIRECTION OUTPUT ;
    USE SIGNAL ;
    PORT
      LAYER M5 ;
        RECT  45.168 0 45.192 0.084 ;
    END
  END o[383]
  PIN o[384]
    DIRECTION OUTPUT ;
    USE SIGNAL ;
    PORT
      LAYER M5 ;
        RECT  9.936 0 9.96 0.084 ;
    END
  END o[384]
  PIN o[385]
    DIRECTION OUTPUT ;
    USE SIGNAL ;
    PORT
      LAYER M5 ;
        RECT  10.032 0 10.056 0.084 ;
    END
  END o[385]
  PIN o[386]
    DIRECTION OUTPUT ;
    USE SIGNAL ;
    PORT
      LAYER M5 ;
        RECT  10.128 0 10.152 0.084 ;
    END
  END o[386]
  PIN o[387]
    DIRECTION OUTPUT ;
    USE SIGNAL ;
    PORT
      LAYER M5 ;
        RECT  10.224 0 10.248 0.084 ;
    END
  END o[387]
  PIN o[388]
    DIRECTION OUTPUT ;
    USE SIGNAL ;
    PORT
      LAYER M5 ;
        RECT  10.32 0 10.344 0.084 ;
    END
  END o[388]
  PIN o[389]
    DIRECTION OUTPUT ;
    USE SIGNAL ;
    PORT
      LAYER M5 ;
        RECT  10.416 0 10.44 0.084 ;
    END
  END o[389]
  PIN o[38]
    DIRECTION OUTPUT ;
    USE SIGNAL ;
    PORT
      LAYER M5 ;
        RECT  26.64 0 26.664 0.084 ;
    END
  END o[38]
  PIN o[390]
    DIRECTION OUTPUT ;
    USE SIGNAL ;
    PORT
      LAYER M5 ;
        RECT  10.512 0 10.536 0.084 ;
    END
  END o[390]
  PIN o[391]
    DIRECTION OUTPUT ;
    USE SIGNAL ;
    PORT
      LAYER M5 ;
        RECT  10.608 0 10.632 0.084 ;
    END
  END o[391]
  PIN o[392]
    DIRECTION OUTPUT ;
    USE SIGNAL ;
    PORT
      LAYER M5 ;
        RECT  10.704 0 10.728 0.084 ;
    END
  END o[392]
  PIN o[393]
    DIRECTION OUTPUT ;
    USE SIGNAL ;
    PORT
      LAYER M5 ;
        RECT  10.8 0 10.824 0.084 ;
    END
  END o[393]
  PIN o[394]
    DIRECTION OUTPUT ;
    USE SIGNAL ;
    PORT
      LAYER M5 ;
        RECT  10.896 0 10.92 0.084 ;
    END
  END o[394]
  PIN o[395]
    DIRECTION OUTPUT ;
    USE SIGNAL ;
    PORT
      LAYER M5 ;
        RECT  10.992 0 11.016 0.084 ;
    END
  END o[395]
  PIN o[396]
    DIRECTION OUTPUT ;
    USE SIGNAL ;
    PORT
      LAYER M5 ;
        RECT  11.088 0 11.112 0.084 ;
    END
  END o[396]
  PIN o[397]
    DIRECTION OUTPUT ;
    USE SIGNAL ;
    PORT
      LAYER M5 ;
        RECT  11.184 0 11.208 0.084 ;
    END
  END o[397]
  PIN o[398]
    DIRECTION OUTPUT ;
    USE SIGNAL ;
    PORT
      LAYER M5 ;
        RECT  11.28 0 11.304 0.084 ;
    END
  END o[398]
  PIN o[399]
    DIRECTION OUTPUT ;
    USE SIGNAL ;
    PORT
      LAYER M5 ;
        RECT  11.376 0 11.4 0.084 ;
    END
  END o[399]
  PIN o[39]
    DIRECTION OUTPUT ;
    USE SIGNAL ;
    PORT
      LAYER M5 ;
        RECT  26.736 0 26.76 0.084 ;
    END
  END o[39]
  PIN o[3]
    DIRECTION OUTPUT ;
    USE SIGNAL ;
    PORT
      LAYER M5 ;
        RECT  35.568 0 35.592 0.084 ;
    END
  END o[3]
  PIN o[400]
    DIRECTION OUTPUT ;
    USE SIGNAL ;
    PORT
      LAYER M5 ;
        RECT  11.472 0 11.496 0.084 ;
    END
  END o[400]
  PIN o[401]
    DIRECTION OUTPUT ;
    USE SIGNAL ;
    PORT
      LAYER M5 ;
        RECT  11.568 0 11.592 0.084 ;
    END
  END o[401]
  PIN o[402]
    DIRECTION OUTPUT ;
    USE SIGNAL ;
    PORT
      LAYER M5 ;
        RECT  11.664 0 11.688 0.084 ;
    END
  END o[402]
  PIN o[403]
    DIRECTION OUTPUT ;
    USE SIGNAL ;
    PORT
      LAYER M5 ;
        RECT  11.76 0 11.784 0.084 ;
    END
  END o[403]
  PIN o[404]
    DIRECTION OUTPUT ;
    USE SIGNAL ;
    PORT
      LAYER M5 ;
        RECT  11.856 0 11.88 0.084 ;
    END
  END o[404]
  PIN o[405]
    DIRECTION OUTPUT ;
    USE SIGNAL ;
    PORT
      LAYER M5 ;
        RECT  11.952 0 11.976 0.084 ;
    END
  END o[405]
  PIN o[406]
    DIRECTION OUTPUT ;
    USE SIGNAL ;
    PORT
      LAYER M5 ;
        RECT  12.048 0 12.072 0.084 ;
    END
  END o[406]
  PIN o[407]
    DIRECTION OUTPUT ;
    USE SIGNAL ;
    PORT
      LAYER M5 ;
        RECT  12.144 0 12.168 0.084 ;
    END
  END o[407]
  PIN o[408]
    DIRECTION OUTPUT ;
    USE SIGNAL ;
    PORT
      LAYER M5 ;
        RECT  12.24 0 12.264 0.084 ;
    END
  END o[408]
  PIN o[409]
    DIRECTION OUTPUT ;
    USE SIGNAL ;
    PORT
      LAYER M5 ;
        RECT  12.336 0 12.36 0.084 ;
    END
  END o[409]
  PIN o[40]
    DIRECTION OUTPUT ;
    USE SIGNAL ;
    PORT
      LAYER M5 ;
        RECT  26.832 0 26.856 0.084 ;
    END
  END o[40]
  PIN o[410]
    DIRECTION OUTPUT ;
    USE SIGNAL ;
    PORT
      LAYER M5 ;
        RECT  12.432 0 12.456 0.084 ;
    END
  END o[410]
  PIN o[411]
    DIRECTION OUTPUT ;
    USE SIGNAL ;
    PORT
      LAYER M5 ;
        RECT  12.528 0 12.552 0.084 ;
    END
  END o[411]
  PIN o[412]
    DIRECTION OUTPUT ;
    USE SIGNAL ;
    PORT
      LAYER M5 ;
        RECT  12.624 0 12.648 0.084 ;
    END
  END o[412]
  PIN o[413]
    DIRECTION OUTPUT ;
    USE SIGNAL ;
    PORT
      LAYER M5 ;
        RECT  12.72 0 12.744 0.084 ;
    END
  END o[413]
  PIN o[414]
    DIRECTION OUTPUT ;
    USE SIGNAL ;
    PORT
      LAYER M5 ;
        RECT  12.816 0 12.84 0.084 ;
    END
  END o[414]
  PIN o[415]
    DIRECTION OUTPUT ;
    USE SIGNAL ;
    PORT
      LAYER M5 ;
        RECT  12.912 0 12.936 0.084 ;
    END
  END o[415]
  PIN o[416]
    DIRECTION OUTPUT ;
    USE SIGNAL ;
    PORT
      LAYER M5 ;
        RECT  6.864 0 6.888 0.084 ;
    END
  END o[416]
  PIN o[417]
    DIRECTION OUTPUT ;
    USE SIGNAL ;
    PORT
      LAYER M5 ;
        RECT  6.96 0 6.984 0.084 ;
    END
  END o[417]
  PIN o[418]
    DIRECTION OUTPUT ;
    USE SIGNAL ;
    PORT
      LAYER M5 ;
        RECT  7.056 0 7.08 0.084 ;
    END
  END o[418]
  PIN o[419]
    DIRECTION OUTPUT ;
    USE SIGNAL ;
    PORT
      LAYER M5 ;
        RECT  7.152 0 7.176 0.084 ;
    END
  END o[419]
  PIN o[41]
    DIRECTION OUTPUT ;
    USE SIGNAL ;
    PORT
      LAYER M5 ;
        RECT  26.928 0 26.952 0.084 ;
    END
  END o[41]
  PIN o[420]
    DIRECTION OUTPUT ;
    USE SIGNAL ;
    PORT
      LAYER M5 ;
        RECT  7.248 0 7.272 0.084 ;
    END
  END o[420]
  PIN o[421]
    DIRECTION OUTPUT ;
    USE SIGNAL ;
    PORT
      LAYER M5 ;
        RECT  7.344 0 7.368 0.084 ;
    END
  END o[421]
  PIN o[422]
    DIRECTION OUTPUT ;
    USE SIGNAL ;
    PORT
      LAYER M5 ;
        RECT  7.44 0 7.464 0.084 ;
    END
  END o[422]
  PIN o[423]
    DIRECTION OUTPUT ;
    USE SIGNAL ;
    PORT
      LAYER M5 ;
        RECT  7.536 0 7.56 0.084 ;
    END
  END o[423]
  PIN o[424]
    DIRECTION OUTPUT ;
    USE SIGNAL ;
    PORT
      LAYER M5 ;
        RECT  7.632 0 7.656 0.084 ;
    END
  END o[424]
  PIN o[425]
    DIRECTION OUTPUT ;
    USE SIGNAL ;
    PORT
      LAYER M5 ;
        RECT  7.728 0 7.752 0.084 ;
    END
  END o[425]
  PIN o[426]
    DIRECTION OUTPUT ;
    USE SIGNAL ;
    PORT
      LAYER M5 ;
        RECT  7.824 0 7.848 0.084 ;
    END
  END o[426]
  PIN o[427]
    DIRECTION OUTPUT ;
    USE SIGNAL ;
    PORT
      LAYER M5 ;
        RECT  7.92 0 7.944 0.084 ;
    END
  END o[427]
  PIN o[428]
    DIRECTION OUTPUT ;
    USE SIGNAL ;
    PORT
      LAYER M5 ;
        RECT  8.016 0 8.04 0.084 ;
    END
  END o[428]
  PIN o[429]
    DIRECTION OUTPUT ;
    USE SIGNAL ;
    PORT
      LAYER M5 ;
        RECT  8.112 0 8.136 0.084 ;
    END
  END o[429]
  PIN o[42]
    DIRECTION OUTPUT ;
    USE SIGNAL ;
    PORT
      LAYER M5 ;
        RECT  27.024 0 27.048 0.084 ;
    END
  END o[42]
  PIN o[430]
    DIRECTION OUTPUT ;
    USE SIGNAL ;
    PORT
      LAYER M5 ;
        RECT  8.208 0 8.232 0.084 ;
    END
  END o[430]
  PIN o[431]
    DIRECTION OUTPUT ;
    USE SIGNAL ;
    PORT
      LAYER M5 ;
        RECT  8.304 0 8.328 0.084 ;
    END
  END o[431]
  PIN o[432]
    DIRECTION OUTPUT ;
    USE SIGNAL ;
    PORT
      LAYER M5 ;
        RECT  8.4 0 8.424 0.084 ;
    END
  END o[432]
  PIN o[433]
    DIRECTION OUTPUT ;
    USE SIGNAL ;
    PORT
      LAYER M5 ;
        RECT  8.496 0 8.52 0.084 ;
    END
  END o[433]
  PIN o[434]
    DIRECTION OUTPUT ;
    USE SIGNAL ;
    PORT
      LAYER M5 ;
        RECT  8.592 0 8.616 0.084 ;
    END
  END o[434]
  PIN o[435]
    DIRECTION OUTPUT ;
    USE SIGNAL ;
    PORT
      LAYER M5 ;
        RECT  8.688 0 8.712 0.084 ;
    END
  END o[435]
  PIN o[436]
    DIRECTION OUTPUT ;
    USE SIGNAL ;
    PORT
      LAYER M5 ;
        RECT  8.784 0 8.808 0.084 ;
    END
  END o[436]
  PIN o[437]
    DIRECTION OUTPUT ;
    USE SIGNAL ;
    PORT
      LAYER M5 ;
        RECT  8.88 0 8.904 0.084 ;
    END
  END o[437]
  PIN o[438]
    DIRECTION OUTPUT ;
    USE SIGNAL ;
    PORT
      LAYER M5 ;
        RECT  8.976 0 9 0.084 ;
    END
  END o[438]
  PIN o[439]
    DIRECTION OUTPUT ;
    USE SIGNAL ;
    PORT
      LAYER M5 ;
        RECT  9.072 0 9.096 0.084 ;
    END
  END o[439]
  PIN o[43]
    DIRECTION OUTPUT ;
    USE SIGNAL ;
    PORT
      LAYER M5 ;
        RECT  27.12 0 27.144 0.084 ;
    END
  END o[43]
  PIN o[440]
    DIRECTION OUTPUT ;
    USE SIGNAL ;
    PORT
      LAYER M5 ;
        RECT  9.168 0 9.192 0.084 ;
    END
  END o[440]
  PIN o[441]
    DIRECTION OUTPUT ;
    USE SIGNAL ;
    PORT
      LAYER M5 ;
        RECT  9.264 0 9.288 0.084 ;
    END
  END o[441]
  PIN o[442]
    DIRECTION OUTPUT ;
    USE SIGNAL ;
    PORT
      LAYER M5 ;
        RECT  9.36 0 9.384 0.084 ;
    END
  END o[442]
  PIN o[443]
    DIRECTION OUTPUT ;
    USE SIGNAL ;
    PORT
      LAYER M5 ;
        RECT  9.456 0 9.48 0.084 ;
    END
  END o[443]
  PIN o[444]
    DIRECTION OUTPUT ;
    USE SIGNAL ;
    PORT
      LAYER M5 ;
        RECT  9.552 0 9.576 0.084 ;
    END
  END o[444]
  PIN o[445]
    DIRECTION OUTPUT ;
    USE SIGNAL ;
    PORT
      LAYER M5 ;
        RECT  9.648 0 9.672 0.084 ;
    END
  END o[445]
  PIN o[446]
    DIRECTION OUTPUT ;
    USE SIGNAL ;
    PORT
      LAYER M5 ;
        RECT  9.744 0 9.768 0.084 ;
    END
  END o[446]
  PIN o[447]
    DIRECTION OUTPUT ;
    USE SIGNAL ;
    PORT
      LAYER M5 ;
        RECT  9.84 0 9.864 0.084 ;
    END
  END o[447]
  PIN o[448]
    DIRECTION OUTPUT ;
    USE SIGNAL ;
    PORT
      LAYER M5 ;
        RECT  3.792 0 3.816 0.084 ;
    END
  END o[448]
  PIN o[449]
    DIRECTION OUTPUT ;
    USE SIGNAL ;
    PORT
      LAYER M5 ;
        RECT  3.888 0 3.912 0.084 ;
    END
  END o[449]
  PIN o[44]
    DIRECTION OUTPUT ;
    USE SIGNAL ;
    PORT
      LAYER M5 ;
        RECT  27.216 0 27.24 0.084 ;
    END
  END o[44]
  PIN o[450]
    DIRECTION OUTPUT ;
    USE SIGNAL ;
    PORT
      LAYER M5 ;
        RECT  3.984 0 4.008 0.084 ;
    END
  END o[450]
  PIN o[451]
    DIRECTION OUTPUT ;
    USE SIGNAL ;
    PORT
      LAYER M5 ;
        RECT  4.08 0 4.104 0.084 ;
    END
  END o[451]
  PIN o[452]
    DIRECTION OUTPUT ;
    USE SIGNAL ;
    PORT
      LAYER M5 ;
        RECT  4.176 0 4.2 0.084 ;
    END
  END o[452]
  PIN o[453]
    DIRECTION OUTPUT ;
    USE SIGNAL ;
    PORT
      LAYER M5 ;
        RECT  4.272 0 4.296 0.084 ;
    END
  END o[453]
  PIN o[454]
    DIRECTION OUTPUT ;
    USE SIGNAL ;
    PORT
      LAYER M5 ;
        RECT  4.368 0 4.392 0.084 ;
    END
  END o[454]
  PIN o[455]
    DIRECTION OUTPUT ;
    USE SIGNAL ;
    PORT
      LAYER M5 ;
        RECT  4.464 0 4.488 0.084 ;
    END
  END o[455]
  PIN o[456]
    DIRECTION OUTPUT ;
    USE SIGNAL ;
    PORT
      LAYER M5 ;
        RECT  4.56 0 4.584 0.084 ;
    END
  END o[456]
  PIN o[457]
    DIRECTION OUTPUT ;
    USE SIGNAL ;
    PORT
      LAYER M5 ;
        RECT  4.656 0 4.68 0.084 ;
    END
  END o[457]
  PIN o[458]
    DIRECTION OUTPUT ;
    USE SIGNAL ;
    PORT
      LAYER M5 ;
        RECT  4.752 0 4.776 0.084 ;
    END
  END o[458]
  PIN o[459]
    DIRECTION OUTPUT ;
    USE SIGNAL ;
    PORT
      LAYER M5 ;
        RECT  4.848 0 4.872 0.084 ;
    END
  END o[459]
  PIN o[45]
    DIRECTION OUTPUT ;
    USE SIGNAL ;
    PORT
      LAYER M5 ;
        RECT  27.312 0 27.336 0.084 ;
    END
  END o[45]
  PIN o[460]
    DIRECTION OUTPUT ;
    USE SIGNAL ;
    PORT
      LAYER M5 ;
        RECT  4.944 0 4.968 0.084 ;
    END
  END o[460]
  PIN o[461]
    DIRECTION OUTPUT ;
    USE SIGNAL ;
    PORT
      LAYER M5 ;
        RECT  5.04 0 5.064 0.084 ;
    END
  END o[461]
  PIN o[462]
    DIRECTION OUTPUT ;
    USE SIGNAL ;
    PORT
      LAYER M5 ;
        RECT  5.136 0 5.16 0.084 ;
    END
  END o[462]
  PIN o[463]
    DIRECTION OUTPUT ;
    USE SIGNAL ;
    PORT
      LAYER M5 ;
        RECT  5.232 0 5.256 0.084 ;
    END
  END o[463]
  PIN o[464]
    DIRECTION OUTPUT ;
    USE SIGNAL ;
    PORT
      LAYER M5 ;
        RECT  5.328 0 5.352 0.084 ;
    END
  END o[464]
  PIN o[465]
    DIRECTION OUTPUT ;
    USE SIGNAL ;
    PORT
      LAYER M5 ;
        RECT  5.424 0 5.448 0.084 ;
    END
  END o[465]
  PIN o[466]
    DIRECTION OUTPUT ;
    USE SIGNAL ;
    PORT
      LAYER M5 ;
        RECT  5.52 0 5.544 0.084 ;
    END
  END o[466]
  PIN o[467]
    DIRECTION OUTPUT ;
    USE SIGNAL ;
    PORT
      LAYER M5 ;
        RECT  5.616 0 5.64 0.084 ;
    END
  END o[467]
  PIN o[468]
    DIRECTION OUTPUT ;
    USE SIGNAL ;
    PORT
      LAYER M5 ;
        RECT  5.712 0 5.736 0.084 ;
    END
  END o[468]
  PIN o[469]
    DIRECTION OUTPUT ;
    USE SIGNAL ;
    PORT
      LAYER M5 ;
        RECT  5.808 0 5.832 0.084 ;
    END
  END o[469]
  PIN o[46]
    DIRECTION OUTPUT ;
    USE SIGNAL ;
    PORT
      LAYER M5 ;
        RECT  27.408 0 27.432 0.084 ;
    END
  END o[46]
  PIN o[470]
    DIRECTION OUTPUT ;
    USE SIGNAL ;
    PORT
      LAYER M5 ;
        RECT  5.904 0 5.928 0.084 ;
    END
  END o[470]
  PIN o[471]
    DIRECTION OUTPUT ;
    USE SIGNAL ;
    PORT
      LAYER M5 ;
        RECT  6 0 6.024 0.084 ;
    END
  END o[471]
  PIN o[472]
    DIRECTION OUTPUT ;
    USE SIGNAL ;
    PORT
      LAYER M5 ;
        RECT  6.096 0 6.12 0.084 ;
    END
  END o[472]
  PIN o[473]
    DIRECTION OUTPUT ;
    USE SIGNAL ;
    PORT
      LAYER M5 ;
        RECT  6.192 0 6.216 0.084 ;
    END
  END o[473]
  PIN o[474]
    DIRECTION OUTPUT ;
    USE SIGNAL ;
    PORT
      LAYER M5 ;
        RECT  6.288 0 6.312 0.084 ;
    END
  END o[474]
  PIN o[475]
    DIRECTION OUTPUT ;
    USE SIGNAL ;
    PORT
      LAYER M5 ;
        RECT  6.384 0 6.408 0.084 ;
    END
  END o[475]
  PIN o[476]
    DIRECTION OUTPUT ;
    USE SIGNAL ;
    PORT
      LAYER M5 ;
        RECT  6.48 0 6.504 0.084 ;
    END
  END o[476]
  PIN o[477]
    DIRECTION OUTPUT ;
    USE SIGNAL ;
    PORT
      LAYER M5 ;
        RECT  6.576 0 6.6 0.084 ;
    END
  END o[477]
  PIN o[478]
    DIRECTION OUTPUT ;
    USE SIGNAL ;
    PORT
      LAYER M5 ;
        RECT  6.672 0 6.696 0.084 ;
    END
  END o[478]
  PIN o[479]
    DIRECTION OUTPUT ;
    USE SIGNAL ;
    PORT
      LAYER M5 ;
        RECT  6.768 0 6.792 0.084 ;
    END
  END o[479]
  PIN o[47]
    DIRECTION OUTPUT ;
    USE SIGNAL ;
    PORT
      LAYER M5 ;
        RECT  27.504 0 27.528 0.084 ;
    END
  END o[47]
  PIN o[480]
    DIRECTION OUTPUT ;
    USE SIGNAL ;
    PORT
      LAYER M5 ;
        RECT  39.12 0 39.144 0.084 ;
    END
  END o[480]
  PIN o[481]
    DIRECTION OUTPUT ;
    USE SIGNAL ;
    PORT
      LAYER M5 ;
        RECT  39.216 0 39.24 0.084 ;
    END
  END o[481]
  PIN o[482]
    DIRECTION OUTPUT ;
    USE SIGNAL ;
    PORT
      LAYER M5 ;
        RECT  39.312 0 39.336 0.084 ;
    END
  END o[482]
  PIN o[483]
    DIRECTION OUTPUT ;
    USE SIGNAL ;
    PORT
      LAYER M5 ;
        RECT  39.408 0 39.432 0.084 ;
    END
  END o[483]
  PIN o[484]
    DIRECTION OUTPUT ;
    USE SIGNAL ;
    PORT
      LAYER M5 ;
        RECT  39.504 0 39.528 0.084 ;
    END
  END o[484]
  PIN o[485]
    DIRECTION OUTPUT ;
    USE SIGNAL ;
    PORT
      LAYER M5 ;
        RECT  39.6 0 39.624 0.084 ;
    END
  END o[485]
  PIN o[486]
    DIRECTION OUTPUT ;
    USE SIGNAL ;
    PORT
      LAYER M5 ;
        RECT  39.696 0 39.72 0.084 ;
    END
  END o[486]
  PIN o[487]
    DIRECTION OUTPUT ;
    USE SIGNAL ;
    PORT
      LAYER M5 ;
        RECT  39.792 0 39.816 0.084 ;
    END
  END o[487]
  PIN o[488]
    DIRECTION OUTPUT ;
    USE SIGNAL ;
    PORT
      LAYER M5 ;
        RECT  39.888 0 39.912 0.084 ;
    END
  END o[488]
  PIN o[489]
    DIRECTION OUTPUT ;
    USE SIGNAL ;
    PORT
      LAYER M5 ;
        RECT  39.984 0 40.008 0.084 ;
    END
  END o[489]
  PIN o[48]
    DIRECTION OUTPUT ;
    USE SIGNAL ;
    PORT
      LAYER M5 ;
        RECT  27.6 0 27.624 0.084 ;
    END
  END o[48]
  PIN o[490]
    DIRECTION OUTPUT ;
    USE SIGNAL ;
    PORT
      LAYER M5 ;
        RECT  40.08 0 40.104 0.084 ;
    END
  END o[490]
  PIN o[491]
    DIRECTION OUTPUT ;
    USE SIGNAL ;
    PORT
      LAYER M5 ;
        RECT  40.176 0 40.2 0.084 ;
    END
  END o[491]
  PIN o[492]
    DIRECTION OUTPUT ;
    USE SIGNAL ;
    PORT
      LAYER M5 ;
        RECT  40.272 0 40.296 0.084 ;
    END
  END o[492]
  PIN o[493]
    DIRECTION OUTPUT ;
    USE SIGNAL ;
    PORT
      LAYER M5 ;
        RECT  40.368 0 40.392 0.084 ;
    END
  END o[493]
  PIN o[494]
    DIRECTION OUTPUT ;
    USE SIGNAL ;
    PORT
      LAYER M5 ;
        RECT  40.464 0 40.488 0.084 ;
    END
  END o[494]
  PIN o[495]
    DIRECTION OUTPUT ;
    USE SIGNAL ;
    PORT
      LAYER M5 ;
        RECT  40.56 0 40.584 0.084 ;
    END
  END o[495]
  PIN o[496]
    DIRECTION OUTPUT ;
    USE SIGNAL ;
    PORT
      LAYER M5 ;
        RECT  40.656 0 40.68 0.084 ;
    END
  END o[496]
  PIN o[497]
    DIRECTION OUTPUT ;
    USE SIGNAL ;
    PORT
      LAYER M5 ;
        RECT  40.752 0 40.776 0.084 ;
    END
  END o[497]
  PIN o[498]
    DIRECTION OUTPUT ;
    USE SIGNAL ;
    PORT
      LAYER M5 ;
        RECT  40.848 0 40.872 0.084 ;
    END
  END o[498]
  PIN o[499]
    DIRECTION OUTPUT ;
    USE SIGNAL ;
    PORT
      LAYER M5 ;
        RECT  40.944 0 40.968 0.084 ;
    END
  END o[499]
  PIN o[49]
    DIRECTION OUTPUT ;
    USE SIGNAL ;
    PORT
      LAYER M5 ;
        RECT  27.696 0 27.72 0.084 ;
    END
  END o[49]
  PIN o[4]
    DIRECTION OUTPUT ;
    USE SIGNAL ;
    PORT
      LAYER M5 ;
        RECT  35.664 0 35.688 0.084 ;
    END
  END o[4]
  PIN o[500]
    DIRECTION OUTPUT ;
    USE SIGNAL ;
    PORT
      LAYER M5 ;
        RECT  41.04 0 41.064 0.084 ;
    END
  END o[500]
  PIN o[501]
    DIRECTION OUTPUT ;
    USE SIGNAL ;
    PORT
      LAYER M5 ;
        RECT  41.136 0 41.16 0.084 ;
    END
  END o[501]
  PIN o[502]
    DIRECTION OUTPUT ;
    USE SIGNAL ;
    PORT
      LAYER M5 ;
        RECT  41.232 0 41.256 0.084 ;
    END
  END o[502]
  PIN o[503]
    DIRECTION OUTPUT ;
    USE SIGNAL ;
    PORT
      LAYER M5 ;
        RECT  41.328 0 41.352 0.084 ;
    END
  END o[503]
  PIN o[504]
    DIRECTION OUTPUT ;
    USE SIGNAL ;
    PORT
      LAYER M5 ;
        RECT  41.424 0 41.448 0.084 ;
    END
  END o[504]
  PIN o[505]
    DIRECTION OUTPUT ;
    USE SIGNAL ;
    PORT
      LAYER M5 ;
        RECT  41.52 0 41.544 0.084 ;
    END
  END o[505]
  PIN o[506]
    DIRECTION OUTPUT ;
    USE SIGNAL ;
    PORT
      LAYER M5 ;
        RECT  41.616 0 41.64 0.084 ;
    END
  END o[506]
  PIN o[507]
    DIRECTION OUTPUT ;
    USE SIGNAL ;
    PORT
      LAYER M5 ;
        RECT  41.712 0 41.736 0.084 ;
    END
  END o[507]
  PIN o[508]
    DIRECTION OUTPUT ;
    USE SIGNAL ;
    PORT
      LAYER M5 ;
        RECT  41.808 0 41.832 0.084 ;
    END
  END o[508]
  PIN o[509]
    DIRECTION OUTPUT ;
    USE SIGNAL ;
    PORT
      LAYER M5 ;
        RECT  41.904 0 41.928 0.084 ;
    END
  END o[509]
  PIN o[50]
    DIRECTION OUTPUT ;
    USE SIGNAL ;
    PORT
      LAYER M5 ;
        RECT  27.792 0 27.816 0.084 ;
    END
  END o[50]
  PIN o[510]
    DIRECTION OUTPUT ;
    USE SIGNAL ;
    PORT
      LAYER M5 ;
        RECT  42 0 42.024 0.084 ;
    END
  END o[510]
  PIN o[511]
    DIRECTION OUTPUT ;
    USE SIGNAL ;
    PORT
      LAYER M5 ;
        RECT  42.096 0 42.12 0.084 ;
    END
  END o[511]
  PIN o[512]
    DIRECTION OUTPUT ;
    USE SIGNAL ;
    PORT
      LAYER M5 ;
        RECT  45.264 0 45.288 0.084 ;
    END
  END o[512]
  PIN o[513]
    DIRECTION OUTPUT ;
    USE SIGNAL ;
    PORT
      LAYER M5 ;
        RECT  45.36 0 45.384 0.084 ;
    END
  END o[513]
  PIN o[514]
    DIRECTION OUTPUT ;
    USE SIGNAL ;
    PORT
      LAYER M5 ;
        RECT  45.456 0 45.48 0.084 ;
    END
  END o[514]
  PIN o[515]
    DIRECTION OUTPUT ;
    USE SIGNAL ;
    PORT
      LAYER M5 ;
        RECT  45.552 0 45.576 0.084 ;
    END
  END o[515]
  PIN o[516]
    DIRECTION OUTPUT ;
    USE SIGNAL ;
    PORT
      LAYER M5 ;
        RECT  45.648 0 45.672 0.084 ;
    END
  END o[516]
  PIN o[517]
    DIRECTION OUTPUT ;
    USE SIGNAL ;
    PORT
      LAYER M5 ;
        RECT  45.744 0 45.768 0.084 ;
    END
  END o[517]
  PIN o[518]
    DIRECTION OUTPUT ;
    USE SIGNAL ;
    PORT
      LAYER M5 ;
        RECT  45.84 0 45.864 0.084 ;
    END
  END o[518]
  PIN o[519]
    DIRECTION OUTPUT ;
    USE SIGNAL ;
    PORT
      LAYER M5 ;
        RECT  45.936 0 45.96 0.084 ;
    END
  END o[519]
  PIN o[51]
    DIRECTION OUTPUT ;
    USE SIGNAL ;
    PORT
      LAYER M5 ;
        RECT  27.888 0 27.912 0.084 ;
    END
  END o[51]
  PIN o[520]
    DIRECTION OUTPUT ;
    USE SIGNAL ;
    PORT
      LAYER M5 ;
        RECT  46.032 0 46.056 0.084 ;
    END
  END o[520]
  PIN o[521]
    DIRECTION OUTPUT ;
    USE SIGNAL ;
    PORT
      LAYER M5 ;
        RECT  46.128 0 46.152 0.084 ;
    END
  END o[521]
  PIN o[522]
    DIRECTION OUTPUT ;
    USE SIGNAL ;
    PORT
      LAYER M5 ;
        RECT  46.224 0 46.248 0.084 ;
    END
  END o[522]
  PIN o[523]
    DIRECTION OUTPUT ;
    USE SIGNAL ;
    PORT
      LAYER M5 ;
        RECT  46.32 0 46.344 0.084 ;
    END
  END o[523]
  PIN o[524]
    DIRECTION OUTPUT ;
    USE SIGNAL ;
    PORT
      LAYER M5 ;
        RECT  46.416 0 46.44 0.084 ;
    END
  END o[524]
  PIN o[525]
    DIRECTION OUTPUT ;
    USE SIGNAL ;
    PORT
      LAYER M5 ;
        RECT  46.512 0 46.536 0.084 ;
    END
  END o[525]
  PIN o[526]
    DIRECTION OUTPUT ;
    USE SIGNAL ;
    PORT
      LAYER M5 ;
        RECT  46.608 0 46.632 0.084 ;
    END
  END o[526]
  PIN o[527]
    DIRECTION OUTPUT ;
    USE SIGNAL ;
    PORT
      LAYER M5 ;
        RECT  46.704 0 46.728 0.084 ;
    END
  END o[527]
  PIN o[528]
    DIRECTION OUTPUT ;
    USE SIGNAL ;
    PORT
      LAYER M5 ;
        RECT  46.8 0 46.824 0.084 ;
    END
  END o[528]
  PIN o[529]
    DIRECTION OUTPUT ;
    USE SIGNAL ;
    PORT
      LAYER M5 ;
        RECT  46.896 0 46.92 0.084 ;
    END
  END o[529]
  PIN o[52]
    DIRECTION OUTPUT ;
    USE SIGNAL ;
    PORT
      LAYER M5 ;
        RECT  27.984 0 28.008 0.084 ;
    END
  END o[52]
  PIN o[530]
    DIRECTION OUTPUT ;
    USE SIGNAL ;
    PORT
      LAYER M5 ;
        RECT  46.992 0 47.016 0.084 ;
    END
  END o[530]
  PIN o[531]
    DIRECTION OUTPUT ;
    USE SIGNAL ;
    PORT
      LAYER M5 ;
        RECT  47.088 0 47.112 0.084 ;
    END
  END o[531]
  PIN o[532]
    DIRECTION OUTPUT ;
    USE SIGNAL ;
    PORT
      LAYER M5 ;
        RECT  47.184 0 47.208 0.084 ;
    END
  END o[532]
  PIN o[533]
    DIRECTION OUTPUT ;
    USE SIGNAL ;
    PORT
      LAYER M5 ;
        RECT  47.28 0 47.304 0.084 ;
    END
  END o[533]
  PIN o[534]
    DIRECTION OUTPUT ;
    USE SIGNAL ;
    PORT
      LAYER M5 ;
        RECT  47.376 0 47.4 0.084 ;
    END
  END o[534]
  PIN o[535]
    DIRECTION OUTPUT ;
    USE SIGNAL ;
    PORT
      LAYER M5 ;
        RECT  47.472 0 47.496 0.084 ;
    END
  END o[535]
  PIN o[536]
    DIRECTION OUTPUT ;
    USE SIGNAL ;
    PORT
      LAYER M5 ;
        RECT  47.568 0 47.592 0.084 ;
    END
  END o[536]
  PIN o[537]
    DIRECTION OUTPUT ;
    USE SIGNAL ;
    PORT
      LAYER M5 ;
        RECT  47.664 0 47.688 0.084 ;
    END
  END o[537]
  PIN o[538]
    DIRECTION OUTPUT ;
    USE SIGNAL ;
    PORT
      LAYER M5 ;
        RECT  47.76 0 47.784 0.084 ;
    END
  END o[538]
  PIN o[539]
    DIRECTION OUTPUT ;
    USE SIGNAL ;
    PORT
      LAYER M5 ;
        RECT  47.856 0 47.88 0.084 ;
    END
  END o[539]
  PIN o[53]
    DIRECTION OUTPUT ;
    USE SIGNAL ;
    PORT
      LAYER M5 ;
        RECT  28.08 0 28.104 0.084 ;
    END
  END o[53]
  PIN o[540]
    DIRECTION OUTPUT ;
    USE SIGNAL ;
    PORT
      LAYER M5 ;
        RECT  47.952 0 47.976 0.084 ;
    END
  END o[540]
  PIN o[541]
    DIRECTION OUTPUT ;
    USE SIGNAL ;
    PORT
      LAYER M5 ;
        RECT  48.048 0 48.072 0.084 ;
    END
  END o[541]
  PIN o[542]
    DIRECTION OUTPUT ;
    USE SIGNAL ;
    PORT
      LAYER M5 ;
        RECT  48.144 0 48.168 0.084 ;
    END
  END o[542]
  PIN o[543]
    DIRECTION OUTPUT ;
    USE SIGNAL ;
    PORT
      LAYER M5 ;
        RECT  48.24 0 48.264 0.084 ;
    END
  END o[543]
  PIN o[544]
    DIRECTION OUTPUT ;
    USE SIGNAL ;
    PORT
      LAYER M5 ;
        RECT  48.336 0 48.36 0.084 ;
    END
  END o[544]
  PIN o[545]
    DIRECTION OUTPUT ;
    USE SIGNAL ;
    PORT
      LAYER M5 ;
        RECT  48.432 0 48.456 0.084 ;
    END
  END o[545]
  PIN o[546]
    DIRECTION OUTPUT ;
    USE SIGNAL ;
    PORT
      LAYER M5 ;
        RECT  48.528 0 48.552 0.084 ;
    END
  END o[546]
  PIN o[547]
    DIRECTION OUTPUT ;
    USE SIGNAL ;
    PORT
      LAYER M5 ;
        RECT  48.624 0 48.648 0.084 ;
    END
  END o[547]
  PIN o[548]
    DIRECTION OUTPUT ;
    USE SIGNAL ;
    PORT
      LAYER M5 ;
        RECT  48.72 0 48.744 0.084 ;
    END
  END o[548]
  PIN o[549]
    DIRECTION OUTPUT ;
    USE SIGNAL ;
    PORT
      LAYER M5 ;
        RECT  48.816 0 48.84 0.084 ;
    END
  END o[549]
  PIN o[54]
    DIRECTION OUTPUT ;
    USE SIGNAL ;
    PORT
      LAYER M5 ;
        RECT  28.176 0 28.2 0.084 ;
    END
  END o[54]
  PIN o[550]
    DIRECTION OUTPUT ;
    USE SIGNAL ;
    PORT
      LAYER M5 ;
        RECT  48.912 0 48.936 0.084 ;
    END
  END o[550]
  PIN o[551]
    DIRECTION OUTPUT ;
    USE SIGNAL ;
    PORT
      LAYER M5 ;
        RECT  49.008 0 49.032 0.084 ;
    END
  END o[551]
  PIN o[552]
    DIRECTION OUTPUT ;
    USE SIGNAL ;
    PORT
      LAYER M5 ;
        RECT  49.104 0 49.128 0.084 ;
    END
  END o[552]
  PIN o[553]
    DIRECTION OUTPUT ;
    USE SIGNAL ;
    PORT
      LAYER M5 ;
        RECT  49.2 0 49.224 0.084 ;
    END
  END o[553]
  PIN o[554]
    DIRECTION OUTPUT ;
    USE SIGNAL ;
    PORT
      LAYER M5 ;
        RECT  49.296 0 49.32 0.084 ;
    END
  END o[554]
  PIN o[555]
    DIRECTION OUTPUT ;
    USE SIGNAL ;
    PORT
      LAYER M5 ;
        RECT  49.392 0 49.416 0.084 ;
    END
  END o[555]
  PIN o[556]
    DIRECTION OUTPUT ;
    USE SIGNAL ;
    PORT
      LAYER M5 ;
        RECT  49.488 0 49.512 0.084 ;
    END
  END o[556]
  PIN o[557]
    DIRECTION OUTPUT ;
    USE SIGNAL ;
    PORT
      LAYER M5 ;
        RECT  49.584 0 49.608 0.084 ;
    END
  END o[557]
  PIN o[558]
    DIRECTION OUTPUT ;
    USE SIGNAL ;
    PORT
      LAYER M5 ;
        RECT  49.68 0 49.704 0.084 ;
    END
  END o[558]
  PIN o[559]
    DIRECTION OUTPUT ;
    USE SIGNAL ;
    PORT
      LAYER M5 ;
        RECT  49.776 0 49.8 0.084 ;
    END
  END o[559]
  PIN o[55]
    DIRECTION OUTPUT ;
    USE SIGNAL ;
    PORT
      LAYER M5 ;
        RECT  28.272 0 28.296 0.084 ;
    END
  END o[55]
  PIN o[560]
    DIRECTION OUTPUT ;
    USE SIGNAL ;
    PORT
      LAYER M5 ;
        RECT  49.872 0 49.896 0.084 ;
    END
  END o[560]
  PIN o[561]
    DIRECTION OUTPUT ;
    USE SIGNAL ;
    PORT
      LAYER M5 ;
        RECT  49.968 0 49.992 0.084 ;
    END
  END o[561]
  PIN o[562]
    DIRECTION OUTPUT ;
    USE SIGNAL ;
    PORT
      LAYER M5 ;
        RECT  50.064 0 50.088 0.084 ;
    END
  END o[562]
  PIN o[563]
    DIRECTION OUTPUT ;
    USE SIGNAL ;
    PORT
      LAYER M5 ;
        RECT  50.16 0 50.184 0.084 ;
    END
  END o[563]
  PIN o[564]
    DIRECTION OUTPUT ;
    USE SIGNAL ;
    PORT
      LAYER M5 ;
        RECT  50.256 0 50.28 0.084 ;
    END
  END o[564]
  PIN o[565]
    DIRECTION OUTPUT ;
    USE SIGNAL ;
    PORT
      LAYER M5 ;
        RECT  50.352 0 50.376 0.084 ;
    END
  END o[565]
  PIN o[566]
    DIRECTION OUTPUT ;
    USE SIGNAL ;
    PORT
      LAYER M5 ;
        RECT  50.448 0 50.472 0.084 ;
    END
  END o[566]
  PIN o[567]
    DIRECTION OUTPUT ;
    USE SIGNAL ;
    PORT
      LAYER M5 ;
        RECT  50.544 0 50.568 0.084 ;
    END
  END o[567]
  PIN o[568]
    DIRECTION OUTPUT ;
    USE SIGNAL ;
    PORT
      LAYER M5 ;
        RECT  50.64 0 50.664 0.084 ;
    END
  END o[568]
  PIN o[569]
    DIRECTION OUTPUT ;
    USE SIGNAL ;
    PORT
      LAYER M5 ;
        RECT  50.736 0 50.76 0.084 ;
    END
  END o[569]
  PIN o[56]
    DIRECTION OUTPUT ;
    USE SIGNAL ;
    PORT
      LAYER M5 ;
        RECT  28.368 0 28.392 0.084 ;
    END
  END o[56]
  PIN o[570]
    DIRECTION OUTPUT ;
    USE SIGNAL ;
    PORT
      LAYER M5 ;
        RECT  50.832 0 50.856 0.084 ;
    END
  END o[570]
  PIN o[571]
    DIRECTION OUTPUT ;
    USE SIGNAL ;
    PORT
      LAYER M5 ;
        RECT  50.928 0 50.952 0.084 ;
    END
  END o[571]
  PIN o[572]
    DIRECTION OUTPUT ;
    USE SIGNAL ;
    PORT
      LAYER M5 ;
        RECT  51.024 0 51.048 0.084 ;
    END
  END o[572]
  PIN o[573]
    DIRECTION OUTPUT ;
    USE SIGNAL ;
    PORT
      LAYER M5 ;
        RECT  51.12 0 51.144 0.084 ;
    END
  END o[573]
  PIN o[574]
    DIRECTION OUTPUT ;
    USE SIGNAL ;
    PORT
      LAYER M5 ;
        RECT  51.216 0 51.24 0.084 ;
    END
  END o[574]
  PIN o[575]
    DIRECTION OUTPUT ;
    USE SIGNAL ;
    PORT
      LAYER M5 ;
        RECT  51.312 0 51.336 0.084 ;
    END
  END o[575]
  PIN o[576]
    DIRECTION OUTPUT ;
    USE SIGNAL ;
    PORT
      LAYER M5 ;
        RECT  58.32 0 58.344 0.084 ;
    END
  END o[576]
  PIN o[577]
    DIRECTION OUTPUT ;
    USE SIGNAL ;
    PORT
      LAYER M5 ;
        RECT  58.416 0 58.44 0.084 ;
    END
  END o[577]
  PIN o[578]
    DIRECTION OUTPUT ;
    USE SIGNAL ;
    PORT
      LAYER M5 ;
        RECT  58.512 0 58.536 0.084 ;
    END
  END o[578]
  PIN o[579]
    DIRECTION OUTPUT ;
    USE SIGNAL ;
    PORT
      LAYER M5 ;
        RECT  58.608 0 58.632 0.084 ;
    END
  END o[579]
  PIN o[57]
    DIRECTION OUTPUT ;
    USE SIGNAL ;
    PORT
      LAYER M5 ;
        RECT  28.464 0 28.488 0.084 ;
    END
  END o[57]
  PIN o[580]
    DIRECTION OUTPUT ;
    USE SIGNAL ;
    PORT
      LAYER M5 ;
        RECT  58.704 0 58.728 0.084 ;
    END
  END o[580]
  PIN o[581]
    DIRECTION OUTPUT ;
    USE SIGNAL ;
    PORT
      LAYER M5 ;
        RECT  58.8 0 58.824 0.084 ;
    END
  END o[581]
  PIN o[582]
    DIRECTION OUTPUT ;
    USE SIGNAL ;
    PORT
      LAYER M5 ;
        RECT  58.896 0 58.92 0.084 ;
    END
  END o[582]
  PIN o[583]
    DIRECTION OUTPUT ;
    USE SIGNAL ;
    PORT
      LAYER M5 ;
        RECT  58.992 0 59.016 0.084 ;
    END
  END o[583]
  PIN o[584]
    DIRECTION OUTPUT ;
    USE SIGNAL ;
    PORT
      LAYER M5 ;
        RECT  59.088 0 59.112 0.084 ;
    END
  END o[584]
  PIN o[585]
    DIRECTION OUTPUT ;
    USE SIGNAL ;
    PORT
      LAYER M5 ;
        RECT  59.184 0 59.208 0.084 ;
    END
  END o[585]
  PIN o[586]
    DIRECTION OUTPUT ;
    USE SIGNAL ;
    PORT
      LAYER M5 ;
        RECT  59.28 0 59.304 0.084 ;
    END
  END o[586]
  PIN o[587]
    DIRECTION OUTPUT ;
    USE SIGNAL ;
    PORT
      LAYER M5 ;
        RECT  59.376 0 59.4 0.084 ;
    END
  END o[587]
  PIN o[588]
    DIRECTION OUTPUT ;
    USE SIGNAL ;
    PORT
      LAYER M5 ;
        RECT  59.472 0 59.496 0.084 ;
    END
  END o[588]
  PIN o[589]
    DIRECTION OUTPUT ;
    USE SIGNAL ;
    PORT
      LAYER M5 ;
        RECT  59.568 0 59.592 0.084 ;
    END
  END o[589]
  PIN o[58]
    DIRECTION OUTPUT ;
    USE SIGNAL ;
    PORT
      LAYER M5 ;
        RECT  28.56 0 28.584 0.084 ;
    END
  END o[58]
  PIN o[590]
    DIRECTION OUTPUT ;
    USE SIGNAL ;
    PORT
      LAYER M5 ;
        RECT  59.664 0 59.688 0.084 ;
    END
  END o[590]
  PIN o[591]
    DIRECTION OUTPUT ;
    USE SIGNAL ;
    PORT
      LAYER M5 ;
        RECT  59.76 0 59.784 0.084 ;
    END
  END o[591]
  PIN o[592]
    DIRECTION OUTPUT ;
    USE SIGNAL ;
    PORT
      LAYER M5 ;
        RECT  59.856 0 59.88 0.084 ;
    END
  END o[592]
  PIN o[593]
    DIRECTION OUTPUT ;
    USE SIGNAL ;
    PORT
      LAYER M5 ;
        RECT  59.952 0 59.976 0.084 ;
    END
  END o[593]
  PIN o[594]
    DIRECTION OUTPUT ;
    USE SIGNAL ;
    PORT
      LAYER M5 ;
        RECT  60.048 0 60.072 0.084 ;
    END
  END o[594]
  PIN o[595]
    DIRECTION OUTPUT ;
    USE SIGNAL ;
    PORT
      LAYER M5 ;
        RECT  60.144 0 60.168 0.084 ;
    END
  END o[595]
  PIN o[596]
    DIRECTION OUTPUT ;
    USE SIGNAL ;
    PORT
      LAYER M5 ;
        RECT  60.24 0 60.264 0.084 ;
    END
  END o[596]
  PIN o[597]
    DIRECTION OUTPUT ;
    USE SIGNAL ;
    PORT
      LAYER M5 ;
        RECT  60.336 0 60.36 0.084 ;
    END
  END o[597]
  PIN o[598]
    DIRECTION OUTPUT ;
    USE SIGNAL ;
    PORT
      LAYER M5 ;
        RECT  60.432 0 60.456 0.084 ;
    END
  END o[598]
  PIN o[599]
    DIRECTION OUTPUT ;
    USE SIGNAL ;
    PORT
      LAYER M5 ;
        RECT  60.528 0 60.552 0.084 ;
    END
  END o[599]
  PIN o[59]
    DIRECTION OUTPUT ;
    USE SIGNAL ;
    PORT
      LAYER M5 ;
        RECT  28.656 0 28.68 0.084 ;
    END
  END o[59]
  PIN o[5]
    DIRECTION OUTPUT ;
    USE SIGNAL ;
    PORT
      LAYER M5 ;
        RECT  35.76 0 35.784 0.084 ;
    END
  END o[5]
  PIN o[600]
    DIRECTION OUTPUT ;
    USE SIGNAL ;
    PORT
      LAYER M5 ;
        RECT  60.624 0 60.648 0.084 ;
    END
  END o[600]
  PIN o[601]
    DIRECTION OUTPUT ;
    USE SIGNAL ;
    PORT
      LAYER M5 ;
        RECT  60.72 0 60.744 0.084 ;
    END
  END o[601]
  PIN o[602]
    DIRECTION OUTPUT ;
    USE SIGNAL ;
    PORT
      LAYER M5 ;
        RECT  60.816 0 60.84 0.084 ;
    END
  END o[602]
  PIN o[603]
    DIRECTION OUTPUT ;
    USE SIGNAL ;
    PORT
      LAYER M5 ;
        RECT  60.912 0 60.936 0.084 ;
    END
  END o[603]
  PIN o[604]
    DIRECTION OUTPUT ;
    USE SIGNAL ;
    PORT
      LAYER M5 ;
        RECT  61.008 0 61.032 0.084 ;
    END
  END o[604]
  PIN o[605]
    DIRECTION OUTPUT ;
    USE SIGNAL ;
    PORT
      LAYER M5 ;
        RECT  61.104 0 61.128 0.084 ;
    END
  END o[605]
  PIN o[606]
    DIRECTION OUTPUT ;
    USE SIGNAL ;
    PORT
      LAYER M5 ;
        RECT  61.2 0 61.224 0.084 ;
    END
  END o[606]
  PIN o[607]
    DIRECTION OUTPUT ;
    USE SIGNAL ;
    PORT
      LAYER M5 ;
        RECT  61.296 0 61.32 0.084 ;
    END
  END o[607]
  PIN o[608]
    DIRECTION OUTPUT ;
    USE SIGNAL ;
    PORT
      LAYER M5 ;
        RECT  61.392 0 61.416 0.084 ;
    END
  END o[608]
  PIN o[609]
    DIRECTION OUTPUT ;
    USE SIGNAL ;
    PORT
      LAYER M5 ;
        RECT  61.488 0 61.512 0.084 ;
    END
  END o[609]
  PIN o[60]
    DIRECTION OUTPUT ;
    USE SIGNAL ;
    PORT
      LAYER M5 ;
        RECT  28.752 0 28.776 0.084 ;
    END
  END o[60]
  PIN o[610]
    DIRECTION OUTPUT ;
    USE SIGNAL ;
    PORT
      LAYER M5 ;
        RECT  61.584 0 61.608 0.084 ;
    END
  END o[610]
  PIN o[611]
    DIRECTION OUTPUT ;
    USE SIGNAL ;
    PORT
      LAYER M5 ;
        RECT  61.68 0 61.704 0.084 ;
    END
  END o[611]
  PIN o[612]
    DIRECTION OUTPUT ;
    USE SIGNAL ;
    PORT
      LAYER M5 ;
        RECT  61.776 0 61.8 0.084 ;
    END
  END o[612]
  PIN o[613]
    DIRECTION OUTPUT ;
    USE SIGNAL ;
    PORT
      LAYER M5 ;
        RECT  61.872 0 61.896 0.084 ;
    END
  END o[613]
  PIN o[614]
    DIRECTION OUTPUT ;
    USE SIGNAL ;
    PORT
      LAYER M5 ;
        RECT  61.968 0 61.992 0.084 ;
    END
  END o[614]
  PIN o[615]
    DIRECTION OUTPUT ;
    USE SIGNAL ;
    PORT
      LAYER M5 ;
        RECT  62.064 0 62.088 0.084 ;
    END
  END o[615]
  PIN o[616]
    DIRECTION OUTPUT ;
    USE SIGNAL ;
    PORT
      LAYER M5 ;
        RECT  62.16 0 62.184 0.084 ;
    END
  END o[616]
  PIN o[617]
    DIRECTION OUTPUT ;
    USE SIGNAL ;
    PORT
      LAYER M5 ;
        RECT  62.256 0 62.28 0.084 ;
    END
  END o[617]
  PIN o[618]
    DIRECTION OUTPUT ;
    USE SIGNAL ;
    PORT
      LAYER M5 ;
        RECT  62.352 0 62.376 0.084 ;
    END
  END o[618]
  PIN o[619]
    DIRECTION OUTPUT ;
    USE SIGNAL ;
    PORT
      LAYER M5 ;
        RECT  62.448 0 62.472 0.084 ;
    END
  END o[619]
  PIN o[61]
    DIRECTION OUTPUT ;
    USE SIGNAL ;
    PORT
      LAYER M5 ;
        RECT  28.848 0 28.872 0.084 ;
    END
  END o[61]
  PIN o[620]
    DIRECTION OUTPUT ;
    USE SIGNAL ;
    PORT
      LAYER M5 ;
        RECT  62.544 0 62.568 0.084 ;
    END
  END o[620]
  PIN o[621]
    DIRECTION OUTPUT ;
    USE SIGNAL ;
    PORT
      LAYER M5 ;
        RECT  62.64 0 62.664 0.084 ;
    END
  END o[621]
  PIN o[622]
    DIRECTION OUTPUT ;
    USE SIGNAL ;
    PORT
      LAYER M5 ;
        RECT  62.736 0 62.76 0.084 ;
    END
  END o[622]
  PIN o[623]
    DIRECTION OUTPUT ;
    USE SIGNAL ;
    PORT
      LAYER M5 ;
        RECT  62.832 0 62.856 0.084 ;
    END
  END o[623]
  PIN o[62]
    DIRECTION OUTPUT ;
    USE SIGNAL ;
    PORT
      LAYER M5 ;
        RECT  28.944 0 28.968 0.084 ;
    END
  END o[62]
  PIN o[63]
    DIRECTION OUTPUT ;
    USE SIGNAL ;
    PORT
      LAYER M5 ;
        RECT  29.04 0 29.064 0.084 ;
    END
  END o[63]
  PIN o[64]
    DIRECTION OUTPUT ;
    USE SIGNAL ;
    PORT
      LAYER M5 ;
        RECT  32.208 0 32.232 0.084 ;
    END
  END o[64]
  PIN o[65]
    DIRECTION OUTPUT ;
    USE SIGNAL ;
    PORT
      LAYER M5 ;
        RECT  32.304 0 32.328 0.084 ;
    END
  END o[65]
  PIN o[66]
    DIRECTION OUTPUT ;
    USE SIGNAL ;
    PORT
      LAYER M5 ;
        RECT  32.4 0 32.424 0.084 ;
    END
  END o[66]
  PIN o[67]
    DIRECTION OUTPUT ;
    USE SIGNAL ;
    PORT
      LAYER M5 ;
        RECT  32.496 0 32.52 0.084 ;
    END
  END o[67]
  PIN o[68]
    DIRECTION OUTPUT ;
    USE SIGNAL ;
    PORT
      LAYER M5 ;
        RECT  32.592 0 32.616 0.084 ;
    END
  END o[68]
  PIN o[69]
    DIRECTION OUTPUT ;
    USE SIGNAL ;
    PORT
      LAYER M5 ;
        RECT  32.688 0 32.712 0.084 ;
    END
  END o[69]
  PIN o[6]
    DIRECTION OUTPUT ;
    USE SIGNAL ;
    PORT
      LAYER M5 ;
        RECT  35.856 0 35.88 0.084 ;
    END
  END o[6]
  PIN o[70]
    DIRECTION OUTPUT ;
    USE SIGNAL ;
    PORT
      LAYER M5 ;
        RECT  32.784 0 32.808 0.084 ;
    END
  END o[70]
  PIN o[71]
    DIRECTION OUTPUT ;
    USE SIGNAL ;
    PORT
      LAYER M5 ;
        RECT  32.88 0 32.904 0.084 ;
    END
  END o[71]
  PIN o[72]
    DIRECTION OUTPUT ;
    USE SIGNAL ;
    PORT
      LAYER M5 ;
        RECT  32.976 0 33 0.084 ;
    END
  END o[72]
  PIN o[73]
    DIRECTION OUTPUT ;
    USE SIGNAL ;
    PORT
      LAYER M5 ;
        RECT  33.072 0 33.096 0.084 ;
    END
  END o[73]
  PIN o[74]
    DIRECTION OUTPUT ;
    USE SIGNAL ;
    PORT
      LAYER M5 ;
        RECT  33.168 0 33.192 0.084 ;
    END
  END o[74]
  PIN o[75]
    DIRECTION OUTPUT ;
    USE SIGNAL ;
    PORT
      LAYER M5 ;
        RECT  33.264 0 33.288 0.084 ;
    END
  END o[75]
  PIN o[76]
    DIRECTION OUTPUT ;
    USE SIGNAL ;
    PORT
      LAYER M5 ;
        RECT  33.36 0 33.384 0.084 ;
    END
  END o[76]
  PIN o[77]
    DIRECTION OUTPUT ;
    USE SIGNAL ;
    PORT
      LAYER M5 ;
        RECT  33.456 0 33.48 0.084 ;
    END
  END o[77]
  PIN o[78]
    DIRECTION OUTPUT ;
    USE SIGNAL ;
    PORT
      LAYER M5 ;
        RECT  33.552 0 33.576 0.084 ;
    END
  END o[78]
  PIN o[79]
    DIRECTION OUTPUT ;
    USE SIGNAL ;
    PORT
      LAYER M5 ;
        RECT  33.648 0 33.672 0.084 ;
    END
  END o[79]
  PIN o[7]
    DIRECTION OUTPUT ;
    USE SIGNAL ;
    PORT
      LAYER M5 ;
        RECT  35.952 0 35.976 0.084 ;
    END
  END o[7]
  PIN o[80]
    DIRECTION OUTPUT ;
    USE SIGNAL ;
    PORT
      LAYER M5 ;
        RECT  33.744 0 33.768 0.084 ;
    END
  END o[80]
  PIN o[81]
    DIRECTION OUTPUT ;
    USE SIGNAL ;
    PORT
      LAYER M5 ;
        RECT  33.84 0 33.864 0.084 ;
    END
  END o[81]
  PIN o[82]
    DIRECTION OUTPUT ;
    USE SIGNAL ;
    PORT
      LAYER M5 ;
        RECT  33.936 0 33.96 0.084 ;
    END
  END o[82]
  PIN o[83]
    DIRECTION OUTPUT ;
    USE SIGNAL ;
    PORT
      LAYER M5 ;
        RECT  34.032 0 34.056 0.084 ;
    END
  END o[83]
  PIN o[84]
    DIRECTION OUTPUT ;
    USE SIGNAL ;
    PORT
      LAYER M5 ;
        RECT  34.128 0 34.152 0.084 ;
    END
  END o[84]
  PIN o[85]
    DIRECTION OUTPUT ;
    USE SIGNAL ;
    PORT
      LAYER M5 ;
        RECT  34.224 0 34.248 0.084 ;
    END
  END o[85]
  PIN o[86]
    DIRECTION OUTPUT ;
    USE SIGNAL ;
    PORT
      LAYER M5 ;
        RECT  34.32 0 34.344 0.084 ;
    END
  END o[86]
  PIN o[87]
    DIRECTION OUTPUT ;
    USE SIGNAL ;
    PORT
      LAYER M5 ;
        RECT  34.416 0 34.44 0.084 ;
    END
  END o[87]
  PIN o[88]
    DIRECTION OUTPUT ;
    USE SIGNAL ;
    PORT
      LAYER M5 ;
        RECT  34.512 0 34.536 0.084 ;
    END
  END o[88]
  PIN o[89]
    DIRECTION OUTPUT ;
    USE SIGNAL ;
    PORT
      LAYER M5 ;
        RECT  34.608 0 34.632 0.084 ;
    END
  END o[89]
  PIN o[8]
    DIRECTION OUTPUT ;
    USE SIGNAL ;
    PORT
      LAYER M5 ;
        RECT  36.048 0 36.072 0.084 ;
    END
  END o[8]
  PIN o[90]
    DIRECTION OUTPUT ;
    USE SIGNAL ;
    PORT
      LAYER M5 ;
        RECT  34.704 0 34.728 0.084 ;
    END
  END o[90]
  PIN o[91]
    DIRECTION OUTPUT ;
    USE SIGNAL ;
    PORT
      LAYER M5 ;
        RECT  34.8 0 34.824 0.084 ;
    END
  END o[91]
  PIN o[92]
    DIRECTION OUTPUT ;
    USE SIGNAL ;
    PORT
      LAYER M5 ;
        RECT  34.896 0 34.92 0.084 ;
    END
  END o[92]
  PIN o[93]
    DIRECTION OUTPUT ;
    USE SIGNAL ;
    PORT
      LAYER M5 ;
        RECT  34.992 0 35.016 0.084 ;
    END
  END o[93]
  PIN o[94]
    DIRECTION OUTPUT ;
    USE SIGNAL ;
    PORT
      LAYER M5 ;
        RECT  35.088 0 35.112 0.084 ;
    END
  END o[94]
  PIN o[95]
    DIRECTION OUTPUT ;
    USE SIGNAL ;
    PORT
      LAYER M5 ;
        RECT  35.184 0 35.208 0.084 ;
    END
  END o[95]
  PIN o[96]
    DIRECTION OUTPUT ;
    USE SIGNAL ;
    PORT
      LAYER M5 ;
        RECT  29.136 0 29.16 0.084 ;
    END
  END o[96]
  PIN o[97]
    DIRECTION OUTPUT ;
    USE SIGNAL ;
    PORT
      LAYER M5 ;
        RECT  29.232 0 29.256 0.084 ;
    END
  END o[97]
  PIN o[98]
    DIRECTION OUTPUT ;
    USE SIGNAL ;
    PORT
      LAYER M5 ;
        RECT  29.328 0 29.352 0.084 ;
    END
  END o[98]
  PIN o[99]
    DIRECTION OUTPUT ;
    USE SIGNAL ;
    PORT
      LAYER M5 ;
        RECT  29.424 0 29.448 0.084 ;
    END
  END o[99]
  PIN o[9]
    DIRECTION OUTPUT ;
    USE SIGNAL ;
    PORT
      LAYER M5 ;
        RECT  36.144 0 36.168 0.084 ;
    END
  END o[9]
  PIN rs
    DIRECTION INPUT ;
    USE SIGNAL ;
    PORT
      LAYER M4 ;
        RECT  0 11.28 0.084 11.304 ;
    END
  END rs
  PIN rso
    DIRECTION OUTPUT ;
    USE SIGNAL ;
    PORT
      LAYER M5 ;
        RECT  62.928 0 62.952 0.084 ;
    END
  END rso
  PIN VDD
    DIRECTION INOUT ;
    USE POWER ;
    PORT
      LAYER M5 ;
        RECT  61.992 2.151 62.112 21.609 ;
        RECT  59.292 2.151 59.412 21.609 ;
        RECT  56.592 2.151 56.712 21.609 ;
        RECT  53.892 2.151 54.012 21.609 ;
        RECT  51.192 2.151 51.312 21.609 ;
        RECT  48.492 2.151 48.612 21.609 ;
        RECT  45.792 2.151 45.912 21.609 ;
        RECT  43.092 2.151 43.212 21.609 ;
        RECT  40.392 2.151 40.512 21.609 ;
        RECT  37.692 2.151 37.812 21.609 ;
        RECT  34.992 2.151 35.112 21.609 ;
        RECT  32.292 2.151 32.412 21.609 ;
        RECT  29.592 2.151 29.712 21.609 ;
        RECT  26.892 2.151 27.012 21.609 ;
        RECT  24.192 2.151 24.312 21.609 ;
        RECT  21.492 2.151 21.612 21.609 ;
        RECT  18.792 2.151 18.912 21.609 ;
        RECT  16.092 2.151 16.212 21.609 ;
        RECT  13.392 2.151 13.512 21.609 ;
        RECT  10.692 2.151 10.812 21.609 ;
        RECT  7.992 2.151 8.112 21.609 ;
        RECT  5.292 2.151 5.412 21.609 ;
        RECT  2.592 2.151 2.712 21.609 ;
    END
  END VDD
  PIN VSS
    DIRECTION INOUT ;
    USE GROUND ;
    PORT
      LAYER M5 ;
        RECT  61.8 2.137 61.92 21.623 ;
        RECT  59.1 2.137 59.22 21.623 ;
        RECT  56.4 2.137 56.52 21.623 ;
        RECT  53.7 2.137 53.82 21.623 ;
        RECT  51 2.137 51.12 21.623 ;
        RECT  48.3 2.137 48.42 21.623 ;
        RECT  45.6 2.137 45.72 21.623 ;
        RECT  42.9 2.137 43.02 21.623 ;
        RECT  40.2 2.137 40.32 21.623 ;
        RECT  37.5 2.137 37.62 21.623 ;
        RECT  34.8 2.137 34.92 21.623 ;
        RECT  32.1 2.137 32.22 21.623 ;
        RECT  29.4 2.137 29.52 21.623 ;
        RECT  26.7 2.137 26.82 21.623 ;
        RECT  24 2.137 24.12 21.623 ;
        RECT  21.3 2.137 21.42 21.623 ;
        RECT  18.6 2.137 18.72 21.623 ;
        RECT  15.9 2.137 16.02 21.623 ;
        RECT  13.2 2.137 13.32 21.623 ;
        RECT  10.5 2.137 10.62 21.623 ;
        RECT  7.8 2.137 7.92 21.623 ;
        RECT  5.1 2.137 5.22 21.623 ;
        RECT  2.4 2.137 2.52 21.623 ;
    END
  END VSS
  OBS
    LAYER RVTN ;
     RECT  2.16 2.16 62.64 2.295 ;
     RECT  2.16 2.565 62.64 2.835 ;
     RECT  2.16 3.105 62.64 3.375 ;
     RECT  2.16 3.645 62.64 3.915 ;
     RECT  2.16 4.185 62.64 4.455 ;
     RECT  2.16 4.725 62.64 4.995 ;
     RECT  2.16 5.265 62.64 5.535 ;
     RECT  2.16 5.805 62.64 6.075 ;
     RECT  2.16 6.345 62.64 6.615 ;
     RECT  2.16 6.885 62.64 7.155 ;
     RECT  2.16 7.425 62.64 7.695 ;
     RECT  2.16 7.965 62.64 8.235 ;
     RECT  2.16 8.505 62.64 8.775 ;
     RECT  2.16 9.045 62.64 9.315 ;
     RECT  2.16 9.585 62.64 9.855 ;
     RECT  2.16 10.125 62.64 10.395 ;
     RECT  2.16 10.665 62.64 10.935 ;
     RECT  2.16 11.205 62.64 11.475 ;
     RECT  2.16 11.745 62.64 12.015 ;
     RECT  2.16 12.285 62.64 12.555 ;
     RECT  2.16 12.825 62.64 13.095 ;
     RECT  2.16 13.365 62.64 13.635 ;
     RECT  2.16 13.905 62.64 14.175 ;
     RECT  2.16 14.445 62.64 14.715 ;
     RECT  2.16 14.985 62.64 15.255 ;
     RECT  2.16 15.525 62.64 15.795 ;
     RECT  2.16 16.065 62.64 16.335 ;
     RECT  2.16 16.605 62.64 16.875 ;
     RECT  2.16 17.145 62.64 17.415 ;
     RECT  2.16 17.685 62.64 17.955 ;
     RECT  2.16 18.225 62.64 18.495 ;
     RECT  2.16 18.765 62.64 19.035 ;
     RECT  2.16 19.305 62.64 19.575 ;
     RECT  2.16 19.845 62.64 20.115 ;
     RECT  2.16 20.385 62.64 20.655 ;
     RECT  2.16 20.925 62.64 21.195 ;
     RECT  2.16 21.465 62.64 21.6 ;
    LAYER RVTP ;
     RECT  2.16 2.295 62.64 2.565 ;
     RECT  2.16 2.835 62.64 3.105 ;
     RECT  2.16 3.375 62.64 3.645 ;
     RECT  2.16 3.915 62.64 4.185 ;
     RECT  2.16 4.455 62.64 4.725 ;
     RECT  2.16 4.995 62.64 5.265 ;
     RECT  2.16 5.535 62.64 5.805 ;
     RECT  2.16 6.075 62.64 6.345 ;
     RECT  2.16 6.615 62.64 6.885 ;
     RECT  2.16 7.155 62.64 7.425 ;
     RECT  2.16 7.695 62.64 7.965 ;
     RECT  2.16 8.235 62.64 8.505 ;
     RECT  2.16 8.775 62.64 9.045 ;
     RECT  2.16 9.315 62.64 9.585 ;
     RECT  2.16 9.855 62.64 10.125 ;
     RECT  2.16 10.395 62.64 10.665 ;
     RECT  2.16 10.935 62.64 11.205 ;
     RECT  2.16 11.475 62.64 11.745 ;
     RECT  2.16 12.015 62.64 12.285 ;
     RECT  2.16 12.555 62.64 12.825 ;
     RECT  2.16 13.095 62.64 13.365 ;
     RECT  2.16 13.635 62.64 13.905 ;
     RECT  2.16 14.175 62.64 14.445 ;
     RECT  2.16 14.715 62.64 14.985 ;
     RECT  2.16 15.255 62.64 15.525 ;
     RECT  2.16 15.795 62.64 16.065 ;
     RECT  2.16 16.335 62.64 16.605 ;
     RECT  2.16 16.875 62.64 17.145 ;
     RECT  2.16 17.415 62.64 17.685 ;
     RECT  2.16 17.955 62.64 18.225 ;
     RECT  2.16 18.495 62.64 18.765 ;
     RECT  2.16 19.035 62.64 19.305 ;
     RECT  2.16 19.575 62.64 19.845 ;
     RECT  2.16 20.115 62.64 20.385 ;
     RECT  2.16 20.655 62.64 20.925 ;
     RECT  2.16 21.195 62.64 21.465 ;
    LAYER M1 ;
     RECT  2.16 2.151 62.64 21.609 ;
    LAYER M2 ;
     RECT  1.543 2.808 1.579 2.826 ;
     RECT  1.543 5.814 1.615 5.832 ;
     RECT  1.615 4.266 1.651 4.284 ;
     RECT  1.615 5.814 1.651 5.904 ;
     RECT  1.579 2.646 1.687 2.826 ;
     RECT  1.687 2.646 1.723 2.898 ;
     RECT  1.579 10.206 1.723 10.224 ;
     RECT  1.723 2.268 1.795 2.898 ;
     RECT  1.795 7.776 1.867 7.794 ;
     RECT  1.651 3.816 1.903 4.284 ;
     RECT  1.867 7.776 2.011 8.064 ;
     RECT  1.795 1.962 2.047 2.898 ;
     RECT  1.903 3.816 2.047 4.446 ;
     RECT  1.723 9.666 2.047 10.224 ;
     RECT  2.047 9.126 2.119 10.224 ;
     RECT  1.759 11.286 2.119 11.304 ;
     RECT  1.651 5.814 2.155 6.174 ;
     RECT  2.047 1.962 2.16 4.446 ;
     RECT  2.155 5.814 2.16 6.444 ;
     RECT  2.011 7.776 2.16 8.334 ;
     RECT  2.119 9.126 2.16 11.304 ;
     RECT  1.939 12.528 2.16 12.546 ;
     RECT  2.16 1.962 2.983 21.609 ;
     RECT  2.983 1.962 3.487 21.654 ;
     RECT  3.487 1.926 3.559 21.654 ;
     RECT  3.559 1.881 5.927 21.654 ;
     RECT  5.927 1.926 6.719 21.654 ;
     RECT  6.475 1.152 6.755 1.17 ;
     RECT  6.719 2.07 7.151 21.654 ;
     RECT  7.151 2.106 7.987 21.654 ;
     RECT  7.987 2.07 8.339 21.654 ;
     RECT  8.779 1.224 8.851 1.242 ;
     RECT  8.851 1.152 8.951 1.242 ;
     RECT  8.951 1.224 9.023 1.242 ;
     RECT  8.339 2.106 9.283 21.654 ;
     RECT  9.283 2.106 9.355 21.726 ;
     RECT  9.355 2.034 9.571 21.726 ;
     RECT  9.571 1.962 10.283 21.726 ;
     RECT  10.283 2.106 11.003 21.726 ;
     RECT  11.003 2.106 12.271 21.654 ;
     RECT  12.271 2.034 13.135 21.654 ;
     RECT  13.135 1.998 13.523 21.654 ;
     RECT  13.523 2.034 13.631 21.654 ;
     RECT  13.631 2.106 14.207 21.654 ;
     RECT  14.207 2.151 15.367 21.654 ;
     RECT  15.367 2.07 16.007 21.654 ;
     RECT  16.007 2.106 16.727 21.654 ;
     RECT  16.727 2.151 17.887 21.654 ;
     RECT  17.887 2.106 17.951 21.654 ;
     RECT  17.951 2.106 18.067 21.609 ;
     RECT  18.067 2.034 19.039 21.609 ;
     RECT  19.039 1.962 20.515 21.609 ;
     RECT  20.515 1.962 21.083 21.654 ;
     RECT  23.107 1.152 23.755 1.17 ;
     RECT  21.083 2.034 23.755 21.654 ;
     RECT  23.755 1.152 23.927 21.654 ;
     RECT  23.927 1.881 24.719 21.654 ;
     RECT  24.719 1.962 24.899 21.654 ;
     RECT  24.899 1.998 26.131 21.654 ;
     RECT  26.131 1.926 27.923 21.654 ;
     RECT  27.923 2.151 29.047 21.654 ;
     RECT  29.047 2.034 29.687 21.654 ;
     RECT  29.687 2.106 30.263 21.654 ;
     RECT  30.263 2.151 32.071 21.654 ;
     RECT  32.071 2.106 33.503 21.654 ;
     RECT  33.503 2.106 34.159 21.609 ;
     RECT  33.691 1.152 34.583 1.17 ;
     RECT  34.159 2.034 35.591 21.609 ;
     RECT  35.671 1.224 35.743 1.242 ;
     RECT  35.743 1.152 35.915 1.242 ;
     RECT  35.591 2.151 36.391 21.609 ;
     RECT  36.391 2.151 37.291 21.654 ;
     RECT  37.939 1.152 38.039 1.17 ;
     RECT  37.291 2.106 39.083 21.654 ;
     RECT  39.083 2.151 40.999 21.654 ;
     RECT  40.999 2.034 42.107 21.654 ;
     RECT  42.107 2.151 43.231 21.654 ;
     RECT  43.231 2.106 43.763 21.654 ;
     RECT  43.763 2.106 43.943 21.609 ;
     RECT  44.275 1.152 44.411 1.17 ;
     RECT  43.943 2.151 44.671 21.609 ;
     RECT  44.671 2.106 45.175 21.609 ;
     RECT  45.175 2.106 46.003 21.654 ;
     RECT  46.003 2.034 46.895 21.654 ;
     RECT  46.895 2.106 48.163 21.654 ;
     RECT  48.163 2.07 49.099 21.654 ;
     RECT  49.099 1.962 49.891 21.654 ;
     RECT  49.891 1.881 52.043 21.654 ;
     RECT  52.043 2.106 53.239 21.654 ;
     RECT  53.239 1.998 54.131 21.654 ;
     RECT  54.131 2.07 54.203 21.654 ;
     RECT  54.203 2.106 55.859 21.654 ;
     RECT  55.859 2.106 56.083 21.609 ;
     RECT  56.083 2.07 56.623 21.609 ;
     RECT  56.623 1.998 56.903 21.609 ;
     RECT  57.667 1.152 57.875 1.17 ;
     RECT  56.903 2.151 58.099 21.609 ;
     RECT  58.711 1.224 58.783 1.242 ;
     RECT  58.783 1.152 58.955 1.242 ;
     RECT  58.955 1.224 58.991 1.242 ;
     RECT  58.099 2.106 59.287 21.609 ;
     RECT  59.287 2.07 59.323 21.609 ;
     RECT  59.323 1.881 61.195 21.609 ;
     RECT  61.195 1.152 61.367 21.609 ;
     RECT  61.367 1.881 62.195 21.609 ;
     RECT  62.195 1.962 62.64 21.609 ;
     RECT  62.64 4.698 62.663 5.364 ;
     RECT  62.64 10.296 62.663 12.744 ;
     RECT  62.64 17.082 62.663 19.764 ;
     RECT  62.64 6.354 62.699 7.254 ;
     RECT  62.699 6.354 62.735 6.642 ;
     RECT  62.663 18.468 62.735 19.332 ;
     RECT  62.735 19.314 62.771 19.332 ;
     RECT  62.64 1.962 62.879 2.862 ;
     RECT  62.663 10.296 62.879 12.474 ;
     RECT  62.735 6.624 62.951 6.642 ;
     RECT  62.735 18.468 62.987 18.558 ;
     RECT  62.663 4.698 63.059 5.292 ;
     RECT  63.059 4.698 63.095 4.716 ;
     RECT  62.879 2.034 63.239 2.862 ;
     RECT  62.879 10.638 63.239 12.474 ;
     RECT  63.239 2.268 63.311 2.862 ;
     RECT  62.64 13.536 63.311 14.004 ;
     RECT  62.663 17.082 63.311 17.406 ;
     RECT  62.987 18.54 63.311 18.558 ;
     RECT  63.311 13.536 63.347 13.554 ;
     RECT  63.311 2.268 63.383 2.826 ;
     RECT  63.239 11.376 63.383 12.474 ;
     RECT  63.383 2.268 63.419 2.754 ;
     RECT  63.383 11.376 63.419 11.934 ;
     RECT  63.419 2.34 63.455 2.754 ;
     RECT  63.419 11.376 63.455 11.664 ;
     RECT  63.455 2.736 63.527 2.754 ;
     RECT  63.455 11.376 63.527 11.394 ;
     RECT  63.311 17.082 63.815 17.1 ;
    LAYER M3 ;
     RECT  27.972 0.043 27.99 0.091 ;
     RECT  27.288 0.091 28.386 0.139 ;
     RECT  32.04 0.091 32.058 0.139 ;
     RECT  32.976 0.091 32.994 0.139 ;
     RECT  25.884 0.043 25.902 0.173 ;
     RECT  39.78 0.091 39.798 0.187 ;
     RECT  40.824 0.091 40.842 0.187 ;
     RECT  4.932 0.091 5.67 0.221 ;
     RECT  45 0.091 45.018 0.221 ;
     RECT  3.024 0.139 3.042 0.235 ;
     RECT  15.66 0.091 16.11 0.269 ;
     RECT  27.144 0.139 28.386 0.269 ;
     RECT  47.052 0.091 47.07 0.269 ;
     RECT  49.032 0.091 49.05 0.269 ;
     RECT  15.768 0.269 16.11 0.317 ;
     RECT  24.732 0.091 24.894 0.317 ;
     RECT  27.144 0.269 27.99 0.317 ;
     RECT  39.708 0.187 39.798 0.317 ;
     RECT  3.024 0.235 3.114 0.365 ;
     RECT  12.564 0.091 12.582 0.365 ;
     RECT  27.288 0.317 27.99 0.365 ;
     RECT  39.708 0.317 39.726 0.365 ;
     RECT  3.096 0.365 3.114 0.413 ;
     RECT  58.428 0.091 58.446 0.475 ;
     RECT  35.892 0.091 35.91 0.523 ;
     RECT  7.056 0.523 7.074 0.571 ;
     RECT  8.496 0.091 8.514 0.571 ;
     RECT  11.952 0.475 11.97 0.571 ;
     RECT  14.04 0.523 14.058 0.571 ;
     RECT  17.496 0.091 17.514 0.571 ;
     RECT  22.572 0.091 22.59 0.571 ;
     RECT  23.904 0.187 23.922 0.571 ;
     RECT  30.924 0.091 30.942 0.571 ;
     RECT  32.04 0.139 32.994 0.571 ;
     RECT  35.676 0.523 35.91 0.571 ;
     RECT  40.788 0.187 40.842 0.571 ;
     RECT  52.056 0.091 53.262 0.571 ;
     RECT  58.428 0.475 58.986 0.571 ;
     RECT  49.968 0.091 49.986 0.605 ;
     RECT  6.48 0.571 7.074 0.619 ;
     RECT  8.496 0.571 8.766 0.619 ;
     RECT  10.08 0.571 10.098 0.619 ;
     RECT  52.056 0.571 53.37 0.653 ;
     RECT  30.924 0.571 31.158 0.667 ;
     RECT  32.04 0.571 33.714 0.667 ;
     RECT  34.488 0.619 34.506 0.667 ;
     RECT  63.036 0.571 63.054 0.667 ;
     RECT  32.04 0.667 34.506 0.701 ;
     RECT  56.88 0.091 56.898 0.701 ;
     RECT  9.972 0.619 10.098 0.715 ;
     RECT  8.496 0.619 8.874 0.749 ;
     RECT  5.724 0.763 5.742 0.811 ;
     RECT  6.48 0.619 7.506 0.811 ;
     RECT  5.724 0.811 7.506 0.941 ;
     RECT  50.868 0.571 50.886 1.099 ;
     RECT  57.852 0.571 59.706 1.099 ;
     RECT  8.748 0.749 8.874 1.147 ;
     RECT  17.316 0.571 17.514 1.147 ;
     RECT  25.452 0.571 25.614 1.147 ;
     RECT  33.696 0.701 34.506 1.147 ;
     RECT  38.016 0.523 38.034 1.147 ;
     RECT  44.388 0.571 44.406 1.147 ;
     RECT  57.852 1.099 60.03 1.147 ;
     RECT  61.2 0.091 61.218 1.147 ;
     RECT  33.696 1.147 34.578 1.175 ;
     RECT  61.2 1.147 61.362 1.175 ;
     RECT  3.132 1.147 3.15 1.195 ;
     RECT  40.788 0.571 41.202 1.195 ;
     RECT  41.94 1.147 41.958 1.195 ;
     RECT  8.748 1.147 8.946 1.219 ;
     RECT  9.684 0.715 10.098 1.219 ;
     RECT  11.088 1.099 11.106 1.675 ;
     RECT  11.916 0.571 11.97 1.675 ;
     RECT  14.04 0.571 14.526 1.675 ;
     RECT  22.572 0.571 23.922 1.675 ;
     RECT  30.888 0.667 31.158 1.675 ;
     RECT  4.932 0.221 4.95 1.723 ;
     RECT  6.012 0.941 7.506 1.723 ;
     RECT  8.748 1.219 10.098 1.723 ;
     RECT  11.088 1.675 11.97 1.723 ;
     RECT  13.536 1.675 14.526 1.723 ;
     RECT  17.028 1.147 17.514 1.723 ;
     RECT  20.124 1.147 20.142 1.723 ;
     RECT  22.104 1.675 23.922 1.723 ;
     RECT  25.056 1.147 25.614 1.723 ;
     RECT  30.312 1.675 31.158 1.723 ;
     RECT  32.04 0.701 32.31 1.723 ;
     RECT  33.948 1.175 34.578 1.723 ;
     RECT  35.676 0.571 36.45 1.723 ;
     RECT  37.944 1.147 38.034 1.723 ;
     RECT  39.636 1.147 39.654 1.723 ;
     RECT  40.788 1.195 41.958 1.723 ;
     RECT  44.28 1.147 44.406 1.723 ;
     RECT  45.144 1.099 45.162 1.723 ;
     RECT  46.116 0.091 46.134 1.723 ;
     RECT  47.304 0.571 47.358 1.723 ;
     RECT  50.868 1.099 51.174 1.723 ;
     RECT  52.056 0.653 52.614 1.723 ;
     RECT  54.252 0.619 54.27 1.723 ;
     RECT  57.672 1.147 60.03 1.723 ;
     RECT  19.944 1.723 20.502 1.771 ;
     RECT  39.348 1.723 39.654 1.771 ;
     RECT  44.172 1.723 45.162 1.771 ;
     RECT  49.464 1.723 49.482 1.771 ;
     RECT  50.868 1.723 52.614 1.771 ;
     RECT  53.352 0.653 53.37 1.771 ;
     RECT  54.252 1.723 54.558 1.771 ;
     RECT  56.232 1.723 56.25 1.771 ;
     RECT  57.06 1.723 60.354 1.771 ;
     RECT  29.808 1.723 32.958 1.819 ;
     RECT  39.024 1.771 39.654 1.819 ;
     RECT  40.788 1.723 42.57 1.819 ;
     RECT  43.632 1.771 45.162 1.819 ;
     RECT  47.304 1.723 47.502 1.819 ;
     RECT  54.252 1.771 55.062 1.819 ;
     RECT  49.212 1.771 49.482 1.867 ;
     RECT  3.132 1.195 3.222 1.876 ;
     RECT  6.012 1.723 10.098 1.876 ;
     RECT  48.924 1.867 49.482 1.876 ;
     RECT  11.088 1.723 14.814 1.915 ;
     RECT  40.788 1.819 42.606 1.915 ;
     RECT  43.56 1.819 45.162 1.915 ;
     RECT  46.116 1.723 46.566 1.915 ;
     RECT  22.104 1.723 25.614 1.921 ;
     RECT  26.424 1.099 26.442 1.921 ;
     RECT  27.972 0.365 27.99 1.921 ;
     RECT  3.132 1.876 3.582 1.957 ;
     RECT  5.904 1.876 10.098 1.957 ;
     RECT  19.944 1.771 21.006 1.957 ;
     RECT  48.924 1.876 49.914 1.957 ;
     RECT  61.344 1.175 61.362 1.957 ;
     RECT  62.172 1.876 62.19 1.957 ;
     RECT  63.036 0.667 63.09 1.957 ;
     RECT  27.9 1.921 27.99 1.963 ;
     RECT  28.98 1.147 28.998 1.963 ;
     RECT  48.924 1.957 49.95 1.963 ;
     RECT  2.988 1.957 3.582 1.993 ;
     RECT  4.536 1.723 4.95 1.993 ;
     RECT  48.816 1.963 49.95 1.993 ;
     RECT  50.868 1.771 53.37 1.993 ;
     RECT  54.252 1.819 55.494 1.993 ;
     RECT  2.988 1.993 4.95 2.011 ;
     RECT  22.104 1.921 26.442 2.011 ;
     RECT  27.9 1.963 28.998 2.011 ;
     RECT  29.808 1.819 33.03 2.011 ;
     RECT  37.944 1.723 38.142 2.011 ;
     RECT  38.88 1.819 39.654 2.011 ;
     RECT  40.788 1.915 45.162 2.011 ;
     RECT  56.232 1.771 60.354 2.011 ;
     RECT  61.344 1.957 63.09 2.011 ;
     RECT  1.8 1.957 1.818 2.029 ;
     RECT  19.044 1.957 19.062 2.029 ;
     RECT  19.944 1.957 21.078 2.029 ;
     RECT  22.068 2.011 26.442 2.029 ;
     RECT  27.612 2.011 28.998 2.029 ;
     RECT  29.736 2.011 33.03 2.029 ;
     RECT  46.044 1.915 46.566 2.029 ;
     RECT  47.304 1.819 47.754 2.029 ;
     RECT  56.232 2.011 63.09 2.029 ;
     RECT  16.092 0.317 16.11 2.056 ;
     RECT  1.8 2.029 1.89 2.065 ;
     RECT  2.736 2.011 4.95 2.065 ;
     RECT  5.76 1.957 10.278 2.065 ;
     RECT  11.016 1.915 14.814 2.065 ;
     RECT  15.984 2.056 16.11 2.065 ;
     RECT  46.008 2.029 47.754 2.065 ;
     RECT  48.816 1.993 53.37 2.065 ;
     RECT  54.108 1.993 55.494 2.065 ;
     RECT  56.232 2.029 63.234 2.065 ;
     RECT  11.016 2.065 16.11 2.101 ;
     RECT  16.884 1.723 18.162 2.101 ;
     RECT  19.044 2.029 26.442 2.101 ;
     RECT  27.612 2.029 33.03 2.101 ;
     RECT  33.948 1.723 37.098 2.101 ;
     RECT  37.944 2.011 45.162 2.101 ;
     RECT  46.008 2.065 63.234 2.101 ;
     RECT  1.8 2.065 4.95 2.143 ;
     RECT  5.724 2.065 10.278 2.143 ;
     RECT  11.016 2.101 18.162 2.143 ;
     RECT  18.936 2.101 26.442 2.143 ;
     RECT  27.36 2.101 63.234 2.143 ;
     RECT  1.8 2.143 63.234 2.263 ;
     RECT  1.728 2.263 63.414 2.335 ;
     RECT  1.728 2.335 63.45 2.641 ;
     RECT  1.584 2.641 63.45 2.731 ;
     RECT  1.584 2.731 63.522 2.803 ;
     RECT  1.548 2.803 63.522 5.837 ;
     RECT  1.584 5.837 63.522 10.229 ;
     RECT  0.324 11.179 0.342 11.309 ;
     RECT  1.764 10.229 63.522 11.309 ;
     RECT  1.944 11.309 63.522 11.399 ;
     RECT  1.944 11.399 63.45 11.669 ;
     RECT  1.944 11.669 63.414 11.939 ;
     RECT  1.944 11.939 63.378 12.479 ;
     RECT  1.944 12.479 63.342 12.551 ;
     RECT  2.376 12.551 63.342 12.749 ;
     RECT  2.376 12.749 62.478 13.019 ;
     RECT  63.288 12.749 63.342 13.559 ;
     RECT  63.288 13.559 63.306 14.009 ;
     RECT  2.376 13.019 62.097 14.791 ;
     RECT  2.304 14.791 62.097 16.951 ;
     RECT  2.304 16.951 62.586 17.383 ;
     RECT  63.792 17.077 63.81 17.383 ;
     RECT  2.304 17.383 63.81 19.615 ;
     RECT  2.196 19.615 63.81 21.341 ;
     RECT  2.34 21.341 63.81 21.389 ;
     RECT  2.34 21.389 3.474 21.461 ;
     RECT  29.232 21.389 32.526 21.461 ;
     RECT  9.144 21.389 28.062 21.497 ;
     RECT  38.592 21.389 51.894 21.497 ;
     RECT  52.92 21.389 63.81 21.497 ;
     RECT  9.144 21.497 9.342 21.533 ;
     RECT  10.116 21.497 28.062 21.533 ;
     RECT  31.608 21.461 32.526 21.539 ;
     RECT  6.804 21.389 8.19 21.569 ;
     RECT  10.116 21.533 27.81 21.569 ;
     RECT  29.232 21.461 30.87 21.569 ;
     RECT  31.86 21.539 32.526 21.569 ;
     RECT  33.48 21.389 37.854 21.569 ;
     RECT  6.984 21.569 8.19 21.581 ;
     RECT  29.34 21.569 30.762 21.581 ;
     RECT  4.464 21.389 6.066 21.617 ;
     RECT  38.592 21.497 49.338 21.617 ;
     RECT  53.715 21.497 63.81 21.617 ;
     RECT  4.464 21.617 4.59 21.629 ;
     RECT  9.216 21.533 9.342 21.629 ;
     RECT  10.116 21.569 19.422 21.629 ;
     RECT  30.744 21.581 30.762 21.629 ;
     RECT  34.488 21.569 35.586 21.629 ;
     RECT  38.592 21.617 42.318 21.629 ;
     RECT  56.736 21.617 63.81 21.629 ;
     RECT  7.056 21.581 8.19 21.659 ;
     RECT  17.316 21.629 19.422 21.659 ;
     RECT  20.52 21.569 25.11 21.659 ;
     RECT  29.34 21.581 29.646 21.659 ;
     RECT  33.48 21.569 33.75 21.659 ;
     RECT  36.396 21.569 37.854 21.659 ;
     RECT  43.056 21.617 49.338 21.659 ;
     RECT  54.036 21.617 55.854 21.659 ;
     RECT  4.464 21.629 4.482 21.677 ;
     RECT  7.488 21.659 8.19 21.677 ;
     RECT  9.216 21.629 9.306 21.677 ;
     RECT  10.116 21.629 14.346 21.677 ;
     RECT  15.264 21.629 16.506 21.677 ;
     RECT  17.316 21.659 17.334 21.677 ;
     RECT  18.18 21.659 19.422 21.677 ;
     RECT  20.772 21.659 22.986 21.677 ;
     RECT  23.904 21.659 25.11 21.677 ;
     RECT  26.208 21.569 27.378 21.677 ;
     RECT  33.732 21.659 33.75 21.677 ;
     RECT  34.632 21.629 35.586 21.677 ;
     RECT  36.756 21.659 37.854 21.677 ;
     RECT  38.592 21.629 41.022 21.677 ;
     RECT  41.832 21.629 42.318 21.677 ;
     RECT  43.056 21.659 44.91 21.677 ;
     RECT  45.756 21.659 49.338 21.677 ;
     RECT  50.364 21.497 51.894 21.677 ;
     RECT  56.736 21.629 59.526 21.677 ;
     RECT  60.444 21.629 63.81 21.677 ;
     RECT  7.704 21.677 8.19 21.725 ;
     RECT  13.176 21.677 13.77 21.725 ;
     RECT  15.84 21.677 16.29 21.725 ;
     RECT  29.376 21.659 29.646 21.725 ;
     RECT  32.04 21.569 32.526 21.725 ;
     RECT  37.476 21.677 37.854 21.725 ;
     RECT  40.536 21.677 40.626 21.725 ;
     RECT  43.056 21.677 43.29 21.725 ;
     RECT  51.156 21.677 51.894 21.725 ;
     RECT  54.036 21.659 55.35 21.725 ;
     RECT  56.736 21.677 58.086 21.725 ;
     RECT  9.288 21.677 9.306 21.731 ;
     RECT  10.116 21.677 10.998 21.731 ;
     RECT  2.34 21.461 3.294 21.773 ;
     RECT  7.956 21.725 8.19 21.773 ;
     RECT  13.176 21.725 13.698 21.773 ;
     RECT  18.18 21.677 19.062 21.773 ;
     RECT  21.456 21.677 22.23 21.773 ;
     RECT  29.376 21.725 29.394 21.773 ;
     RECT  34.956 21.677 35.586 21.773 ;
     RECT  40.572 21.725 40.626 21.773 ;
     RECT  43.056 21.725 43.254 21.773 ;
     RECT  45.756 21.677 46.17 21.773 ;
     RECT  48.24 21.677 49.05 21.773 ;
     RECT  54.072 21.725 55.35 21.773 ;
     RECT  59.04 21.677 59.526 21.773 ;
     RECT  60.876 21.677 61.794 21.773 ;
     RECT  8.172 21.773 8.19 21.821 ;
     RECT  10.116 21.731 10.854 21.821 ;
     RECT  18.936 21.773 19.062 21.821 ;
     RECT  21.636 21.773 22.23 21.821 ;
     RECT  26.208 21.677 27.09 21.821 ;
     RECT  32.076 21.725 32.526 21.821 ;
     RECT  43.236 21.773 43.254 21.821 ;
     RECT  45.936 21.773 46.17 21.821 ;
     RECT  56.808 21.725 58.086 21.821 ;
     RECT  2.376 21.773 3.294 21.869 ;
     RECT  5.472 21.617 6.066 21.869 ;
     RECT  18.936 21.821 18.954 21.869 ;
     RECT  23.94 21.677 25.11 21.869 ;
     RECT  26.208 21.821 26.694 21.869 ;
     RECT  5.976 21.869 6.066 22.205 ;
     RECT  22.968 21.677 22.986 22.205 ;
     RECT  10.836 21.821 10.854 22.253 ;
     RECT  18.18 21.773 18.198 22.253 ;
     RECT  24.48 21.869 25.11 22.253 ;
     RECT  49.032 21.773 49.05 22.253 ;
     RECT  57.24 21.821 58.086 22.253 ;
     RECT  60.876 21.773 61.758 22.253 ;
     RECT  62.568 21.677 63.81 22.253 ;
     RECT  57.24 22.253 57.942 22.301 ;
     RECT  51.336 21.725 51.894 22.493 ;
     RECT  2.736 21.869 3.294 22.781 ;
     RECT  44.424 21.677 44.442 22.781 ;
     RECT  46.152 21.821 46.17 22.781 ;
     RECT  3.096 22.781 3.294 22.829 ;
     RECT  15.84 21.725 15.858 22.829 ;
     RECT  22.212 21.821 22.23 22.829 ;
     RECT  26.208 21.869 26.226 22.829 ;
     RECT  61.74 22.253 61.758 22.829 ;
     RECT  63.792 22.253 63.81 22.829 ;
     RECT  3.096 22.829 3.222 22.877 ;
     RECT  60.876 22.253 60.894 22.877 ;
     RECT  62.964 22.253 62.982 22.925 ;
     RECT  32.508 21.821 32.526 23.131 ;
     RECT  24.48 22.253 24.498 23.165 ;
     RECT  29.268 23.083 29.286 23.261 ;
     RECT  40.572 21.773 40.59 23.275 ;
     RECT  57.24 22.301 57.258 23.275 ;
     RECT  31.932 23.131 32.526 23.309 ;
     RECT  35.352 21.773 35.586 23.419 ;
     RECT  48.816 23.371 48.834 23.419 ;
     RECT  21.816 23.323 21.834 23.453 ;
     RECT  29.808 23.371 29.826 23.467 ;
     RECT  38.448 23.371 38.466 23.501 ;
     RECT  54.072 21.773 54.63 23.515 ;
     RECT  56.844 23.275 57.258 23.515 ;
     RECT  35.28 23.419 35.586 23.549 ;
     RECT  29.808 23.467 29.898 23.597 ;
     RECT  35.352 23.549 35.586 23.597 ;
     RECT  39.996 23.275 40.59 23.597 ;
     RECT  48.816 23.419 48.906 23.597 ;
     RECT  51.336 22.493 51.462 23.597 ;
     RECT  53.532 23.515 54.63 23.597 ;
     RECT  3.096 22.877 3.114 23.645 ;
     RECT  6.048 22.205 6.066 23.645 ;
     RECT  13.68 21.773 13.698 23.645 ;
     RECT  19.368 23.515 19.386 23.645 ;
     RECT  29.88 23.597 29.898 23.645 ;
     RECT  32.508 23.309 32.526 23.645 ;
     RECT  35.568 23.597 35.586 23.645 ;
     RECT  40.068 23.597 40.59 23.645 ;
     RECT  43.38 23.515 43.398 23.645 ;
     RECT  48.816 23.597 48.834 23.645 ;
     RECT  51.444 23.597 51.462 23.645 ;
     RECT  52.776 23.515 52.794 23.645 ;
     RECT  53.532 23.597 54.09 23.645 ;
     RECT  56.196 23.515 57.582 23.645 ;
     RECT  60.336 23.419 60.354 23.645 ;
     RECT  61.38 23.371 61.614 23.645 ;
    LAYER M4 ;
     RECT  0.06 11.184 0.353 11.304 ;
     RECT  0.709 2.784 0.901 2.808 ;
     RECT  0.805 3.984 0.901 4.008 ;
     RECT  0.901 2.784 1.189 4.008 ;
     RECT  1.189 2.784 1.381 4.056 ;
     RECT  1.381 2.784 1.573 4.584 ;
     RECT  1.861 21.12 1.957 21.144 ;
     RECT  1.957 21.12 2.053 21.24 ;
     RECT  0.133 10.08 2.077 10.104 ;
     RECT  1.573 2.784 2.156 4.68 ;
     RECT  2.053 20.16 2.185 21.24 ;
     RECT  2.156 2.784 2.245 5.064 ;
     RECT  1.957 0.096 2.293 0.12 ;
     RECT  2.185 20.16 2.293 21.336 ;
     RECT  2.257 8.544 2.329 8.568 ;
     RECT  2.293 19.872 2.329 21.336 ;
     RECT  2.293 6.288 2.365 6.312 ;
     RECT  2.329 8.544 2.365 8.808 ;
     RECT  2.329 19.872 2.365 21.768 ;
     RECT  2.245 2.784 2.401 5.16 ;
     RECT  2.365 6.288 2.401 6.84 ;
     RECT  2.401 2.784 2.408 6.84 ;
     RECT  2.365 8.016 2.408 8.808 ;
     RECT  2.077 9.792 2.408 10.104 ;
     RECT  0.353 11.184 2.408 11.208 ;
     RECT  2.365 19.872 2.408 21.864 ;
     RECT  2.293 0.096 2.437 0.312 ;
     RECT  2.408 2.148 2.579 21.864 ;
     RECT  2.293 23.568 2.629 23.592 ;
     RECT  2.579 2.148 2.677 21.342 ;
     RECT  2.677 1.92 2.704 21.342 ;
     RECT  2.629 23.376 2.725 23.592 ;
     RECT  2.725 22.752 2.821 23.592 ;
     RECT  2.437 0.096 3.013 0.408 ;
     RECT  2.704 1.92 3.013 11.496 ;
     RECT  3.013 0.096 3.017 11.496 ;
     RECT  2.704 18.48 3.1 21.24 ;
     RECT  2.821 22.752 3.125 23.64 ;
     RECT  3.1 19.632 3.413 21.24 ;
     RECT  3.125 22.752 3.443 22.872 ;
     RECT  3.443 22.8 3.539 22.872 ;
     RECT  2.704 17.424 3.733 17.448 ;
     RECT  3.1 18.48 3.733 18.504 ;
     RECT  3.413 19.872 3.733 21.24 ;
     RECT  3.539 22.848 3.827 22.872 ;
     RECT  3.733 17.424 4.273 18.504 ;
     RECT  3.733 14.784 4.381 14.808 ;
     RECT  3.733 19.872 4.453 21.288 ;
     RECT  4.645 23.568 4.885 23.592 ;
     RECT  3.017 0.096 4.921 11.208 ;
     RECT  4.921 0.096 5.108 11.256 ;
     RECT  4.381 14.784 5.108 15.048 ;
     RECT  4.273 17.088 5.108 18.504 ;
     RECT  4.453 19.872 5.108 21.672 ;
     RECT  4.885 23.472 5.125 23.592 ;
     RECT  5.125 23.376 5.221 23.592 ;
     RECT  5.108 0.096 5.317 21.672 ;
     RECT  5.317 0.096 5.404 21.72 ;
     RECT  5.404 19.824 5.413 21.72 ;
     RECT  5.413 19.824 5.42 21.768 ;
     RECT  5.221 23.328 5.509 23.592 ;
     RECT  5.509 23.328 5.651 23.64 ;
     RECT  5.404 0.096 5.681 12.504 ;
     RECT  5.651 23.568 5.891 23.64 ;
     RECT  5.42 19.824 5.965 21.864 ;
     RECT  5.965 19.824 6.049 22.2 ;
     RECT  5.891 23.616 6.077 23.64 ;
     RECT  6.049 19.824 6.257 21.576 ;
     RECT  5.404 15.168 6.829 15.192 ;
     RECT  6.257 19.872 7.477 21.576 ;
     RECT  7.477 19.872 7.669 21.672 ;
     RECT  5.681 0.192 7.808 12.504 ;
     RECT  6.829 15.168 7.808 15.288 ;
     RECT  6.565 16.272 7.808 16.296 ;
     RECT  5.404 17.424 7.808 18.504 ;
     RECT  7.669 19.872 7.808 21.816 ;
     RECT  7.808 0.192 8.053 21.816 ;
     RECT  8.053 0.144 8.104 21.816 ;
     RECT  8.104 19.92 8.201 21.816 ;
     RECT  8.104 0.144 8.317 11.736 ;
     RECT  8.317 0.144 8.475 5.304 ;
     RECT  8.475 0.096 8.569 5.304 ;
     RECT  8.201 19.92 9.133 21.672 ;
     RECT  8.104 16.272 9.529 16.296 ;
     RECT  8.104 17.424 9.529 18.504 ;
     RECT  8.569 0.144 9.635 5.304 ;
     RECT  9.635 0.576 9.781 5.304 ;
     RECT  8.317 6.288 9.781 11.736 ;
     RECT  8.104 15.264 10.033 15.288 ;
     RECT  9.133 19.824 10.105 21.672 ;
     RECT  10.261 23.568 10.357 23.592 ;
     RECT  10.357 23.472 10.451 23.592 ;
     RECT  9.781 0.576 10.508 11.736 ;
     RECT  10.033 14.784 10.508 15.288 ;
     RECT  9.529 16.272 10.508 18.504 ;
     RECT  10.105 19.824 10.508 21.816 ;
     RECT  10.451 23.472 10.547 23.496 ;
     RECT  10.508 0.576 10.804 21.816 ;
     RECT  10.804 19.488 10.825 21.816 ;
     RECT  10.804 0.576 10.865 11.736 ;
     RECT  10.804 15.168 10.865 15.288 ;
     RECT  10.804 16.272 10.931 18.504 ;
     RECT  10.825 19.488 11.123 22.248 ;
     RECT  10.865 0.576 11.221 5.16 ;
     RECT  11.221 0.144 11.363 5.16 ;
     RECT  11.363 1.68 11.405 5.16 ;
     RECT  11.363 0.144 11.411 0.6 ;
     RECT  10.931 16.272 11.693 17.928 ;
     RECT  11.557 23.568 11.701 23.592 ;
     RECT  11.701 23.52 11.843 23.592 ;
     RECT  11.411 0.384 11.945 0.6 ;
     RECT  11.843 23.52 11.987 23.544 ;
     RECT  10.865 6.336 11.989 11.736 ;
     RECT  11.989 6.288 12.229 11.736 ;
     RECT  11.945 0.384 12.421 0.552 ;
     RECT  11.405 1.728 12.421 5.16 ;
     RECT  12.229 6.24 12.421 11.736 ;
     RECT  12.421 0.288 12.509 0.552 ;
     RECT  12.509 0.096 12.593 0.552 ;
     RECT  11.123 19.488 13.148 21.672 ;
     RECT  12.421 1.728 13.208 11.736 ;
     RECT  12.121 13.92 13.208 13.944 ;
     RECT  10.865 15.264 13.208 15.288 ;
     RECT  11.693 16.272 13.208 16.296 ;
     RECT  11.693 17.328 13.208 17.928 ;
     RECT  13.148 19.488 13.208 21.768 ;
     RECT  13.208 1.728 13.235 21.768 ;
     RECT  13.235 1.728 13.285 21.72 ;
     RECT  13.285 23.376 13.381 23.4 ;
     RECT  12.593 0.144 13.429 0.552 ;
     RECT  13.285 1.68 13.504 21.72 ;
     RECT  13.381 23.376 13.573 23.496 ;
     RECT  13.504 1.68 13.619 5.304 ;
     RECT  13.573 23.376 13.619 23.64 ;
     RECT  13.619 1.68 13.667 5.208 ;
     RECT  13.619 23.472 13.667 23.64 ;
     RECT  13.667 23.616 13.709 23.64 ;
     RECT  13.504 19.584 13.781 21.72 ;
     RECT  13.667 1.68 13.817 5.16 ;
     RECT  13.429 0.144 13.909 0.6 ;
     RECT  13.817 1.68 13.909 5.112 ;
     RECT  13.504 6.288 14.051 11.736 ;
     RECT  13.504 15.264 14.579 15.288 ;
     RECT  14.051 6.288 14.645 10.872 ;
     RECT  14.645 6.288 14.677 10.728 ;
     RECT  13.909 0.144 15.061 5.112 ;
     RECT  14.677 6.24 15.061 10.728 ;
     RECT  15.061 0.144 15.634 10.728 ;
     RECT  15.397 23.568 15.829 23.592 ;
     RECT  15.634 0.096 15.908 10.728 ;
     RECT  13.504 13.92 15.908 13.944 ;
     RECT  13.504 16.272 15.908 16.296 ;
     RECT  13.504 17.424 15.908 17.928 ;
     RECT  13.781 19.584 15.908 21.672 ;
     RECT  15.829 22.8 16.019 23.592 ;
     RECT  15.908 0.096 16.121 21.672 ;
     RECT  16.121 0.144 16.204 21.672 ;
     RECT  16.204 19.584 16.22 21.672 ;
     RECT  16.204 0.144 16.265 10.728 ;
     RECT  16.22 19.584 16.307 21.72 ;
     RECT  16.019 23.52 16.451 23.592 ;
     RECT  16.451 23.52 16.547 23.544 ;
     RECT  16.204 13.92 16.883 13.944 ;
     RECT  16.265 0.144 17.075 10.344 ;
     RECT  17.075 1.728 17.093 10.344 ;
     RECT  17.093 1.728 17.273 4.68 ;
     RECT  17.093 5.712 17.309 10.344 ;
     RECT  17.075 0.144 17.345 0.6 ;
     RECT  17.345 0.144 17.413 0.216 ;
     RECT  17.413 0.096 17.525 0.216 ;
     RECT  17.525 0.144 17.651 0.216 ;
     RECT  16.307 19.584 17.881 21.672 ;
     RECT  17.881 19.056 18.169 21.672 ;
     RECT  17.273 1.728 18.173 4.584 ;
     RECT  17.309 5.808 18.277 10.344 ;
     RECT  18.173 1.776 18.313 4.584 ;
     RECT  18.277 5.712 18.313 10.344 ;
     RECT  18.169 19.056 18.323 22.248 ;
     RECT  18.313 1.776 18.608 10.344 ;
     RECT  16.204 16.272 18.608 16.296 ;
     RECT  16.204 17.424 18.608 17.928 ;
     RECT  18.323 19.056 18.608 21.864 ;
     RECT  17.651 0.144 18.853 0.168 ;
     RECT  18.608 1.776 18.904 21.864 ;
     RECT  18.904 19.056 18.965 21.864 ;
     RECT  18.853 0.144 19.042 0.36 ;
     RECT  19.042 0.096 19.043 0.36 ;
     RECT  18.965 19.056 19.073 21.816 ;
     RECT  19.043 0.096 19.091 0.264 ;
     RECT  19.073 19.056 19.139 21.768 ;
     RECT  19.091 0.096 19.187 0.12 ;
     RECT  19.189 23.52 19.237 23.544 ;
     RECT  19.237 23.52 19.43 23.64 ;
     RECT  18.904 1.776 19.469 10.536 ;
     RECT  19.469 4.56 19.649 10.536 ;
     RECT  19.649 4.992 19.721 10.536 ;
     RECT  19.721 5.088 19.829 10.536 ;
     RECT  19.469 1.776 19.933 3.432 ;
     RECT  19.933 1.728 20.069 3.432 ;
     RECT  20.069 1.152 20.153 3.432 ;
     RECT  19.139 19.056 20.329 21.672 ;
     RECT  20.153 1.728 20.557 3.432 ;
     RECT  20.557 1.776 20.917 3.432 ;
     RECT  20.917 0.144 21.109 0.168 ;
     RECT  20.917 1.776 21.308 4.104 ;
     RECT  19.829 5.808 21.308 10.536 ;
     RECT  18.904 16.272 21.308 17.928 ;
     RECT  20.329 19.008 21.308 21.672 ;
     RECT  21.308 1.776 21.349 21.672 ;
     RECT  21.349 1.776 21.445 21.768 ;
     RECT  21.109 0.144 21.541 0.264 ;
     RECT  21.445 1.776 21.541 21.816 ;
     RECT  21.541 1.776 21.604 22.2 ;
     RECT  19.43 23.568 21.637 23.592 ;
     RECT  21.604 1.776 21.733 4.008 ;
     RECT  21.637 23.376 21.778 23.592 ;
     RECT  21.733 1.728 21.829 4.008 ;
     RECT  21.604 5.664 22.097 10.872 ;
     RECT  21.604 19.056 22.201 22.2 ;
     RECT  21.778 23.328 22.201 23.592 ;
     RECT  21.541 0.144 22.213 0.6 ;
     RECT  22.213 0.096 22.601 0.6 ;
     RECT  22.201 19.056 22.643 23.592 ;
     RECT  22.643 23.52 22.691 23.592 ;
     RECT  22.691 23.568 22.787 23.592 ;
     RECT  22.601 0.144 22.837 0.6 ;
     RECT  21.829 1.68 22.837 4.008 ;
     RECT  22.837 0.144 22.885 4.008 ;
     RECT  22.885 0.144 22.933 4.632 ;
     RECT  22.097 5.664 22.933 10.824 ;
     RECT  22.643 19.056 22.997 22.2 ;
     RECT  22.997 19.056 23.221 21.864 ;
     RECT  22.933 0.144 23.315 10.824 ;
     RECT  23.315 0.192 24.008 10.824 ;
     RECT  23.317 13.344 24.008 13.368 ;
     RECT  23.029 14.496 24.008 14.52 ;
     RECT  21.604 15.696 24.008 17.928 ;
     RECT  23.221 18.96 24.008 21.864 ;
     RECT  24.008 0.192 24.277 21.864 ;
     RECT  24.277 0.144 24.304 21.864 ;
     RECT  24.304 19.248 24.325 21.864 ;
     RECT  24.229 23.04 24.325 23.064 ;
     RECT  24.325 19.248 24.421 23.064 ;
     RECT  24.421 19.248 24.509 23.16 ;
     RECT  24.304 0.144 24.677 11.256 ;
     RECT  24.677 0.096 25.091 11.256 ;
     RECT  24.509 19.248 25.121 22.248 ;
     RECT  24.304 14.496 25.429 14.52 ;
     RECT  25.121 19.248 25.475 21.528 ;
     RECT  25.091 0.096 25.873 0.648 ;
     RECT  24.304 13.344 25.909 13.368 ;
     RECT  25.429 14.496 25.909 14.712 ;
     RECT  25.091 1.728 26.305 11.256 ;
     RECT  24.304 12.24 26.305 12.312 ;
     RECT  25.873 0.048 26.413 0.648 ;
     RECT  26.305 1.728 26.413 12.312 ;
     RECT  26.197 22.8 26.483 22.824 ;
     RECT  26.413 0.048 26.579 12.312 ;
     RECT  25.475 19.248 26.581 21.48 ;
     RECT  26.581 19.056 26.588 21.48 ;
     RECT  26.588 19.056 26.665 21.768 ;
     RECT  26.579 1.968 26.708 12.312 ;
     RECT  25.909 13.344 26.708 14.712 ;
     RECT  24.304 15.744 26.708 17.928 ;
     RECT  26.665 19.056 26.708 21.864 ;
     RECT  26.708 1.968 26.771 21.864 ;
     RECT  26.771 1.968 27.004 21.816 ;
     RECT  27.004 19.056 27.101 21.816 ;
     RECT  26.579 0.048 27.155 0.456 ;
     RECT  27.101 19.056 27.443 21.672 ;
     RECT  27.004 1.968 27.965 12.312 ;
     RECT  27.155 0.048 28.001 0.36 ;
     RECT  27.965 1.968 28.325 11.256 ;
     RECT  28.001 0.096 28.441 0.36 ;
     RECT  28.441 0.144 28.645 0.36 ;
     RECT  29.173 23.328 29.213 23.352 ;
     RECT  29.213 23.232 29.221 23.352 ;
     RECT  28.645 0.144 29.317 1.272 ;
     RECT  28.325 2.256 29.317 11.256 ;
     RECT  29.317 0.144 29.363 11.256 ;
     RECT  29.221 22.992 29.363 23.352 ;
     RECT  27.443 19.056 29.365 21.528 ;
     RECT  29.363 1.68 29.408 11.256 ;
     RECT  27.965 12.24 29.408 12.312 ;
     RECT  27.004 13.344 29.408 14.712 ;
     RECT  27.004 15.744 29.408 17.928 ;
     RECT  29.365 19.056 29.408 21.768 ;
     RECT  29.408 1.68 29.459 21.768 ;
     RECT  29.363 23.328 29.555 23.352 ;
     RECT  29.459 1.68 29.692 21.72 ;
     RECT  29.692 1.68 29.704 21.624 ;
     RECT  29.701 23.376 29.797 23.448 ;
     RECT  29.797 23.376 29.842 23.592 ;
     RECT  29.363 0.144 29.891 0.696 ;
     RECT  29.842 23.376 29.953 23.64 ;
     RECT  29.953 23.376 30.179 23.592 ;
     RECT  30.179 23.376 30.227 23.4 ;
     RECT  29.704 1.68 30.233 12.312 ;
     RECT  30.233 1.68 30.515 4.008 ;
     RECT  30.233 5.088 30.659 12.312 ;
     RECT  29.704 19.056 30.773 21.624 ;
     RECT  29.704 15.696 30.809 17.928 ;
     RECT  29.891 0.192 30.898 0.696 ;
     RECT  30.898 0.096 30.917 0.696 ;
     RECT  30.757 22.752 30.947 22.776 ;
     RECT  30.659 5.088 31.139 12.264 ;
     RECT  30.917 0.096 31.169 0.6 ;
     RECT  31.169 0.096 31.475 0.36 ;
     RECT  31.139 5.088 31.597 11.928 ;
     RECT  31.877 23.28 31.909 23.304 ;
     RECT  30.773 19.056 32.005 21.528 ;
     RECT  32.005 19.056 32.065 21.72 ;
     RECT  30.515 1.728 32.108 4.008 ;
     RECT  31.597 4.992 32.108 11.928 ;
     RECT  29.704 13.344 32.108 14.712 ;
     RECT  30.809 15.792 32.108 17.928 ;
     RECT  32.065 19.056 32.108 21.816 ;
     RECT  32.108 1.728 32.149 21.816 ;
     RECT  31.909 23.04 32.243 23.304 ;
     RECT  32.149 1.728 32.339 21.72 ;
     RECT  32.339 1.728 32.404 21.432 ;
     RECT  32.389 23.472 32.537 23.64 ;
     RECT  31.475 0.096 32.581 0.264 ;
     RECT  32.581 0.096 32.773 0.6 ;
     RECT  32.537 23.472 32.963 23.592 ;
     RECT  32.773 0.096 32.965 0.648 ;
     RECT  32.404 1.728 32.969 11.448 ;
     RECT  32.969 1.824 33.041 11.448 ;
     RECT  32.965 0.096 33.049 0.696 ;
     RECT  32.963 23.568 33.443 23.592 ;
     RECT  32.404 15.792 33.637 21.432 ;
     RECT  33.041 2.304 34.117 11.448 ;
     RECT  33.049 0.144 34.157 0.696 ;
     RECT  34.117 2.304 34.333 12.264 ;
     RECT  34.157 0.144 34.517 0.648 ;
     RECT  33.637 15.792 34.789 21.672 ;
     RECT  34.333 2.256 34.808 12.264 ;
     RECT  32.404 13.344 34.808 14.712 ;
     RECT  34.789 15.792 34.808 21.768 ;
     RECT  34.808 2.148 34.981 21.768 ;
     RECT  34.981 2.016 34.985 21.768 ;
     RECT  34.985 2.016 35.077 21.72 ;
     RECT  34.885 23.424 35.077 23.448 ;
     RECT  35.077 1.968 35.104 21.72 ;
     RECT  35.104 15.792 35.165 21.72 ;
     RECT  35.104 1.968 35.233 10.728 ;
     RECT  35.077 23.424 35.353 23.64 ;
     RECT  35.233 1.728 35.417 10.728 ;
     RECT  34.517 0.144 35.557 0.36 ;
     RECT  35.353 23.52 35.597 23.64 ;
     RECT  35.165 15.792 35.699 21.672 ;
     RECT  35.557 0.144 35.749 0.552 ;
     RECT  35.597 23.52 35.843 23.544 ;
     RECT  35.749 0.096 35.921 0.552 ;
     RECT  35.417 1.728 36.028 10.632 ;
     RECT  36.028 1.728 36.037 4.104 ;
     RECT  36.028 5.088 36.245 10.632 ;
     RECT  36.037 0.576 36.419 4.104 ;
     RECT  36.245 6.672 36.421 10.632 ;
     RECT  36.419 0.576 36.467 0.696 ;
     RECT  35.699 15.792 36.701 21.432 ;
     RECT  36.419 1.728 36.997 4.104 ;
     RECT  36.245 5.088 36.997 5.112 ;
     RECT  37.237 23.52 37.333 23.544 ;
     RECT  36.421 6.672 37.465 10.68 ;
     RECT  36.701 15.792 37.465 21.672 ;
     RECT  36.997 1.728 37.508 5.112 ;
     RECT  37.465 6.672 37.508 10.92 ;
     RECT  35.104 12.24 37.508 12.264 ;
     RECT  35.104 13.344 37.508 13.368 ;
     RECT  35.104 14.496 37.508 14.712 ;
     RECT  37.465 15.792 37.508 21.72 ;
     RECT  37.333 23.52 37.523 23.592 ;
     RECT  37.237 0.144 37.619 0.168 ;
     RECT  37.523 23.52 37.619 23.544 ;
     RECT  37.508 1.728 37.804 21.72 ;
     RECT  37.804 15.696 37.861 21.72 ;
     RECT  37.861 0.528 38.045 0.552 ;
     RECT  37.861 15.696 38.147 21.768 ;
     RECT  37.804 1.728 38.261 4.008 ;
     RECT  38.396 23.472 38.437 23.496 ;
     RECT  38.437 23.376 38.531 23.496 ;
     RECT  37.804 6.624 38.675 10.92 ;
     RECT  38.531 23.472 38.723 23.496 ;
     RECT  38.147 15.696 38.801 21.672 ;
     RECT  37.804 13.344 39.157 13.368 ;
     RECT  38.261 1.728 39.265 3.432 ;
     RECT  39.265 1.728 39.397 4.056 ;
     RECT  39.397 1.152 39.445 4.056 ;
     RECT  39.445 1.152 39.589 4.584 ;
     RECT  39.589 0.384 39.637 4.584 ;
     RECT  39.637 0.288 39.653 4.584 ;
     RECT  38.675 6.672 39.697 10.92 ;
     RECT  39.653 0.192 39.73 4.584 ;
     RECT  39.73 0.096 39.841 4.584 ;
     RECT  39.925 23.472 39.941 23.496 ;
     RECT  39.941 23.472 39.973 23.592 ;
     RECT  39.973 23.328 39.985 23.592 ;
     RECT  39.985 23.28 40.057 23.592 ;
     RECT  39.841 0.096 40.069 4.776 ;
     RECT  39.697 6 40.069 10.92 ;
     RECT  40.057 23.28 40.115 23.64 ;
     RECT  40.069 0.096 40.208 10.92 ;
     RECT  37.804 12.24 40.208 12.264 ;
     RECT  39.157 13.344 40.208 13.416 ;
     RECT  37.804 14.496 40.208 14.712 ;
     RECT  38.801 15.792 40.208 21.672 ;
     RECT  40.115 23.328 40.307 23.64 ;
     RECT  40.208 0.096 40.453 21.672 ;
     RECT  40.453 0.096 40.504 21.72 ;
     RECT  40.504 15.792 40.549 21.72 ;
     RECT  40.307 23.616 40.601 23.64 ;
     RECT  40.549 15.792 40.637 21.768 ;
     RECT  40.504 0.096 40.853 12.264 ;
     RECT  40.853 0.576 41.213 12.264 ;
     RECT  41.413 23.568 41.603 23.592 ;
     RECT  41.213 1.152 41.753 12.264 ;
     RECT  41.753 5.712 41.933 12.264 ;
     RECT  41.753 1.152 41.969 4.728 ;
     RECT  41.969 1.2 42.035 4.728 ;
     RECT  42.035 1.728 42.908 4.728 ;
     RECT  41.933 5.712 42.908 11.256 ;
     RECT  41.933 12.24 42.908 12.264 ;
     RECT  40.504 13.344 42.908 13.416 ;
     RECT  40.504 14.496 42.908 14.712 ;
     RECT  40.637 15.792 42.908 21.672 ;
     RECT  42.908 1.728 42.949 21.672 ;
     RECT  42.949 1.728 43.045 21.768 ;
     RECT  42.853 22.752 43.045 22.776 ;
     RECT  43.045 1.728 43.141 22.776 ;
     RECT  43.141 1.728 43.204 23.592 ;
     RECT  43.204 15.792 43.265 23.592 ;
     RECT  43.265 15.792 43.301 21.72 ;
     RECT  43.265 22.752 43.33 23.592 ;
     RECT  43.301 15.792 43.445 21.672 ;
     RECT  43.33 22.752 43.571 23.64 ;
     RECT  43.204 1.728 43.589 12.264 ;
     RECT  43.589 12.24 43.619 12.264 ;
     RECT  43.204 13.344 43.625 13.416 ;
     RECT  43.204 14.64 44.165 14.808 ;
     RECT  44.165 14.64 44.201 14.664 ;
     RECT  43.589 1.728 44.417 11.256 ;
     RECT  43.571 22.752 44.453 22.776 ;
     RECT  43.445 15.792 44.557 16.296 ;
     RECT  43.445 17.424 44.557 21.672 ;
     RECT  44.557 15.792 44.561 21.672 ;
     RECT  44.417 1.728 44.579 11.16 ;
     RECT  43.237 0.576 44.773 0.6 ;
     RECT  44.773 0.096 45.013 0.6 ;
     RECT  44.579 1.728 45.013 4.104 ;
     RECT  45.013 0.096 45.062 4.104 ;
     RECT  44.579 5.136 45.445 11.16 ;
     RECT  45.062 0.144 45.608 4.104 ;
     RECT  45.445 5.136 45.608 11.208 ;
     RECT  43.625 13.392 45.608 13.416 ;
     RECT  44.561 16.272 45.608 21.672 ;
     RECT  45.608 0.144 45.637 21.672 ;
     RECT  45.637 0.144 45.733 21.768 ;
     RECT  45.733 0.144 45.904 21.816 ;
     RECT  45.904 20.16 45.965 21.816 ;
     RECT  45.965 20.16 46.001 21.72 ;
     RECT  45.829 23.568 46.019 23.592 ;
     RECT  45.904 0.144 46.076 11.208 ;
     RECT  46.021 22.752 46.181 22.776 ;
     RECT  46.001 20.16 46.933 21.672 ;
     RECT  46.933 19.968 47.041 21.672 ;
     RECT  46.076 0.096 47.125 11.208 ;
     RECT  45.904 16.272 47.267 17.928 ;
     RECT  47.041 19.872 47.797 21.672 ;
     RECT  47.797 19.824 47.869 21.672 ;
     RECT  47.125 0.192 47.891 11.208 ;
     RECT  47.869 19.728 48.188 21.672 ;
     RECT  47.891 0.384 48.308 11.208 ;
     RECT  47.267 16.272 48.308 16.296 ;
     RECT  47.267 17.424 48.308 17.928 ;
     RECT  48.188 19.728 48.308 21.768 ;
     RECT  48.308 0.384 48.604 21.768 ;
     RECT  47.893 23.568 48.613 23.592 ;
     RECT  48.604 0.384 48.755 11.16 ;
     RECT  48.613 23.328 48.755 23.592 ;
     RECT  48.755 23.376 48.805 23.592 ;
     RECT  48.805 23.376 48.889 23.64 ;
     RECT  48.755 0.384 48.901 3.624 ;
     RECT  48.889 23.376 48.947 23.592 ;
     RECT  48.947 23.52 48.961 23.592 ;
     RECT  48.901 0.288 48.994 3.624 ;
     RECT  48.604 19.824 49.021 21.768 ;
     RECT  49.021 19.824 49.187 22.248 ;
     RECT  48.961 23.52 49.187 23.544 ;
     RECT  49.187 19.824 49.349 21.672 ;
     RECT  49.349 19.824 49.772 21.624 ;
     RECT  48.994 0.096 49.813 3.624 ;
     RECT  48.755 4.848 49.813 11.16 ;
     RECT  48.604 17.424 49.957 17.928 ;
     RECT  48.604 16.272 50.029 16.296 ;
     RECT  49.957 17.424 50.029 17.976 ;
     RECT  49.813 0.096 50.041 11.16 ;
     RECT  50.041 0.144 50.147 11.16 ;
     RECT  49.772 19.776 50.348 21.624 ;
     RECT  50.348 19.632 50.353 21.624 ;
     RECT  50.147 0.576 50.533 11.16 ;
     RECT  50.353 19.632 50.533 21.672 ;
     RECT  50.533 0.576 50.713 11.496 ;
     RECT  50.533 19.632 50.773 22.488 ;
     RECT  50.389 23.568 50.773 23.592 ;
     RECT  50.773 19.632 50.963 23.592 ;
     RECT  50.713 0.576 51.008 11.832 ;
     RECT  50.029 16.272 51.008 17.976 ;
     RECT  50.963 19.632 51.008 22.488 ;
     RECT  51.008 0.576 51.109 22.488 ;
     RECT  50.963 23.472 51.109 23.592 ;
     RECT  51.109 0.144 51.304 22.488 ;
     RECT  51.109 23.472 51.473 23.64 ;
     RECT  51.304 19.056 51.905 22.488 ;
     RECT  51.304 0.144 51.973 11.928 ;
     RECT  51.973 0.096 52.229 11.928 ;
     RECT  51.473 23.472 52.549 23.592 ;
     RECT  52.549 23.376 52.645 23.592 ;
     RECT  52.229 0.096 53.221 3.432 ;
     RECT  52.229 4.56 53.221 11.928 ;
     RECT  53.221 0.096 53.269 11.928 ;
     RECT  53.269 0.096 53.273 12.024 ;
     RECT  52.645 23.376 53.317 23.64 ;
     RECT  53.317 23.328 53.555 23.64 ;
     RECT  53.273 0.144 53.708 12.024 ;
     RECT  53.413 14.784 53.708 14.808 ;
     RECT  51.304 16.272 53.708 16.296 ;
     RECT  51.304 17.424 53.708 17.976 ;
     RECT  51.905 19.056 53.708 21.528 ;
     RECT  53.555 23.472 53.747 23.64 ;
     RECT  53.708 0.144 53.797 21.612 ;
     RECT  53.797 0.144 54.004 21.768 ;
     RECT  54.004 19.056 54.085 21.768 ;
     RECT  53.747 23.52 54.145 23.64 ;
     RECT  54.085 19.056 54.172 21.864 ;
     RECT  54.004 0.144 54.281 12.024 ;
     RECT  54.281 1.152 54.467 12.024 ;
     RECT  54.467 1.344 54.563 12.024 ;
     RECT  54.563 1.68 55.043 12.024 ;
     RECT  54.281 0.144 55.139 0.168 ;
     RECT  54.172 19.056 55.285 21.528 ;
     RECT  55.285 19.056 55.321 21.672 ;
     RECT  55.321 19.056 55.475 21.768 ;
     RECT  54.004 17.424 55.765 17.976 ;
     RECT  55.475 19.056 55.765 21.612 ;
     RECT  54.145 23.52 56.101 23.592 ;
     RECT  55.043 1.728 56.408 12.024 ;
     RECT  55.669 14.736 56.408 14.76 ;
     RECT  54.004 16.272 56.408 16.296 ;
     RECT  55.765 17.424 56.408 21.612 ;
     RECT  56.245 0.144 56.485 0.168 ;
     RECT  56.101 23.52 56.485 23.64 ;
     RECT  56.408 1.728 56.629 21.612 ;
     RECT  56.485 23.328 56.629 23.64 ;
     RECT  56.629 1.728 56.704 21.816 ;
     RECT  56.704 17.424 56.837 21.816 ;
     RECT  56.485 0.144 56.869 0.6 ;
     RECT  56.629 23.28 56.873 23.64 ;
     RECT  56.869 0.096 56.953 0.696 ;
     RECT  56.873 23.376 57.491 23.64 ;
     RECT  57.491 23.424 57.593 23.64 ;
     RECT  56.837 17.424 57.635 21.72 ;
     RECT  57.593 23.424 57.779 23.592 ;
     RECT  57.635 18.48 57.913 21.72 ;
     RECT  57.779 23.52 58.019 23.592 ;
     RECT  57.913 18.48 58.259 22.296 ;
     RECT  56.953 0.576 58.373 0.696 ;
     RECT  56.704 1.728 58.705 11.448 ;
     RECT  58.373 0.096 58.741 0.696 ;
     RECT  58.705 1.728 58.741 11.544 ;
     RECT  58.741 0.096 59.108 11.544 ;
     RECT  56.704 14.736 59.108 14.76 ;
     RECT  56.704 16.272 59.108 16.296 ;
     RECT  57.635 17.424 59.108 17.448 ;
     RECT  58.259 18.48 59.108 21.768 ;
     RECT  58.019 23.568 59.219 23.592 ;
     RECT  59.108 0.096 59.404 21.768 ;
     RECT  59.404 18.48 59.461 21.768 ;
     RECT  59.461 18.48 59.557 22.008 ;
     RECT  59.557 18.48 59.747 22.104 ;
     RECT  59.404 0.096 59.789 11.832 ;
     RECT  60.229 23.616 60.277 23.64 ;
     RECT  60.277 23.424 60.365 23.64 ;
     RECT  59.789 4.56 60.371 11.832 ;
     RECT  60.371 4.56 60.401 6.456 ;
     RECT  59.789 0.096 60.757 3.528 ;
     RECT  60.401 4.56 60.757 5.16 ;
     RECT  59.404 14.832 60.793 14.856 ;
     RECT  60.371 7.44 60.803 11.832 ;
     RECT  59.747 18.48 60.829 21.672 ;
     RECT  60.365 23.424 60.865 23.544 ;
     RECT  60.803 7.488 61.009 11.832 ;
     RECT  59.404 17.424 61.153 17.448 ;
     RECT  60.829 18.432 61.153 21.672 ;
     RECT  61.153 17.424 61.225 21.672 ;
     RECT  60.865 22.848 61.225 23.544 ;
     RECT  60.757 0.096 61.229 5.16 ;
     RECT  61.009 7.488 61.297 12.6 ;
     RECT  61.225 17.424 61.369 23.544 ;
     RECT  61.229 0.144 61.523 5.16 ;
     RECT  61.369 17.424 61.625 23.64 ;
     RECT  61.625 17.424 61.667 23.544 ;
     RECT  61.523 0.576 61.669 5.16 ;
     RECT  60.401 6.24 61.669 6.456 ;
     RECT  61.669 0.576 61.808 6.456 ;
     RECT  61.297 7.488 61.808 12.792 ;
     RECT  60.793 14.832 61.808 14.904 ;
     RECT  59.404 16.272 61.808 16.296 ;
     RECT  61.667 17.424 61.808 23.448 ;
     RECT  61.808 0.576 61.811 23.448 ;
     RECT  61.811 0.576 62.003 22.872 ;
     RECT  62.003 1.92 62.104 22.872 ;
     RECT  62.104 17.52 62.317 22.872 ;
     RECT  62.317 17.664 62.339 22.872 ;
     RECT  62.339 18.192 62.387 22.872 ;
     RECT  62.104 1.92 62.428 5.256 ;
     RECT  62.428 1.92 62.435 4.2 ;
     RECT  62.428 5.232 62.435 5.256 ;
     RECT  62.435 2.304 62.483 4.2 ;
     RECT  62.483 2.304 62.531 3.432 ;
     RECT  62.104 9.072 62.531 9.096 ;
     RECT  62.531 2.496 62.597 3.432 ;
     RECT  62.104 6.288 62.605 7.416 ;
     RECT  62.605 6.288 62.669 6.312 ;
     RECT  62.597 2.784 62.675 3.432 ;
     RECT  62.605 7.392 62.675 7.416 ;
     RECT  62.104 11.952 62.813 11.976 ;
     RECT  62.675 2.784 62.849 2.856 ;
     RECT  62.387 18.24 62.953 22.872 ;
     RECT  62.849 2.832 62.963 2.856 ;
     RECT  62.953 18.24 62.963 22.92 ;
     RECT  62.963 19.872 63.059 22.92 ;
     RECT  62.003 0.576 63.065 0.696 ;
     RECT  63.065 0.672 63.101 0.696 ;
     RECT  63.059 20.64 63.251 22.92 ;
     RECT  63.251 21.12 63.347 22.92 ;
     RECT  62.963 18.24 63.443 18.84 ;
     RECT  63.347 21.12 63.635 21.672 ;
     RECT  63.443 18.24 63.731 18.264 ;
     RECT  63.347 22.8 63.827 22.92 ;
     RECT  63.827 22.896 63.923 22.92 ;
     RECT  63.635 21.12 64.019 21.144 ;
    LAYER M5 ;
     RECT  0.72 0.016 62.952 2.819 ;
     RECT  0.816 2.819 62.952 2.867 ;
     RECT  0.816 2.867 62.664 4.019 ;
     RECT  1.2 4.019 62.664 4.067 ;
     RECT  1.392 4.067 62.664 4.595 ;
     RECT  1.584 4.595 62.664 4.691 ;
     RECT  2.208 4.691 62.664 5.075 ;
     RECT  2.256 5.075 62.664 5.171 ;
     RECT  2.304 5.171 62.664 6.323 ;
     RECT  2.4 6.323 62.664 7.139 ;
     RECT  46.992 7.139 62.664 7.427 ;
     RECT  2.4 7.139 45.912 7.523 ;
     RECT  2.4 7.523 2.904 8.003 ;
     RECT  4.464 7.523 45.912 8.003 ;
     RECT  46.992 7.427 62.52 8.483 ;
     RECT  4.848 8.003 45.912 8.579 ;
     RECT  46.992 8.483 59.412 8.579 ;
     RECT  60.384 8.483 62.52 8.579 ;
     RECT  4.992 8.579 27.864 8.675 ;
     RECT  46.992 8.579 47.112 9.107 ;
     RECT  61.632 8.579 62.52 9.107 ;
     RECT  14.496 8.675 27.864 9.155 ;
     RECT  29.4 8.579 45.912 9.155 ;
     RECT  61.632 9.107 62.112 9.155 ;
     RECT  14.496 9.155 22.824 9.203 ;
     RECT  60.384 8.579 60.408 9.251 ;
     RECT  29.4 9.155 41.016 9.299 ;
     RECT  42.288 9.155 45.912 9.299 ;
     RECT  42.72 9.299 45.912 9.347 ;
     RECT  29.4 9.299 33.048 9.395 ;
     RECT  21.168 9.203 22.824 9.587 ;
     RECT  14.496 9.203 20.04 9.683 ;
     RECT  42.9 9.347 45.912 9.683 ;
     RECT  4.992 8.675 13.512 9.685 ;
     RECT  14.592 9.683 20.04 9.731 ;
     RECT  30.816 9.395 33.048 9.731 ;
     RECT  34.176 9.299 39.096 9.779 ;
     RECT  2.4 8.003 2.712 9.877 ;
     RECT  45.024 9.683 45.912 9.971 ;
     RECT  45.408 9.971 45.912 10.165 ;
     RECT  47.04 9.107 47.112 10.165 ;
     RECT  14.592 9.731 16.824 10.211 ;
     RECT  21.168 9.587 22.584 10.211 ;
     RECT  48.3 8.579 57.336 10.259 ;
     RECT  4.608 9.685 13.512 10.307 ;
     RECT  14.592 10.211 16.392 10.307 ;
     RECT  17.904 9.731 20.04 10.307 ;
     RECT  24 9.155 27.864 10.307 ;
     RECT  31.248 9.731 33.048 10.307 ;
     RECT  34.464 9.779 39.096 10.307 ;
     RECT  20.016 10.307 20.04 10.355 ;
     RECT  34.464 10.307 35.208 10.355 ;
     RECT  42.9 9.683 43.704 10.355 ;
     RECT  45.408 10.165 47.112 10.355 ;
     RECT  49.68 10.259 57.336 10.453 ;
     RECT  58.32 8.579 59.412 10.453 ;
     RECT  2.4 9.877 3.048 10.597 ;
     RECT  34.704 10.355 35.208 10.691 ;
     RECT  9.504 10.307 13.512 10.693 ;
     RECT  14.592 10.307 14.616 10.693 ;
     RECT  2.4 10.597 3.144 10.787 ;
     RECT  21.3 10.211 22.584 10.789 ;
     RECT  24 10.307 24.792 10.789 ;
     RECT  2.4 10.787 3.048 10.835 ;
     RECT  9.504 10.693 14.616 10.883 ;
     RECT  32.1 10.307 32.808 10.883 ;
     RECT  45.408 10.355 45.912 10.883 ;
     RECT  49.68 10.453 59.412 10.883 ;
     RECT  55.296 10.883 59.412 10.931 ;
     RECT  53.7 10.883 54.168 11.075 ;
     RECT  56.064 10.931 59.412 11.171 ;
     RECT  0.144 10.069 0.168 11.219 ;
     RECT  45.456 10.883 45.912 11.219 ;
     RECT  21.3 10.789 24.792 11.267 ;
     RECT  56.112 11.171 59.412 11.411 ;
     RECT  34.704 10.691 35.112 11.459 ;
     RECT  40.2 9.299 41.016 11.459 ;
     RECT  52.416 10.883 52.44 11.459 ;
     RECT  4.608 10.307 8.472 12.035 ;
     RECT  42.9 10.355 43.56 12.229 ;
     RECT  29.4 9.395 29.712 12.277 ;
     RECT  31.104 12.229 31.128 12.277 ;
     RECT  45.504 11.219 45.912 13.381 ;
     RECT  15.9 10.307 16.392 13.909 ;
     RECT  34.8 11.459 35.112 13.909 ;
     RECT  26.064 10.307 27.012 14.629 ;
     RECT  25.92 14.629 27.012 14.677 ;
     RECT  56.112 11.411 57.336 14.725 ;
     RECT  9.504 10.883 14.04 15.253 ;
     RECT  47.088 10.355 47.112 17.125 ;
     RECT  47.088 17.125 47.256 17.171 ;
     RECT  50.256 10.883 51.312 17.171 ;
     RECT  2.4 10.835 2.712 17.413 ;
     RECT  61.8 9.155 62.112 17.509 ;
     RECT  61.8 17.509 62.28 17.605 ;
     RECT  61.68 17.605 62.28 17.653 ;
     RECT  2.4 17.413 3.528 17.893 ;
     RECT  4.608 12.035 6.792 17.893 ;
     RECT  55.68 14.725 57.336 17.941 ;
     RECT  58.368 11.411 59.412 17.941 ;
     RECT  61.68 17.653 62.328 18.037 ;
     RECT  61.488 18.037 62.328 18.133 ;
     RECT  61.344 18.133 62.328 18.181 ;
     RECT  45.408 13.381 45.912 18.469 ;
     RECT  63.696 18.229 63.72 18.805 ;
     RECT  61.2 18.181 62.376 19.093 ;
     RECT  60.816 19.093 62.376 19.189 ;
     RECT  17.904 10.307 18.912 19.237 ;
     RECT  25.44 14.677 27.012 19.285 ;
     RECT  17.904 19.237 19.224 19.333 ;
     RECT  33.984 13.909 35.112 19.333 ;
     RECT  55.68 17.941 59.412 19.333 ;
     RECT  60.768 19.189 62.376 19.333 ;
     RECT  63.408 18.805 63.72 19.333 ;
     RECT  29.4 12.277 31.128 19.525 ;
     RECT  32.1 10.883 32.412 19.525 ;
     RECT  42.9 12.229 43.608 19.525 ;
     RECT  53.7 11.075 54.012 19.525 ;
     RECT  9.504 15.253 14.568 19.621 ;
     RECT  15.9 13.909 16.872 19.621 ;
     RECT  29.4 19.525 32.412 19.621 ;
     RECT  33.984 19.333 35.304 19.621 ;
     RECT  36.48 19.381 36.504 19.621 ;
     RECT  50.448 17.171 51.312 19.621 ;
     RECT  53.7 19.525 54.696 19.621 ;
     RECT  47.232 17.171 47.256 19.717 ;
     RECT  48.3 10.259 48.612 19.717 ;
     RECT  21.3 11.267 24.312 19.765 ;
     RECT  25.44 19.285 27.96 19.765 ;
     RECT  50.4 19.621 51.312 19.765 ;
     RECT  9.504 19.621 16.872 19.813 ;
     RECT  17.904 19.333 19.704 19.813 ;
     RECT  29.4 19.621 36.504 19.813 ;
     RECT  42.9 19.525 43.752 19.813 ;
     RECT  49.824 19.765 51.312 19.813 ;
     RECT  52.848 19.621 54.696 19.813 ;
     RECT  2.4 17.893 6.792 19.861 ;
     RECT  9.504 19.813 19.704 19.861 ;
     RECT  29.184 19.813 36.504 19.861 ;
     RECT  37.5 10.307 39.096 19.861 ;
     RECT  49.824 19.813 54.696 19.861 ;
     RECT  55.68 19.333 63.72 19.861 ;
     RECT  7.8 12.035 8.472 19.909 ;
     RECT  9.504 19.861 20.232 19.909 ;
     RECT  21.3 19.765 27.96 19.909 ;
     RECT  29.184 19.861 39.096 19.909 ;
     RECT  40.2 11.459 40.512 19.909 ;
     RECT  42.576 19.813 43.752 19.909 ;
     RECT  44.976 18.469 45.912 19.909 ;
     RECT  47.232 19.717 48.612 19.909 ;
     RECT  49.824 19.861 63.72 19.909 ;
     RECT  2.304 19.861 6.792 19.957 ;
     RECT  7.8 19.909 40.512 19.957 ;
     RECT  2.304 19.957 40.512 20.053 ;
     RECT  41.568 19.909 45.912 20.053 ;
     RECT  2.304 20.053 45.912 20.149 ;
     RECT  47.184 19.909 63.72 20.149 ;
     RECT  2.064 20.149 63.72 21.109 ;
     RECT  1.872 21.109 64.008 23.696 ;
  END
END hbfd_rly_624_NS_rr
END LIBRARY
